VERSION 5.8 ;
BUSBITCHARS "[]" ;
DIVIDERCHAR "/" ;
UNITS
    DATABASE MICRONS 1000 ;
END UNITS

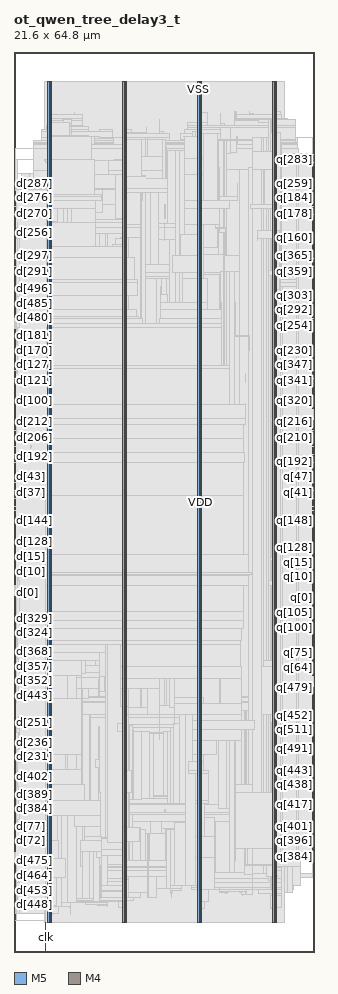
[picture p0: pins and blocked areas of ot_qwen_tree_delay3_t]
MACRO ot_qwen_tree_delay3_t
  FOREIGN ot_qwen_tree_delay3_t 0 0 ;
  CLASS BLOCK ;
  SIZE 21.6 BY 64.8 ;
  PIN clk
    DIRECTION INPUT ;
    USE SIGNAL ;
    PORT
      LAYER M5 ;
        RECT  2.256 0 2.28 0.084 ;
    END
    PORT
      LAYER M5 ;
        RECT  2.256 0.016 2.28 2.137 ;
    END
  END clk
  PIN d[0]
    DIRECTION INPUT ;
    USE SIGNAL ;
    PORT
      LAYER M4 ;
        RECT  0 26.448 0.084 26.472 ;
    END
  END d[0]
  PIN d[100]
    DIRECTION INPUT ;
    USE SIGNAL ;
    PORT
      LAYER M4 ;
        RECT  0 39.12 0.084 39.144 ;
    END
  END d[100]
  PIN d[101]
    DIRECTION INPUT ;
    USE SIGNAL ;
    PORT
      LAYER M4 ;
        RECT  0 39.216 0.084 39.24 ;
    END
  END d[101]
  PIN d[102]
    DIRECTION INPUT ;
    USE SIGNAL ;
    PORT
      LAYER M4 ;
        RECT  0 39.312 0.084 39.336 ;
    END
  END d[102]
  PIN d[103]
    DIRECTION INPUT ;
    USE SIGNAL ;
    PORT
      LAYER M4 ;
        RECT  0 39.408 0.084 39.432 ;
    END
  END d[103]
  PIN d[104]
    DIRECTION INPUT ;
    USE SIGNAL ;
    PORT
      LAYER M4 ;
        RECT  0 39.504 0.084 39.528 ;
    END
  END d[104]
  PIN d[105]
    DIRECTION INPUT ;
    USE SIGNAL ;
    PORT
      LAYER M4 ;
        RECT  0 39.6 0.084 39.624 ;
    END
  END d[105]
  PIN d[106]
    DIRECTION INPUT ;
    USE SIGNAL ;
    PORT
      LAYER M4 ;
        RECT  0 39.696 0.084 39.72 ;
    END
  END d[106]
  PIN d[107]
    DIRECTION INPUT ;
    USE SIGNAL ;
    PORT
      LAYER M4 ;
        RECT  0 39.792 0.084 39.816 ;
    END
  END d[107]
  PIN d[108]
    DIRECTION INPUT ;
    USE SIGNAL ;
    PORT
      LAYER M4 ;
        RECT  0 39.888 0.084 39.912 ;
    END
  END d[108]
  PIN d[109]
    DIRECTION INPUT ;
    USE SIGNAL ;
    PORT
      LAYER M4 ;
        RECT  0 39.984 0.084 40.008 ;
    END
  END d[109]
  PIN d[10]
    DIRECTION INPUT ;
    USE SIGNAL ;
    PORT
      LAYER M4 ;
        RECT  0 27.408 0.084 27.432 ;
    END
  END d[10]
  PIN d[110]
    DIRECTION INPUT ;
    USE SIGNAL ;
    PORT
      LAYER M4 ;
        RECT  0 40.08 0.084 40.104 ;
    END
  END d[110]
  PIN d[111]
    DIRECTION INPUT ;
    USE SIGNAL ;
    PORT
      LAYER M4 ;
        RECT  0 40.176 0.084 40.2 ;
    END
  END d[111]
  PIN d[112]
    DIRECTION INPUT ;
    USE SIGNAL ;
    PORT
      LAYER M4 ;
        RECT  0 40.272 0.084 40.296 ;
    END
  END d[112]
  PIN d[113]
    DIRECTION INPUT ;
    USE SIGNAL ;
    PORT
      LAYER M4 ;
        RECT  0 40.368 0.084 40.392 ;
    END
  END d[113]
  PIN d[114]
    DIRECTION INPUT ;
    USE SIGNAL ;
    PORT
      LAYER M4 ;
        RECT  0 40.464 0.084 40.488 ;
    END
  END d[114]
  PIN d[115]
    DIRECTION INPUT ;
    USE SIGNAL ;
    PORT
      LAYER M4 ;
        RECT  0 40.56 0.084 40.584 ;
    END
  END d[115]
  PIN d[116]
    DIRECTION INPUT ;
    USE SIGNAL ;
    PORT
      LAYER M4 ;
        RECT  0 40.656 0.084 40.68 ;
    END
  END d[116]
  PIN d[117]
    DIRECTION INPUT ;
    USE SIGNAL ;
    PORT
      LAYER M4 ;
        RECT  0 40.752 0.084 40.776 ;
    END
  END d[117]
  PIN d[118]
    DIRECTION INPUT ;
    USE SIGNAL ;
    PORT
      LAYER M4 ;
        RECT  0 40.848 0.084 40.872 ;
    END
  END d[118]
  PIN d[119]
    DIRECTION INPUT ;
    USE SIGNAL ;
    PORT
      LAYER M4 ;
        RECT  0 40.944 0.084 40.968 ;
    END
  END d[119]
  PIN d[11]
    DIRECTION INPUT ;
    USE SIGNAL ;
    PORT
      LAYER M4 ;
        RECT  0 27.504 0.084 27.528 ;
    END
  END d[11]
  PIN d[120]
    DIRECTION INPUT ;
    USE SIGNAL ;
    PORT
      LAYER M4 ;
        RECT  0 41.04 0.084 41.064 ;
    END
  END d[120]
  PIN d[121]
    DIRECTION INPUT ;
    USE SIGNAL ;
    PORT
      LAYER M4 ;
        RECT  0 41.136 0.084 41.16 ;
    END
  END d[121]
  PIN d[122]
    DIRECTION INPUT ;
    USE SIGNAL ;
    PORT
      LAYER M4 ;
        RECT  0 41.232 0.084 41.256 ;
    END
  END d[122]
  PIN d[123]
    DIRECTION INPUT ;
    USE SIGNAL ;
    PORT
      LAYER M4 ;
        RECT  0 41.328 0.084 41.352 ;
    END
  END d[123]
  PIN d[124]
    DIRECTION INPUT ;
    USE SIGNAL ;
    PORT
      LAYER M4 ;
        RECT  0 41.424 0.084 41.448 ;
    END
  END d[124]
  PIN d[125]
    DIRECTION INPUT ;
    USE SIGNAL ;
    PORT
      LAYER M4 ;
        RECT  0 41.52 0.084 41.544 ;
    END
  END d[125]
  PIN d[126]
    DIRECTION INPUT ;
    USE SIGNAL ;
    PORT
      LAYER M4 ;
        RECT  0 41.616 0.084 41.64 ;
    END
  END d[126]
  PIN d[127]
    DIRECTION INPUT ;
    USE SIGNAL ;
    PORT
      LAYER M4 ;
        RECT  0 41.712 0.084 41.736 ;
    END
  END d[127]
  PIN d[128]
    DIRECTION INPUT ;
    USE SIGNAL ;
    PORT
      LAYER M4 ;
        RECT  0 29.52 0.084 29.544 ;
    END
  END d[128]
  PIN d[129]
    DIRECTION INPUT ;
    USE SIGNAL ;
    PORT
      LAYER M4 ;
        RECT  0 29.616 0.084 29.64 ;
    END
  END d[129]
  PIN d[12]
    DIRECTION INPUT ;
    USE SIGNAL ;
    PORT
      LAYER M4 ;
        RECT  0 27.6 0.084 27.624 ;
    END
  END d[12]
  PIN d[130]
    DIRECTION INPUT ;
    USE SIGNAL ;
    PORT
      LAYER M4 ;
        RECT  0 29.712 0.084 29.736 ;
    END
  END d[130]
  PIN d[131]
    DIRECTION INPUT ;
    USE SIGNAL ;
    PORT
      LAYER M4 ;
        RECT  0 29.808 0.084 29.832 ;
    END
  END d[131]
  PIN d[132]
    DIRECTION INPUT ;
    USE SIGNAL ;
    PORT
      LAYER M4 ;
        RECT  0 29.904 0.084 29.928 ;
    END
  END d[132]
  PIN d[133]
    DIRECTION INPUT ;
    USE SIGNAL ;
    PORT
      LAYER M4 ;
        RECT  0 30 0.084 30.024 ;
    END
  END d[133]
  PIN d[134]
    DIRECTION INPUT ;
    USE SIGNAL ;
    PORT
      LAYER M4 ;
        RECT  0 30.096 0.084 30.12 ;
    END
  END d[134]
  PIN d[135]
    DIRECTION INPUT ;
    USE SIGNAL ;
    PORT
      LAYER M4 ;
        RECT  0 30.192 0.084 30.216 ;
    END
  END d[135]
  PIN d[136]
    DIRECTION INPUT ;
    USE SIGNAL ;
    PORT
      LAYER M4 ;
        RECT  0 30.288 0.084 30.312 ;
    END
  END d[136]
  PIN d[137]
    DIRECTION INPUT ;
    USE SIGNAL ;
    PORT
      LAYER M4 ;
        RECT  0 30.384 0.084 30.408 ;
    END
  END d[137]
  PIN d[138]
    DIRECTION INPUT ;
    USE SIGNAL ;
    PORT
      LAYER M4 ;
        RECT  0 30.48 0.084 30.504 ;
    END
  END d[138]
  PIN d[139]
    DIRECTION INPUT ;
    USE SIGNAL ;
    PORT
      LAYER M4 ;
        RECT  0 30.576 0.084 30.6 ;
    END
  END d[139]
  PIN d[13]
    DIRECTION INPUT ;
    USE SIGNAL ;
    PORT
      LAYER M4 ;
        RECT  0 27.696 0.084 27.72 ;
    END
  END d[13]
  PIN d[140]
    DIRECTION INPUT ;
    USE SIGNAL ;
    PORT
      LAYER M4 ;
        RECT  0 30.672 0.084 30.696 ;
    END
  END d[140]
  PIN d[141]
    DIRECTION INPUT ;
    USE SIGNAL ;
    PORT
      LAYER M4 ;
        RECT  0 30.768 0.084 30.792 ;
    END
  END d[141]
  PIN d[142]
    DIRECTION INPUT ;
    USE SIGNAL ;
    PORT
      LAYER M4 ;
        RECT  0 30.864 0.084 30.888 ;
    END
  END d[142]
  PIN d[143]
    DIRECTION INPUT ;
    USE SIGNAL ;
    PORT
      LAYER M4 ;
        RECT  0 30.96 0.084 30.984 ;
    END
  END d[143]
  PIN d[144]
    DIRECTION INPUT ;
    USE SIGNAL ;
    PORT
      LAYER M4 ;
        RECT  0 31.056 0.084 31.08 ;
    END
  END d[144]
  PIN d[145]
    DIRECTION INPUT ;
    USE SIGNAL ;
    PORT
      LAYER M4 ;
        RECT  0 31.152 0.084 31.176 ;
    END
  END d[145]
  PIN d[146]
    DIRECTION INPUT ;
    USE SIGNAL ;
    PORT
      LAYER M4 ;
        RECT  0 31.248 0.084 31.272 ;
    END
  END d[146]
  PIN d[147]
    DIRECTION INPUT ;
    USE SIGNAL ;
    PORT
      LAYER M4 ;
        RECT  0 31.344 0.084 31.368 ;
    END
  END d[147]
  PIN d[148]
    DIRECTION INPUT ;
    USE SIGNAL ;
    PORT
      LAYER M4 ;
        RECT  0 31.44 0.084 31.464 ;
    END
  END d[148]
  PIN d[149]
    DIRECTION INPUT ;
    USE SIGNAL ;
    PORT
      LAYER M4 ;
        RECT  0 31.536 0.084 31.56 ;
    END
  END d[149]
  PIN d[14]
    DIRECTION INPUT ;
    USE SIGNAL ;
    PORT
      LAYER M4 ;
        RECT  0 27.792 0.084 27.816 ;
    END
  END d[14]
  PIN d[150]
    DIRECTION INPUT ;
    USE SIGNAL ;
    PORT
      LAYER M4 ;
        RECT  0 31.632 0.084 31.656 ;
    END
  END d[150]
  PIN d[151]
    DIRECTION INPUT ;
    USE SIGNAL ;
    PORT
      LAYER M4 ;
        RECT  0 31.728 0.084 31.752 ;
    END
  END d[151]
  PIN d[152]
    DIRECTION INPUT ;
    USE SIGNAL ;
    PORT
      LAYER M4 ;
        RECT  0 31.824 0.084 31.848 ;
    END
  END d[152]
  PIN d[153]
    DIRECTION INPUT ;
    USE SIGNAL ;
    PORT
      LAYER M4 ;
        RECT  0 31.92 0.084 31.944 ;
    END
  END d[153]
  PIN d[154]
    DIRECTION INPUT ;
    USE SIGNAL ;
    PORT
      LAYER M4 ;
        RECT  0 32.016 0.084 32.04 ;
    END
  END d[154]
  PIN d[155]
    DIRECTION INPUT ;
    USE SIGNAL ;
    PORT
      LAYER M4 ;
        RECT  0 32.112 0.084 32.136 ;
    END
  END d[155]
  PIN d[156]
    DIRECTION INPUT ;
    USE SIGNAL ;
    PORT
      LAYER M4 ;
        RECT  0 32.208 0.084 32.232 ;
    END
  END d[156]
  PIN d[157]
    DIRECTION INPUT ;
    USE SIGNAL ;
    PORT
      LAYER M4 ;
        RECT  0 32.304 0.084 32.328 ;
    END
  END d[157]
  PIN d[158]
    DIRECTION INPUT ;
    USE SIGNAL ;
    PORT
      LAYER M4 ;
        RECT  0 32.4 0.084 32.424 ;
    END
  END d[158]
  PIN d[159]
    DIRECTION INPUT ;
    USE SIGNAL ;
    PORT
      LAYER M4 ;
        RECT  0 32.496 0.084 32.52 ;
    END
  END d[159]
  PIN d[15]
    DIRECTION INPUT ;
    USE SIGNAL ;
    PORT
      LAYER M4 ;
        RECT  0 27.888 0.084 27.912 ;
    END
  END d[15]
  PIN d[160]
    DIRECTION INPUT ;
    USE SIGNAL ;
    PORT
      LAYER M4 ;
        RECT  0 41.808 0.084 41.832 ;
    END
  END d[160]
  PIN d[161]
    DIRECTION INPUT ;
    USE SIGNAL ;
    PORT
      LAYER M4 ;
        RECT  0 41.904 0.084 41.928 ;
    END
  END d[161]
  PIN d[162]
    DIRECTION INPUT ;
    USE SIGNAL ;
    PORT
      LAYER M4 ;
        RECT  0 42 0.084 42.024 ;
    END
  END d[162]
  PIN d[163]
    DIRECTION INPUT ;
    USE SIGNAL ;
    PORT
      LAYER M4 ;
        RECT  0 42.096 0.084 42.12 ;
    END
  END d[163]
  PIN d[164]
    DIRECTION INPUT ;
    USE SIGNAL ;
    PORT
      LAYER M4 ;
        RECT  0 42.192 0.084 42.216 ;
    END
  END d[164]
  PIN d[165]
    DIRECTION INPUT ;
    USE SIGNAL ;
    PORT
      LAYER M4 ;
        RECT  0 42.288 0.084 42.312 ;
    END
  END d[165]
  PIN d[166]
    DIRECTION INPUT ;
    USE SIGNAL ;
    PORT
      LAYER M4 ;
        RECT  0 42.384 0.084 42.408 ;
    END
  END d[166]
  PIN d[167]
    DIRECTION INPUT ;
    USE SIGNAL ;
    PORT
      LAYER M4 ;
        RECT  0 42.48 0.084 42.504 ;
    END
  END d[167]
  PIN d[168]
    DIRECTION INPUT ;
    USE SIGNAL ;
    PORT
      LAYER M4 ;
        RECT  0 42.576 0.084 42.6 ;
    END
  END d[168]
  PIN d[169]
    DIRECTION INPUT ;
    USE SIGNAL ;
    PORT
      LAYER M4 ;
        RECT  0 42.672 0.084 42.696 ;
    END
  END d[169]
  PIN d[16]
    DIRECTION INPUT ;
    USE SIGNAL ;
    PORT
      LAYER M4 ;
        RECT  0 27.984 0.084 28.008 ;
    END
  END d[16]
  PIN d[170]
    DIRECTION INPUT ;
    USE SIGNAL ;
    PORT
      LAYER M4 ;
        RECT  0 42.768 0.084 42.792 ;
    END
  END d[170]
  PIN d[171]
    DIRECTION INPUT ;
    USE SIGNAL ;
    PORT
      LAYER M4 ;
        RECT  0 42.864 0.084 42.888 ;
    END
  END d[171]
  PIN d[172]
    DIRECTION INPUT ;
    USE SIGNAL ;
    PORT
      LAYER M4 ;
        RECT  0 42.96 0.084 42.984 ;
    END
  END d[172]
  PIN d[173]
    DIRECTION INPUT ;
    USE SIGNAL ;
    PORT
      LAYER M4 ;
        RECT  0 43.056 0.084 43.08 ;
    END
  END d[173]
  PIN d[174]
    DIRECTION INPUT ;
    USE SIGNAL ;
    PORT
      LAYER M4 ;
        RECT  0 43.152 0.084 43.176 ;
    END
  END d[174]
  PIN d[175]
    DIRECTION INPUT ;
    USE SIGNAL ;
    PORT
      LAYER M4 ;
        RECT  0 43.248 0.084 43.272 ;
    END
  END d[175]
  PIN d[176]
    DIRECTION INPUT ;
    USE SIGNAL ;
    PORT
      LAYER M4 ;
        RECT  0 43.344 0.084 43.368 ;
    END
  END d[176]
  PIN d[177]
    DIRECTION INPUT ;
    USE SIGNAL ;
    PORT
      LAYER M4 ;
        RECT  0 43.44 0.084 43.464 ;
    END
  END d[177]
  PIN d[178]
    DIRECTION INPUT ;
    USE SIGNAL ;
    PORT
      LAYER M4 ;
        RECT  0 43.536 0.084 43.56 ;
    END
  END d[178]
  PIN d[179]
    DIRECTION INPUT ;
    USE SIGNAL ;
    PORT
      LAYER M4 ;
        RECT  0 43.632 0.084 43.656 ;
    END
  END d[179]
  PIN d[17]
    DIRECTION INPUT ;
    USE SIGNAL ;
    PORT
      LAYER M4 ;
        RECT  0 28.08 0.084 28.104 ;
    END
  END d[17]
  PIN d[180]
    DIRECTION INPUT ;
    USE SIGNAL ;
    PORT
      LAYER M4 ;
        RECT  0 43.728 0.084 43.752 ;
    END
  END d[180]
  PIN d[181]
    DIRECTION INPUT ;
    USE SIGNAL ;
    PORT
      LAYER M4 ;
        RECT  0 43.824 0.084 43.848 ;
    END
  END d[181]
  PIN d[182]
    DIRECTION INPUT ;
    USE SIGNAL ;
    PORT
      LAYER M4 ;
        RECT  0 43.92 0.084 43.944 ;
    END
  END d[182]
  PIN d[183]
    DIRECTION INPUT ;
    USE SIGNAL ;
    PORT
      LAYER M4 ;
        RECT  0 44.016 0.084 44.04 ;
    END
  END d[183]
  PIN d[184]
    DIRECTION INPUT ;
    USE SIGNAL ;
    PORT
      LAYER M4 ;
        RECT  0 44.112 0.084 44.136 ;
    END
  END d[184]
  PIN d[185]
    DIRECTION INPUT ;
    USE SIGNAL ;
    PORT
      LAYER M4 ;
        RECT  0 44.208 0.084 44.232 ;
    END
  END d[185]
  PIN d[186]
    DIRECTION INPUT ;
    USE SIGNAL ;
    PORT
      LAYER M4 ;
        RECT  0 44.304 0.084 44.328 ;
    END
  END d[186]
  PIN d[187]
    DIRECTION INPUT ;
    USE SIGNAL ;
    PORT
      LAYER M4 ;
        RECT  0 44.4 0.084 44.424 ;
    END
  END d[187]
  PIN d[188]
    DIRECTION INPUT ;
    USE SIGNAL ;
    PORT
      LAYER M4 ;
        RECT  0 44.496 0.084 44.52 ;
    END
  END d[188]
  PIN d[189]
    DIRECTION INPUT ;
    USE SIGNAL ;
    PORT
      LAYER M4 ;
        RECT  0 44.592 0.084 44.616 ;
    END
  END d[189]
  PIN d[18]
    DIRECTION INPUT ;
    USE SIGNAL ;
    PORT
      LAYER M4 ;
        RECT  0 28.176 0.084 28.2 ;
    END
  END d[18]
  PIN d[190]
    DIRECTION INPUT ;
    USE SIGNAL ;
    PORT
      LAYER M4 ;
        RECT  0 44.688 0.084 44.712 ;
    END
  END d[190]
  PIN d[191]
    DIRECTION INPUT ;
    USE SIGNAL ;
    PORT
      LAYER M4 ;
        RECT  0 44.784 0.084 44.808 ;
    END
  END d[191]
  PIN d[192]
    DIRECTION INPUT ;
    USE SIGNAL ;
    PORT
      LAYER M4 ;
        RECT  0 35.664 0.084 35.688 ;
    END
  END d[192]
  PIN d[193]
    DIRECTION INPUT ;
    USE SIGNAL ;
    PORT
      LAYER M4 ;
        RECT  0 35.76 0.084 35.784 ;
    END
  END d[193]
  PIN d[194]
    DIRECTION INPUT ;
    USE SIGNAL ;
    PORT
      LAYER M4 ;
        RECT  0 35.856 0.084 35.88 ;
    END
  END d[194]
  PIN d[195]
    DIRECTION INPUT ;
    USE SIGNAL ;
    PORT
      LAYER M4 ;
        RECT  0 35.952 0.084 35.976 ;
    END
  END d[195]
  PIN d[196]
    DIRECTION INPUT ;
    USE SIGNAL ;
    PORT
      LAYER M4 ;
        RECT  0 36.048 0.084 36.072 ;
    END
  END d[196]
  PIN d[197]
    DIRECTION INPUT ;
    USE SIGNAL ;
    PORT
      LAYER M4 ;
        RECT  0 36.144 0.084 36.168 ;
    END
  END d[197]
  PIN d[198]
    DIRECTION INPUT ;
    USE SIGNAL ;
    PORT
      LAYER M4 ;
        RECT  0 36.24 0.084 36.264 ;
    END
  END d[198]
  PIN d[199]
    DIRECTION INPUT ;
    USE SIGNAL ;
    PORT
      LAYER M4 ;
        RECT  0 36.336 0.084 36.36 ;
    END
  END d[199]
  PIN d[19]
    DIRECTION INPUT ;
    USE SIGNAL ;
    PORT
      LAYER M4 ;
        RECT  0 28.272 0.084 28.296 ;
    END
  END d[19]
  PIN d[1]
    DIRECTION INPUT ;
    USE SIGNAL ;
    PORT
      LAYER M4 ;
        RECT  0 26.544 0.084 26.568 ;
    END
  END d[1]
  PIN d[200]
    DIRECTION INPUT ;
    USE SIGNAL ;
    PORT
      LAYER M4 ;
        RECT  0 36.432 0.084 36.456 ;
    END
  END d[200]
  PIN d[201]
    DIRECTION INPUT ;
    USE SIGNAL ;
    PORT
      LAYER M4 ;
        RECT  0 36.528 0.084 36.552 ;
    END
  END d[201]
  PIN d[202]
    DIRECTION INPUT ;
    USE SIGNAL ;
    PORT
      LAYER M4 ;
        RECT  0 36.624 0.084 36.648 ;
    END
  END d[202]
  PIN d[203]
    DIRECTION INPUT ;
    USE SIGNAL ;
    PORT
      LAYER M4 ;
        RECT  0 36.72 0.084 36.744 ;
    END
  END d[203]
  PIN d[204]
    DIRECTION INPUT ;
    USE SIGNAL ;
    PORT
      LAYER M4 ;
        RECT  0 36.816 0.084 36.84 ;
    END
  END d[204]
  PIN d[205]
    DIRECTION INPUT ;
    USE SIGNAL ;
    PORT
      LAYER M4 ;
        RECT  0 36.912 0.084 36.936 ;
    END
  END d[205]
  PIN d[206]
    DIRECTION INPUT ;
    USE SIGNAL ;
    PORT
      LAYER M4 ;
        RECT  0 37.008 0.084 37.032 ;
    END
  END d[206]
  PIN d[207]
    DIRECTION INPUT ;
    USE SIGNAL ;
    PORT
      LAYER M4 ;
        RECT  0 37.104 0.084 37.128 ;
    END
  END d[207]
  PIN d[208]
    DIRECTION INPUT ;
    USE SIGNAL ;
    PORT
      LAYER M4 ;
        RECT  0 37.2 0.084 37.224 ;
    END
  END d[208]
  PIN d[209]
    DIRECTION INPUT ;
    USE SIGNAL ;
    PORT
      LAYER M4 ;
        RECT  0 37.296 0.084 37.32 ;
    END
  END d[209]
  PIN d[20]
    DIRECTION INPUT ;
    USE SIGNAL ;
    PORT
      LAYER M4 ;
        RECT  0 28.368 0.084 28.392 ;
    END
  END d[20]
  PIN d[210]
    DIRECTION INPUT ;
    USE SIGNAL ;
    PORT
      LAYER M4 ;
        RECT  0 37.392 0.084 37.416 ;
    END
  END d[210]
  PIN d[211]
    DIRECTION INPUT ;
    USE SIGNAL ;
    PORT
      LAYER M4 ;
        RECT  0 37.488 0.084 37.512 ;
    END
  END d[211]
  PIN d[212]
    DIRECTION INPUT ;
    USE SIGNAL ;
    PORT
      LAYER M4 ;
        RECT  0 37.584 0.084 37.608 ;
    END
  END d[212]
  PIN d[213]
    DIRECTION INPUT ;
    USE SIGNAL ;
    PORT
      LAYER M4 ;
        RECT  0 37.68 0.084 37.704 ;
    END
  END d[213]
  PIN d[214]
    DIRECTION INPUT ;
    USE SIGNAL ;
    PORT
      LAYER M4 ;
        RECT  0 37.776 0.084 37.8 ;
    END
  END d[214]
  PIN d[215]
    DIRECTION INPUT ;
    USE SIGNAL ;
    PORT
      LAYER M4 ;
        RECT  0 37.872 0.084 37.896 ;
    END
  END d[215]
  PIN d[216]
    DIRECTION INPUT ;
    USE SIGNAL ;
    PORT
      LAYER M4 ;
        RECT  0 37.968 0.084 37.992 ;
    END
  END d[216]
  PIN d[217]
    DIRECTION INPUT ;
    USE SIGNAL ;
    PORT
      LAYER M4 ;
        RECT  0 38.064 0.084 38.088 ;
    END
  END d[217]
  PIN d[218]
    DIRECTION INPUT ;
    USE SIGNAL ;
    PORT
      LAYER M4 ;
        RECT  0 38.16 0.084 38.184 ;
    END
  END d[218]
  PIN d[219]
    DIRECTION INPUT ;
    USE SIGNAL ;
    PORT
      LAYER M4 ;
        RECT  0 38.256 0.084 38.28 ;
    END
  END d[219]
  PIN d[21]
    DIRECTION INPUT ;
    USE SIGNAL ;
    PORT
      LAYER M4 ;
        RECT  0 28.464 0.084 28.488 ;
    END
  END d[21]
  PIN d[220]
    DIRECTION INPUT ;
    USE SIGNAL ;
    PORT
      LAYER M4 ;
        RECT  0 38.352 0.084 38.376 ;
    END
  END d[220]
  PIN d[221]
    DIRECTION INPUT ;
    USE SIGNAL ;
    PORT
      LAYER M4 ;
        RECT  0 38.448 0.084 38.472 ;
    END
  END d[221]
  PIN d[222]
    DIRECTION INPUT ;
    USE SIGNAL ;
    PORT
      LAYER M4 ;
        RECT  0 38.544 0.084 38.568 ;
    END
  END d[222]
  PIN d[223]
    DIRECTION INPUT ;
    USE SIGNAL ;
    PORT
      LAYER M4 ;
        RECT  0 38.64 0.084 38.664 ;
    END
  END d[223]
  PIN d[224]
    DIRECTION INPUT ;
    USE SIGNAL ;
    PORT
      LAYER M4 ;
        RECT  0 13.392 0.084 13.416 ;
    END
  END d[224]
  PIN d[225]
    DIRECTION INPUT ;
    USE SIGNAL ;
    PORT
      LAYER M4 ;
        RECT  0 13.488 0.084 13.512 ;
    END
  END d[225]
  PIN d[226]
    DIRECTION INPUT ;
    USE SIGNAL ;
    PORT
      LAYER M4 ;
        RECT  0 13.584 0.084 13.608 ;
    END
  END d[226]
  PIN d[227]
    DIRECTION INPUT ;
    USE SIGNAL ;
    PORT
      LAYER M4 ;
        RECT  0 13.68 0.084 13.704 ;
    END
  END d[227]
  PIN d[228]
    DIRECTION INPUT ;
    USE SIGNAL ;
    PORT
      LAYER M4 ;
        RECT  0 13.776 0.084 13.8 ;
    END
  END d[228]
  PIN d[229]
    DIRECTION INPUT ;
    USE SIGNAL ;
    PORT
      LAYER M4 ;
        RECT  0 13.872 0.084 13.896 ;
    END
  END d[229]
  PIN d[22]
    DIRECTION INPUT ;
    USE SIGNAL ;
    PORT
      LAYER M4 ;
        RECT  0 28.56 0.084 28.584 ;
    END
  END d[22]
  PIN d[230]
    DIRECTION INPUT ;
    USE SIGNAL ;
    PORT
      LAYER M4 ;
        RECT  0 13.968 0.084 13.992 ;
    END
  END d[230]
  PIN d[231]
    DIRECTION INPUT ;
    USE SIGNAL ;
    PORT
      LAYER M4 ;
        RECT  0 14.064 0.084 14.088 ;
    END
  END d[231]
  PIN d[232]
    DIRECTION INPUT ;
    USE SIGNAL ;
    PORT
      LAYER M4 ;
        RECT  0 14.16 0.084 14.184 ;
    END
  END d[232]
  PIN d[233]
    DIRECTION INPUT ;
    USE SIGNAL ;
    PORT
      LAYER M4 ;
        RECT  0 14.256 0.084 14.28 ;
    END
  END d[233]
  PIN d[234]
    DIRECTION INPUT ;
    USE SIGNAL ;
    PORT
      LAYER M4 ;
        RECT  0 14.352 0.084 14.376 ;
    END
  END d[234]
  PIN d[235]
    DIRECTION INPUT ;
    USE SIGNAL ;
    PORT
      LAYER M4 ;
        RECT  0 14.448 0.084 14.472 ;
    END
  END d[235]
  PIN d[236]
    DIRECTION INPUT ;
    USE SIGNAL ;
    PORT
      LAYER M4 ;
        RECT  0 14.544 0.084 14.568 ;
    END
  END d[236]
  PIN d[237]
    DIRECTION INPUT ;
    USE SIGNAL ;
    PORT
      LAYER M4 ;
        RECT  0 14.64 0.084 14.664 ;
    END
  END d[237]
  PIN d[238]
    DIRECTION INPUT ;
    USE SIGNAL ;
    PORT
      LAYER M4 ;
        RECT  0 14.736 0.084 14.76 ;
    END
  END d[238]
  PIN d[239]
    DIRECTION INPUT ;
    USE SIGNAL ;
    PORT
      LAYER M4 ;
        RECT  0 14.832 0.084 14.856 ;
    END
  END d[239]
  PIN d[23]
    DIRECTION INPUT ;
    USE SIGNAL ;
    PORT
      LAYER M4 ;
        RECT  0 28.656 0.084 28.68 ;
    END
  END d[23]
  PIN d[240]
    DIRECTION INPUT ;
    USE SIGNAL ;
    PORT
      LAYER M4 ;
        RECT  0 14.928 0.084 14.952 ;
    END
  END d[240]
  PIN d[241]
    DIRECTION INPUT ;
    USE SIGNAL ;
    PORT
      LAYER M4 ;
        RECT  0 15.024 0.084 15.048 ;
    END
  END d[241]
  PIN d[242]
    DIRECTION INPUT ;
    USE SIGNAL ;
    PORT
      LAYER M4 ;
        RECT  0 15.12 0.084 15.144 ;
    END
  END d[242]
  PIN d[243]
    DIRECTION INPUT ;
    USE SIGNAL ;
    PORT
      LAYER M4 ;
        RECT  0 15.216 0.084 15.24 ;
    END
  END d[243]
  PIN d[244]
    DIRECTION INPUT ;
    USE SIGNAL ;
    PORT
      LAYER M4 ;
        RECT  0 15.312 0.084 15.336 ;
    END
  END d[244]
  PIN d[245]
    DIRECTION INPUT ;
    USE SIGNAL ;
    PORT
      LAYER M4 ;
        RECT  0 15.408 0.084 15.432 ;
    END
  END d[245]
  PIN d[246]
    DIRECTION INPUT ;
    USE SIGNAL ;
    PORT
      LAYER M4 ;
        RECT  0 15.504 0.084 15.528 ;
    END
  END d[246]
  PIN d[247]
    DIRECTION INPUT ;
    USE SIGNAL ;
    PORT
      LAYER M4 ;
        RECT  0 15.6 0.084 15.624 ;
    END
  END d[247]
  PIN d[248]
    DIRECTION INPUT ;
    USE SIGNAL ;
    PORT
      LAYER M4 ;
        RECT  0 15.696 0.084 15.72 ;
    END
  END d[248]
  PIN d[249]
    DIRECTION INPUT ;
    USE SIGNAL ;
    PORT
      LAYER M4 ;
        RECT  0 15.792 0.084 15.816 ;
    END
  END d[249]
  PIN d[24]
    DIRECTION INPUT ;
    USE SIGNAL ;
    PORT
      LAYER M4 ;
        RECT  0 28.752 0.084 28.776 ;
    END
  END d[24]
  PIN d[250]
    DIRECTION INPUT ;
    USE SIGNAL ;
    PORT
      LAYER M4 ;
        RECT  0 15.888 0.084 15.912 ;
    END
  END d[250]
  PIN d[251]
    DIRECTION INPUT ;
    USE SIGNAL ;
    PORT
      LAYER M4 ;
        RECT  0 15.984 0.084 16.008 ;
    END
  END d[251]
  PIN d[252]
    DIRECTION INPUT ;
    USE SIGNAL ;
    PORT
      LAYER M4 ;
        RECT  0 16.08 0.084 16.104 ;
    END
  END d[252]
  PIN d[253]
    DIRECTION INPUT ;
    USE SIGNAL ;
    PORT
      LAYER M4 ;
        RECT  0 16.176 0.084 16.2 ;
    END
  END d[253]
  PIN d[254]
    DIRECTION INPUT ;
    USE SIGNAL ;
    PORT
      LAYER M4 ;
        RECT  0 16.272 0.084 16.296 ;
    END
  END d[254]
  PIN d[255]
    DIRECTION INPUT ;
    USE SIGNAL ;
    PORT
      LAYER M4 ;
        RECT  0 16.368 0.084 16.392 ;
    END
  END d[255]
  PIN d[256]
    DIRECTION INPUT ;
    USE SIGNAL ;
    PORT
      LAYER M4 ;
        RECT  0 51.792 0.084 51.816 ;
    END
  END d[256]
  PIN d[257]
    DIRECTION INPUT ;
    USE SIGNAL ;
    PORT
      LAYER M4 ;
        RECT  0 51.888 0.084 51.912 ;
    END
  END d[257]
  PIN d[258]
    DIRECTION INPUT ;
    USE SIGNAL ;
    PORT
      LAYER M4 ;
        RECT  0 51.984 0.084 52.008 ;
    END
  END d[258]
  PIN d[259]
    DIRECTION INPUT ;
    USE SIGNAL ;
    PORT
      LAYER M4 ;
        RECT  0 52.08 0.084 52.104 ;
    END
  END d[259]
  PIN d[25]
    DIRECTION INPUT ;
    USE SIGNAL ;
    PORT
      LAYER M4 ;
        RECT  0 28.848 0.084 28.872 ;
    END
  END d[25]
  PIN d[260]
    DIRECTION INPUT ;
    USE SIGNAL ;
    PORT
      LAYER M4 ;
        RECT  0 52.176 0.084 52.2 ;
    END
  END d[260]
  PIN d[261]
    DIRECTION INPUT ;
    USE SIGNAL ;
    PORT
      LAYER M4 ;
        RECT  0 52.272 0.084 52.296 ;
    END
  END d[261]
  PIN d[262]
    DIRECTION INPUT ;
    USE SIGNAL ;
    PORT
      LAYER M4 ;
        RECT  0 52.368 0.084 52.392 ;
    END
  END d[262]
  PIN d[263]
    DIRECTION INPUT ;
    USE SIGNAL ;
    PORT
      LAYER M4 ;
        RECT  0 52.464 0.084 52.488 ;
    END
  END d[263]
  PIN d[264]
    DIRECTION INPUT ;
    USE SIGNAL ;
    PORT
      LAYER M4 ;
        RECT  0 52.56 0.084 52.584 ;
    END
  END d[264]
  PIN d[265]
    DIRECTION INPUT ;
    USE SIGNAL ;
    PORT
      LAYER M4 ;
        RECT  0 52.656 0.084 52.68 ;
    END
  END d[265]
  PIN d[266]
    DIRECTION INPUT ;
    USE SIGNAL ;
    PORT
      LAYER M4 ;
        RECT  0 52.752 0.084 52.776 ;
    END
  END d[266]
  PIN d[267]
    DIRECTION INPUT ;
    USE SIGNAL ;
    PORT
      LAYER M4 ;
        RECT  0 52.848 0.084 52.872 ;
    END
  END d[267]
  PIN d[268]
    DIRECTION INPUT ;
    USE SIGNAL ;
    PORT
      LAYER M4 ;
        RECT  0 52.944 0.084 52.968 ;
    END
  END d[268]
  PIN d[269]
    DIRECTION INPUT ;
    USE SIGNAL ;
    PORT
      LAYER M4 ;
        RECT  0 53.04 0.084 53.064 ;
    END
  END d[269]
  PIN d[26]
    DIRECTION INPUT ;
    USE SIGNAL ;
    PORT
      LAYER M4 ;
        RECT  0 28.944 0.084 28.968 ;
    END
  END d[26]
  PIN d[270]
    DIRECTION INPUT ;
    USE SIGNAL ;
    PORT
      LAYER M4 ;
        RECT  0 53.136 0.084 53.16 ;
    END
  END d[270]
  PIN d[271]
    DIRECTION INPUT ;
    USE SIGNAL ;
    PORT
      LAYER M4 ;
        RECT  0 53.232 0.084 53.256 ;
    END
  END d[271]
  PIN d[272]
    DIRECTION INPUT ;
    USE SIGNAL ;
    PORT
      LAYER M4 ;
        RECT  0 53.328 0.084 53.352 ;
    END
  END d[272]
  PIN d[273]
    DIRECTION INPUT ;
    USE SIGNAL ;
    PORT
      LAYER M4 ;
        RECT  0 53.424 0.084 53.448 ;
    END
  END d[273]
  PIN d[274]
    DIRECTION INPUT ;
    USE SIGNAL ;
    PORT
      LAYER M4 ;
        RECT  0 53.52 0.084 53.544 ;
    END
  END d[274]
  PIN d[275]
    DIRECTION INPUT ;
    USE SIGNAL ;
    PORT
      LAYER M4 ;
        RECT  0 53.616 0.084 53.64 ;
    END
  END d[275]
  PIN d[276]
    DIRECTION INPUT ;
    USE SIGNAL ;
    PORT
      LAYER M4 ;
        RECT  0 53.712 0.084 53.736 ;
    END
  END d[276]
  PIN d[277]
    DIRECTION INPUT ;
    USE SIGNAL ;
    PORT
      LAYER M4 ;
        RECT  0 53.808 0.084 53.832 ;
    END
  END d[277]
  PIN d[278]
    DIRECTION INPUT ;
    USE SIGNAL ;
    PORT
      LAYER M4 ;
        RECT  0 53.904 0.084 53.928 ;
    END
  END d[278]
  PIN d[279]
    DIRECTION INPUT ;
    USE SIGNAL ;
    PORT
      LAYER M4 ;
        RECT  0 54 0.084 54.024 ;
    END
  END d[279]
  PIN d[27]
    DIRECTION INPUT ;
    USE SIGNAL ;
    PORT
      LAYER M4 ;
        RECT  0 29.04 0.084 29.064 ;
    END
  END d[27]
  PIN d[280]
    DIRECTION INPUT ;
    USE SIGNAL ;
    PORT
      LAYER M4 ;
        RECT  0 54.096 0.084 54.12 ;
    END
  END d[280]
  PIN d[281]
    DIRECTION INPUT ;
    USE SIGNAL ;
    PORT
      LAYER M4 ;
        RECT  0 54.192 0.084 54.216 ;
    END
  END d[281]
  PIN d[282]
    DIRECTION INPUT ;
    USE SIGNAL ;
    PORT
      LAYER M4 ;
        RECT  0 54.288 0.084 54.312 ;
    END
  END d[282]
  PIN d[283]
    DIRECTION INPUT ;
    USE SIGNAL ;
    PORT
      LAYER M4 ;
        RECT  0 54.384 0.084 54.408 ;
    END
  END d[283]
  PIN d[284]
    DIRECTION INPUT ;
    USE SIGNAL ;
    PORT
      LAYER M4 ;
        RECT  0 54.48 0.084 54.504 ;
    END
  END d[284]
  PIN d[285]
    DIRECTION INPUT ;
    USE SIGNAL ;
    PORT
      LAYER M4 ;
        RECT  0 54.576 0.084 54.6 ;
    END
  END d[285]
  PIN d[286]
    DIRECTION INPUT ;
    USE SIGNAL ;
    PORT
      LAYER M4 ;
        RECT  0 54.672 0.084 54.696 ;
    END
  END d[286]
  PIN d[287]
    DIRECTION INPUT ;
    USE SIGNAL ;
    PORT
      LAYER M4 ;
        RECT  0 54.768 0.084 54.792 ;
    END
  END d[287]
  PIN d[288]
    DIRECTION INPUT ;
    USE SIGNAL ;
    PORT
      LAYER M4 ;
        RECT  0 48.72 0.084 48.744 ;
    END
  END d[288]
  PIN d[289]
    DIRECTION INPUT ;
    USE SIGNAL ;
    PORT
      LAYER M4 ;
        RECT  0 48.816 0.084 48.84 ;
    END
  END d[289]
  PIN d[28]
    DIRECTION INPUT ;
    USE SIGNAL ;
    PORT
      LAYER M4 ;
        RECT  0 29.136 0.084 29.16 ;
    END
  END d[28]
  PIN d[290]
    DIRECTION INPUT ;
    USE SIGNAL ;
    PORT
      LAYER M4 ;
        RECT  0 48.912 0.084 48.936 ;
    END
  END d[290]
  PIN d[291]
    DIRECTION INPUT ;
    USE SIGNAL ;
    PORT
      LAYER M4 ;
        RECT  0 49.008 0.084 49.032 ;
    END
  END d[291]
  PIN d[292]
    DIRECTION INPUT ;
    USE SIGNAL ;
    PORT
      LAYER M4 ;
        RECT  0 49.104 0.084 49.128 ;
    END
  END d[292]
  PIN d[293]
    DIRECTION INPUT ;
    USE SIGNAL ;
    PORT
      LAYER M4 ;
        RECT  0 49.2 0.084 49.224 ;
    END
  END d[293]
  PIN d[294]
    DIRECTION INPUT ;
    USE SIGNAL ;
    PORT
      LAYER M4 ;
        RECT  0 49.296 0.084 49.32 ;
    END
  END d[294]
  PIN d[295]
    DIRECTION INPUT ;
    USE SIGNAL ;
    PORT
      LAYER M4 ;
        RECT  0 49.392 0.084 49.416 ;
    END
  END d[295]
  PIN d[296]
    DIRECTION INPUT ;
    USE SIGNAL ;
    PORT
      LAYER M4 ;
        RECT  0 49.488 0.084 49.512 ;
    END
  END d[296]
  PIN d[297]
    DIRECTION INPUT ;
    USE SIGNAL ;
    PORT
      LAYER M4 ;
        RECT  0 49.584 0.084 49.608 ;
    END
  END d[297]
  PIN d[298]
    DIRECTION INPUT ;
    USE SIGNAL ;
    PORT
      LAYER M4 ;
        RECT  0 49.68 0.084 49.704 ;
    END
  END d[298]
  PIN d[299]
    DIRECTION INPUT ;
    USE SIGNAL ;
    PORT
      LAYER M4 ;
        RECT  0 49.776 0.084 49.8 ;
    END
  END d[299]
  PIN d[29]
    DIRECTION INPUT ;
    USE SIGNAL ;
    PORT
      LAYER M4 ;
        RECT  0 29.232 0.084 29.256 ;
    END
  END d[29]
  PIN d[2]
    DIRECTION INPUT ;
    USE SIGNAL ;
    PORT
      LAYER M4 ;
        RECT  0 26.64 0.084 26.664 ;
    END
  END d[2]
  PIN d[300]
    DIRECTION INPUT ;
    USE SIGNAL ;
    PORT
      LAYER M4 ;
        RECT  0 49.872 0.084 49.896 ;
    END
  END d[300]
  PIN d[301]
    DIRECTION INPUT ;
    USE SIGNAL ;
    PORT
      LAYER M4 ;
        RECT  0 49.968 0.084 49.992 ;
    END
  END d[301]
  PIN d[302]
    DIRECTION INPUT ;
    USE SIGNAL ;
    PORT
      LAYER M4 ;
        RECT  0 50.064 0.084 50.088 ;
    END
  END d[302]
  PIN d[303]
    DIRECTION INPUT ;
    USE SIGNAL ;
    PORT
      LAYER M4 ;
        RECT  0 50.16 0.084 50.184 ;
    END
  END d[303]
  PIN d[304]
    DIRECTION INPUT ;
    USE SIGNAL ;
    PORT
      LAYER M4 ;
        RECT  0 50.256 0.084 50.28 ;
    END
  END d[304]
  PIN d[305]
    DIRECTION INPUT ;
    USE SIGNAL ;
    PORT
      LAYER M4 ;
        RECT  0 50.352 0.084 50.376 ;
    END
  END d[305]
  PIN d[306]
    DIRECTION INPUT ;
    USE SIGNAL ;
    PORT
      LAYER M4 ;
        RECT  0 50.448 0.084 50.472 ;
    END
  END d[306]
  PIN d[307]
    DIRECTION INPUT ;
    USE SIGNAL ;
    PORT
      LAYER M4 ;
        RECT  0 50.544 0.084 50.568 ;
    END
  END d[307]
  PIN d[308]
    DIRECTION INPUT ;
    USE SIGNAL ;
    PORT
      LAYER M4 ;
        RECT  0 50.64 0.084 50.664 ;
    END
  END d[308]
  PIN d[309]
    DIRECTION INPUT ;
    USE SIGNAL ;
    PORT
      LAYER M4 ;
        RECT  0 50.736 0.084 50.76 ;
    END
  END d[309]
  PIN d[30]
    DIRECTION INPUT ;
    USE SIGNAL ;
    PORT
      LAYER M4 ;
        RECT  0 29.328 0.084 29.352 ;
    END
  END d[30]
  PIN d[310]
    DIRECTION INPUT ;
    USE SIGNAL ;
    PORT
      LAYER M4 ;
        RECT  0 50.832 0.084 50.856 ;
    END
  END d[310]
  PIN d[311]
    DIRECTION INPUT ;
    USE SIGNAL ;
    PORT
      LAYER M4 ;
        RECT  0 50.928 0.084 50.952 ;
    END
  END d[311]
  PIN d[312]
    DIRECTION INPUT ;
    USE SIGNAL ;
    PORT
      LAYER M4 ;
        RECT  0 51.024 0.084 51.048 ;
    END
  END d[312]
  PIN d[313]
    DIRECTION INPUT ;
    USE SIGNAL ;
    PORT
      LAYER M4 ;
        RECT  0 51.12 0.084 51.144 ;
    END
  END d[313]
  PIN d[314]
    DIRECTION INPUT ;
    USE SIGNAL ;
    PORT
      LAYER M4 ;
        RECT  0 51.216 0.084 51.24 ;
    END
  END d[314]
  PIN d[315]
    DIRECTION INPUT ;
    USE SIGNAL ;
    PORT
      LAYER M4 ;
        RECT  0 51.312 0.084 51.336 ;
    END
  END d[315]
  PIN d[316]
    DIRECTION INPUT ;
    USE SIGNAL ;
    PORT
      LAYER M4 ;
        RECT  0 51.408 0.084 51.432 ;
    END
  END d[316]
  PIN d[317]
    DIRECTION INPUT ;
    USE SIGNAL ;
    PORT
      LAYER M4 ;
        RECT  0 51.504 0.084 51.528 ;
    END
  END d[317]
  PIN d[318]
    DIRECTION INPUT ;
    USE SIGNAL ;
    PORT
      LAYER M4 ;
        RECT  0 51.6 0.084 51.624 ;
    END
  END d[318]
  PIN d[319]
    DIRECTION INPUT ;
    USE SIGNAL ;
    PORT
      LAYER M4 ;
        RECT  0 51.696 0.084 51.72 ;
    END
  END d[319]
  PIN d[31]
    DIRECTION INPUT ;
    USE SIGNAL ;
    PORT
      LAYER M4 ;
        RECT  0 29.424 0.084 29.448 ;
    END
  END d[31]
  PIN d[320]
    DIRECTION INPUT ;
    USE SIGNAL ;
    PORT
      LAYER M4 ;
        RECT  0 22.608 0.084 22.632 ;
    END
  END d[320]
  PIN d[321]
    DIRECTION INPUT ;
    USE SIGNAL ;
    PORT
      LAYER M4 ;
        RECT  0 22.704 0.084 22.728 ;
    END
  END d[321]
  PIN d[322]
    DIRECTION INPUT ;
    USE SIGNAL ;
    PORT
      LAYER M4 ;
        RECT  0 22.8 0.084 22.824 ;
    END
  END d[322]
  PIN d[323]
    DIRECTION INPUT ;
    USE SIGNAL ;
    PORT
      LAYER M4 ;
        RECT  0 22.896 0.084 22.92 ;
    END
  END d[323]
  PIN d[324]
    DIRECTION INPUT ;
    USE SIGNAL ;
    PORT
      LAYER M4 ;
        RECT  0 22.992 0.084 23.016 ;
    END
  END d[324]
  PIN d[325]
    DIRECTION INPUT ;
    USE SIGNAL ;
    PORT
      LAYER M4 ;
        RECT  0 23.088 0.084 23.112 ;
    END
  END d[325]
  PIN d[326]
    DIRECTION INPUT ;
    USE SIGNAL ;
    PORT
      LAYER M4 ;
        RECT  0 23.184 0.084 23.208 ;
    END
  END d[326]
  PIN d[327]
    DIRECTION INPUT ;
    USE SIGNAL ;
    PORT
      LAYER M4 ;
        RECT  0 23.28 0.084 23.304 ;
    END
  END d[327]
  PIN d[328]
    DIRECTION INPUT ;
    USE SIGNAL ;
    PORT
      LAYER M4 ;
        RECT  0 23.376 0.084 23.4 ;
    END
  END d[328]
  PIN d[329]
    DIRECTION INPUT ;
    USE SIGNAL ;
    PORT
      LAYER M4 ;
        RECT  0 23.472 0.084 23.496 ;
    END
  END d[329]
  PIN d[32]
    DIRECTION INPUT ;
    USE SIGNAL ;
    PORT
      LAYER M4 ;
        RECT  0 32.592 0.084 32.616 ;
    END
  END d[32]
  PIN d[330]
    DIRECTION INPUT ;
    USE SIGNAL ;
    PORT
      LAYER M4 ;
        RECT  0 23.568 0.084 23.592 ;
    END
  END d[330]
  PIN d[331]
    DIRECTION INPUT ;
    USE SIGNAL ;
    PORT
      LAYER M4 ;
        RECT  0 23.664 0.084 23.688 ;
    END
  END d[331]
  PIN d[332]
    DIRECTION INPUT ;
    USE SIGNAL ;
    PORT
      LAYER M4 ;
        RECT  0 23.76 0.084 23.784 ;
    END
  END d[332]
  PIN d[333]
    DIRECTION INPUT ;
    USE SIGNAL ;
    PORT
      LAYER M4 ;
        RECT  0 23.856 0.084 23.88 ;
    END
  END d[333]
  PIN d[334]
    DIRECTION INPUT ;
    USE SIGNAL ;
    PORT
      LAYER M4 ;
        RECT  0 23.952 0.084 23.976 ;
    END
  END d[334]
  PIN d[335]
    DIRECTION INPUT ;
    USE SIGNAL ;
    PORT
      LAYER M4 ;
        RECT  0 24.048 0.084 24.072 ;
    END
  END d[335]
  PIN d[336]
    DIRECTION INPUT ;
    USE SIGNAL ;
    PORT
      LAYER M4 ;
        RECT  0 24.144 0.084 24.168 ;
    END
  END d[336]
  PIN d[337]
    DIRECTION INPUT ;
    USE SIGNAL ;
    PORT
      LAYER M4 ;
        RECT  0 24.24 0.084 24.264 ;
    END
  END d[337]
  PIN d[338]
    DIRECTION INPUT ;
    USE SIGNAL ;
    PORT
      LAYER M4 ;
        RECT  0 24.336 0.084 24.36 ;
    END
  END d[338]
  PIN d[339]
    DIRECTION INPUT ;
    USE SIGNAL ;
    PORT
      LAYER M4 ;
        RECT  0 24.432 0.084 24.456 ;
    END
  END d[339]
  PIN d[33]
    DIRECTION INPUT ;
    USE SIGNAL ;
    PORT
      LAYER M4 ;
        RECT  0 32.688 0.084 32.712 ;
    END
  END d[33]
  PIN d[340]
    DIRECTION INPUT ;
    USE SIGNAL ;
    PORT
      LAYER M4 ;
        RECT  0 24.528 0.084 24.552 ;
    END
  END d[340]
  PIN d[341]
    DIRECTION INPUT ;
    USE SIGNAL ;
    PORT
      LAYER M4 ;
        RECT  0 24.624 0.084 24.648 ;
    END
  END d[341]
  PIN d[342]
    DIRECTION INPUT ;
    USE SIGNAL ;
    PORT
      LAYER M4 ;
        RECT  0 24.72 0.084 24.744 ;
    END
  END d[342]
  PIN d[343]
    DIRECTION INPUT ;
    USE SIGNAL ;
    PORT
      LAYER M4 ;
        RECT  0 24.816 0.084 24.84 ;
    END
  END d[343]
  PIN d[344]
    DIRECTION INPUT ;
    USE SIGNAL ;
    PORT
      LAYER M4 ;
        RECT  0 24.912 0.084 24.936 ;
    END
  END d[344]
  PIN d[345]
    DIRECTION INPUT ;
    USE SIGNAL ;
    PORT
      LAYER M4 ;
        RECT  0 25.008 0.084 25.032 ;
    END
  END d[345]
  PIN d[346]
    DIRECTION INPUT ;
    USE SIGNAL ;
    PORT
      LAYER M4 ;
        RECT  0 25.104 0.084 25.128 ;
    END
  END d[346]
  PIN d[347]
    DIRECTION INPUT ;
    USE SIGNAL ;
    PORT
      LAYER M4 ;
        RECT  0 25.2 0.084 25.224 ;
    END
  END d[347]
  PIN d[348]
    DIRECTION INPUT ;
    USE SIGNAL ;
    PORT
      LAYER M4 ;
        RECT  0 25.296 0.084 25.32 ;
    END
  END d[348]
  PIN d[349]
    DIRECTION INPUT ;
    USE SIGNAL ;
    PORT
      LAYER M4 ;
        RECT  0 25.392 0.084 25.416 ;
    END
  END d[349]
  PIN d[34]
    DIRECTION INPUT ;
    USE SIGNAL ;
    PORT
      LAYER M4 ;
        RECT  0 32.784 0.084 32.808 ;
    END
  END d[34]
  PIN d[350]
    DIRECTION INPUT ;
    USE SIGNAL ;
    PORT
      LAYER M4 ;
        RECT  0 25.488 0.084 25.512 ;
    END
  END d[350]
  PIN d[351]
    DIRECTION INPUT ;
    USE SIGNAL ;
    PORT
      LAYER M4 ;
        RECT  0 25.584 0.084 25.608 ;
    END
  END d[351]
  PIN d[352]
    DIRECTION INPUT ;
    USE SIGNAL ;
    PORT
      LAYER M4 ;
        RECT  0 19.536 0.084 19.56 ;
    END
  END d[352]
  PIN d[353]
    DIRECTION INPUT ;
    USE SIGNAL ;
    PORT
      LAYER M4 ;
        RECT  0 19.632 0.084 19.656 ;
    END
  END d[353]
  PIN d[354]
    DIRECTION INPUT ;
    USE SIGNAL ;
    PORT
      LAYER M4 ;
        RECT  0 19.728 0.084 19.752 ;
    END
  END d[354]
  PIN d[355]
    DIRECTION INPUT ;
    USE SIGNAL ;
    PORT
      LAYER M4 ;
        RECT  0 19.824 0.084 19.848 ;
    END
  END d[355]
  PIN d[356]
    DIRECTION INPUT ;
    USE SIGNAL ;
    PORT
      LAYER M4 ;
        RECT  0 19.92 0.084 19.944 ;
    END
  END d[356]
  PIN d[357]
    DIRECTION INPUT ;
    USE SIGNAL ;
    PORT
      LAYER M4 ;
        RECT  0 20.016 0.084 20.04 ;
    END
  END d[357]
  PIN d[358]
    DIRECTION INPUT ;
    USE SIGNAL ;
    PORT
      LAYER M4 ;
        RECT  0 20.112 0.084 20.136 ;
    END
  END d[358]
  PIN d[359]
    DIRECTION INPUT ;
    USE SIGNAL ;
    PORT
      LAYER M4 ;
        RECT  0 20.208 0.084 20.232 ;
    END
  END d[359]
  PIN d[35]
    DIRECTION INPUT ;
    USE SIGNAL ;
    PORT
      LAYER M4 ;
        RECT  0 32.88 0.084 32.904 ;
    END
  END d[35]
  PIN d[360]
    DIRECTION INPUT ;
    USE SIGNAL ;
    PORT
      LAYER M4 ;
        RECT  0 20.304 0.084 20.328 ;
    END
  END d[360]
  PIN d[361]
    DIRECTION INPUT ;
    USE SIGNAL ;
    PORT
      LAYER M4 ;
        RECT  0 20.4 0.084 20.424 ;
    END
  END d[361]
  PIN d[362]
    DIRECTION INPUT ;
    USE SIGNAL ;
    PORT
      LAYER M4 ;
        RECT  0 20.496 0.084 20.52 ;
    END
  END d[362]
  PIN d[363]
    DIRECTION INPUT ;
    USE SIGNAL ;
    PORT
      LAYER M4 ;
        RECT  0 20.592 0.084 20.616 ;
    END
  END d[363]
  PIN d[364]
    DIRECTION INPUT ;
    USE SIGNAL ;
    PORT
      LAYER M4 ;
        RECT  0 20.688 0.084 20.712 ;
    END
  END d[364]
  PIN d[365]
    DIRECTION INPUT ;
    USE SIGNAL ;
    PORT
      LAYER M4 ;
        RECT  0 20.784 0.084 20.808 ;
    END
  END d[365]
  PIN d[366]
    DIRECTION INPUT ;
    USE SIGNAL ;
    PORT
      LAYER M4 ;
        RECT  0 20.88 0.084 20.904 ;
    END
  END d[366]
  PIN d[367]
    DIRECTION INPUT ;
    USE SIGNAL ;
    PORT
      LAYER M4 ;
        RECT  0 20.976 0.084 21 ;
    END
  END d[367]
  PIN d[368]
    DIRECTION INPUT ;
    USE SIGNAL ;
    PORT
      LAYER M4 ;
        RECT  0 21.072 0.084 21.096 ;
    END
  END d[368]
  PIN d[369]
    DIRECTION INPUT ;
    USE SIGNAL ;
    PORT
      LAYER M4 ;
        RECT  0 21.168 0.084 21.192 ;
    END
  END d[369]
  PIN d[36]
    DIRECTION INPUT ;
    USE SIGNAL ;
    PORT
      LAYER M4 ;
        RECT  0 32.976 0.084 33 ;
    END
  END d[36]
  PIN d[370]
    DIRECTION INPUT ;
    USE SIGNAL ;
    PORT
      LAYER M4 ;
        RECT  0 21.264 0.084 21.288 ;
    END
  END d[370]
  PIN d[371]
    DIRECTION INPUT ;
    USE SIGNAL ;
    PORT
      LAYER M4 ;
        RECT  0 21.36 0.084 21.384 ;
    END
  END d[371]
  PIN d[372]
    DIRECTION INPUT ;
    USE SIGNAL ;
    PORT
      LAYER M4 ;
        RECT  0 21.456 0.084 21.48 ;
    END
  END d[372]
  PIN d[373]
    DIRECTION INPUT ;
    USE SIGNAL ;
    PORT
      LAYER M4 ;
        RECT  0 21.552 0.084 21.576 ;
    END
  END d[373]
  PIN d[374]
    DIRECTION INPUT ;
    USE SIGNAL ;
    PORT
      LAYER M4 ;
        RECT  0 21.648 0.084 21.672 ;
    END
  END d[374]
  PIN d[375]
    DIRECTION INPUT ;
    USE SIGNAL ;
    PORT
      LAYER M4 ;
        RECT  0 21.744 0.084 21.768 ;
    END
  END d[375]
  PIN d[376]
    DIRECTION INPUT ;
    USE SIGNAL ;
    PORT
      LAYER M4 ;
        RECT  0 21.84 0.084 21.864 ;
    END
  END d[376]
  PIN d[377]
    DIRECTION INPUT ;
    USE SIGNAL ;
    PORT
      LAYER M4 ;
        RECT  0 21.936 0.084 21.96 ;
    END
  END d[377]
  PIN d[378]
    DIRECTION INPUT ;
    USE SIGNAL ;
    PORT
      LAYER M4 ;
        RECT  0 22.032 0.084 22.056 ;
    END
  END d[378]
  PIN d[379]
    DIRECTION INPUT ;
    USE SIGNAL ;
    PORT
      LAYER M4 ;
        RECT  0 22.128 0.084 22.152 ;
    END
  END d[379]
  PIN d[37]
    DIRECTION INPUT ;
    USE SIGNAL ;
    PORT
      LAYER M4 ;
        RECT  0 33.072 0.084 33.096 ;
    END
  END d[37]
  PIN d[380]
    DIRECTION INPUT ;
    USE SIGNAL ;
    PORT
      LAYER M4 ;
        RECT  0 22.224 0.084 22.248 ;
    END
  END d[380]
  PIN d[381]
    DIRECTION INPUT ;
    USE SIGNAL ;
    PORT
      LAYER M4 ;
        RECT  0 22.32 0.084 22.344 ;
    END
  END d[381]
  PIN d[382]
    DIRECTION INPUT ;
    USE SIGNAL ;
    PORT
      LAYER M4 ;
        RECT  0 22.416 0.084 22.44 ;
    END
  END d[382]
  PIN d[383]
    DIRECTION INPUT ;
    USE SIGNAL ;
    PORT
      LAYER M4 ;
        RECT  0 22.512 0.084 22.536 ;
    END
  END d[383]
  PIN d[384]
    DIRECTION INPUT ;
    USE SIGNAL ;
    PORT
      LAYER M4 ;
        RECT  0 10.32 0.084 10.344 ;
    END
  END d[384]
  PIN d[385]
    DIRECTION INPUT ;
    USE SIGNAL ;
    PORT
      LAYER M4 ;
        RECT  0 10.416 0.084 10.44 ;
    END
  END d[385]
  PIN d[386]
    DIRECTION INPUT ;
    USE SIGNAL ;
    PORT
      LAYER M4 ;
        RECT  0 10.512 0.084 10.536 ;
    END
  END d[386]
  PIN d[387]
    DIRECTION INPUT ;
    USE SIGNAL ;
    PORT
      LAYER M4 ;
        RECT  0 10.608 0.084 10.632 ;
    END
  END d[387]
  PIN d[388]
    DIRECTION INPUT ;
    USE SIGNAL ;
    PORT
      LAYER M4 ;
        RECT  0 10.704 0.084 10.728 ;
    END
  END d[388]
  PIN d[389]
    DIRECTION INPUT ;
    USE SIGNAL ;
    PORT
      LAYER M4 ;
        RECT  0 10.8 0.084 10.824 ;
    END
  END d[389]
  PIN d[38]
    DIRECTION INPUT ;
    USE SIGNAL ;
    PORT
      LAYER M4 ;
        RECT  0 33.168 0.084 33.192 ;
    END
  END d[38]
  PIN d[390]
    DIRECTION INPUT ;
    USE SIGNAL ;
    PORT
      LAYER M4 ;
        RECT  0 10.896 0.084 10.92 ;
    END
  END d[390]
  PIN d[391]
    DIRECTION INPUT ;
    USE SIGNAL ;
    PORT
      LAYER M4 ;
        RECT  0 10.992 0.084 11.016 ;
    END
  END d[391]
  PIN d[392]
    DIRECTION INPUT ;
    USE SIGNAL ;
    PORT
      LAYER M4 ;
        RECT  0 11.088 0.084 11.112 ;
    END
  END d[392]
  PIN d[393]
    DIRECTION INPUT ;
    USE SIGNAL ;
    PORT
      LAYER M4 ;
        RECT  0 11.184 0.084 11.208 ;
    END
  END d[393]
  PIN d[394]
    DIRECTION INPUT ;
    USE SIGNAL ;
    PORT
      LAYER M4 ;
        RECT  0 11.28 0.084 11.304 ;
    END
  END d[394]
  PIN d[395]
    DIRECTION INPUT ;
    USE SIGNAL ;
    PORT
      LAYER M4 ;
        RECT  0 11.376 0.084 11.4 ;
    END
  END d[395]
  PIN d[396]
    DIRECTION INPUT ;
    USE SIGNAL ;
    PORT
      LAYER M4 ;
        RECT  0 11.472 0.084 11.496 ;
    END
  END d[396]
  PIN d[397]
    DIRECTION INPUT ;
    USE SIGNAL ;
    PORT
      LAYER M4 ;
        RECT  0 11.568 0.084 11.592 ;
    END
  END d[397]
  PIN d[398]
    DIRECTION INPUT ;
    USE SIGNAL ;
    PORT
      LAYER M4 ;
        RECT  0 11.664 0.084 11.688 ;
    END
  END d[398]
  PIN d[399]
    DIRECTION INPUT ;
    USE SIGNAL ;
    PORT
      LAYER M4 ;
        RECT  0 11.76 0.084 11.784 ;
    END
  END d[399]
  PIN d[39]
    DIRECTION INPUT ;
    USE SIGNAL ;
    PORT
      LAYER M4 ;
        RECT  0 33.264 0.084 33.288 ;
    END
  END d[39]
  PIN d[3]
    DIRECTION INPUT ;
    USE SIGNAL ;
    PORT
      LAYER M4 ;
        RECT  0 26.736 0.084 26.76 ;
    END
  END d[3]
  PIN d[400]
    DIRECTION INPUT ;
    USE SIGNAL ;
    PORT
      LAYER M4 ;
        RECT  0 11.856 0.084 11.88 ;
    END
  END d[400]
  PIN d[401]
    DIRECTION INPUT ;
    USE SIGNAL ;
    PORT
      LAYER M4 ;
        RECT  0 11.952 0.084 11.976 ;
    END
  END d[401]
  PIN d[402]
    DIRECTION INPUT ;
    USE SIGNAL ;
    PORT
      LAYER M4 ;
        RECT  0 12.048 0.084 12.072 ;
    END
  END d[402]
  PIN d[403]
    DIRECTION INPUT ;
    USE SIGNAL ;
    PORT
      LAYER M4 ;
        RECT  0 12.144 0.084 12.168 ;
    END
  END d[403]
  PIN d[404]
    DIRECTION INPUT ;
    USE SIGNAL ;
    PORT
      LAYER M4 ;
        RECT  0 12.24 0.084 12.264 ;
    END
  END d[404]
  PIN d[405]
    DIRECTION INPUT ;
    USE SIGNAL ;
    PORT
      LAYER M4 ;
        RECT  0 12.336 0.084 12.36 ;
    END
  END d[405]
  PIN d[406]
    DIRECTION INPUT ;
    USE SIGNAL ;
    PORT
      LAYER M4 ;
        RECT  0 12.432 0.084 12.456 ;
    END
  END d[406]
  PIN d[407]
    DIRECTION INPUT ;
    USE SIGNAL ;
    PORT
      LAYER M4 ;
        RECT  0 12.528 0.084 12.552 ;
    END
  END d[407]
  PIN d[408]
    DIRECTION INPUT ;
    USE SIGNAL ;
    PORT
      LAYER M4 ;
        RECT  0 12.624 0.084 12.648 ;
    END
  END d[408]
  PIN d[409]
    DIRECTION INPUT ;
    USE SIGNAL ;
    PORT
      LAYER M4 ;
        RECT  0 12.72 0.084 12.744 ;
    END
  END d[409]
  PIN d[40]
    DIRECTION INPUT ;
    USE SIGNAL ;
    PORT
      LAYER M4 ;
        RECT  0 33.36 0.084 33.384 ;
    END
  END d[40]
  PIN d[410]
    DIRECTION INPUT ;
    USE SIGNAL ;
    PORT
      LAYER M4 ;
        RECT  0 12.816 0.084 12.84 ;
    END
  END d[410]
  PIN d[411]
    DIRECTION INPUT ;
    USE SIGNAL ;
    PORT
      LAYER M4 ;
        RECT  0 12.912 0.084 12.936 ;
    END
  END d[411]
  PIN d[412]
    DIRECTION INPUT ;
    USE SIGNAL ;
    PORT
      LAYER M4 ;
        RECT  0 13.008 0.084 13.032 ;
    END
  END d[412]
  PIN d[413]
    DIRECTION INPUT ;
    USE SIGNAL ;
    PORT
      LAYER M4 ;
        RECT  0 13.104 0.084 13.128 ;
    END
  END d[413]
  PIN d[414]
    DIRECTION INPUT ;
    USE SIGNAL ;
    PORT
      LAYER M4 ;
        RECT  0 13.2 0.084 13.224 ;
    END
  END d[414]
  PIN d[415]
    DIRECTION INPUT ;
    USE SIGNAL ;
    PORT
      LAYER M4 ;
        RECT  0 13.296 0.084 13.32 ;
    END
  END d[415]
  PIN d[416]
    DIRECTION INPUT ;
    USE SIGNAL ;
    PORT
      LAYER M4 ;
        RECT  0 16.464 0.084 16.488 ;
    END
  END d[416]
  PIN d[417]
    DIRECTION INPUT ;
    USE SIGNAL ;
    PORT
      LAYER M4 ;
        RECT  0 16.56 0.084 16.584 ;
    END
  END d[417]
  PIN d[418]
    DIRECTION INPUT ;
    USE SIGNAL ;
    PORT
      LAYER M4 ;
        RECT  0 16.656 0.084 16.68 ;
    END
  END d[418]
  PIN d[419]
    DIRECTION INPUT ;
    USE SIGNAL ;
    PORT
      LAYER M4 ;
        RECT  0 16.752 0.084 16.776 ;
    END
  END d[419]
  PIN d[41]
    DIRECTION INPUT ;
    USE SIGNAL ;
    PORT
      LAYER M4 ;
        RECT  0 33.456 0.084 33.48 ;
    END
  END d[41]
  PIN d[420]
    DIRECTION INPUT ;
    USE SIGNAL ;
    PORT
      LAYER M4 ;
        RECT  0 16.848 0.084 16.872 ;
    END
  END d[420]
  PIN d[421]
    DIRECTION INPUT ;
    USE SIGNAL ;
    PORT
      LAYER M4 ;
        RECT  0 16.944 0.084 16.968 ;
    END
  END d[421]
  PIN d[422]
    DIRECTION INPUT ;
    USE SIGNAL ;
    PORT
      LAYER M4 ;
        RECT  0 17.04 0.084 17.064 ;
    END
  END d[422]
  PIN d[423]
    DIRECTION INPUT ;
    USE SIGNAL ;
    PORT
      LAYER M4 ;
        RECT  0 17.136 0.084 17.16 ;
    END
  END d[423]
  PIN d[424]
    DIRECTION INPUT ;
    USE SIGNAL ;
    PORT
      LAYER M4 ;
        RECT  0 17.232 0.084 17.256 ;
    END
  END d[424]
  PIN d[425]
    DIRECTION INPUT ;
    USE SIGNAL ;
    PORT
      LAYER M4 ;
        RECT  0 17.328 0.084 17.352 ;
    END
  END d[425]
  PIN d[426]
    DIRECTION INPUT ;
    USE SIGNAL ;
    PORT
      LAYER M4 ;
        RECT  0 17.424 0.084 17.448 ;
    END
  END d[426]
  PIN d[427]
    DIRECTION INPUT ;
    USE SIGNAL ;
    PORT
      LAYER M4 ;
        RECT  0 17.52 0.084 17.544 ;
    END
  END d[427]
  PIN d[428]
    DIRECTION INPUT ;
    USE SIGNAL ;
    PORT
      LAYER M4 ;
        RECT  0 17.616 0.084 17.64 ;
    END
  END d[428]
  PIN d[429]
    DIRECTION INPUT ;
    USE SIGNAL ;
    PORT
      LAYER M4 ;
        RECT  0 17.712 0.084 17.736 ;
    END
  END d[429]
  PIN d[42]
    DIRECTION INPUT ;
    USE SIGNAL ;
    PORT
      LAYER M4 ;
        RECT  0 33.552 0.084 33.576 ;
    END
  END d[42]
  PIN d[430]
    DIRECTION INPUT ;
    USE SIGNAL ;
    PORT
      LAYER M4 ;
        RECT  0 17.808 0.084 17.832 ;
    END
  END d[430]
  PIN d[431]
    DIRECTION INPUT ;
    USE SIGNAL ;
    PORT
      LAYER M4 ;
        RECT  0 17.904 0.084 17.928 ;
    END
  END d[431]
  PIN d[432]
    DIRECTION INPUT ;
    USE SIGNAL ;
    PORT
      LAYER M4 ;
        RECT  0 18 0.084 18.024 ;
    END
  END d[432]
  PIN d[433]
    DIRECTION INPUT ;
    USE SIGNAL ;
    PORT
      LAYER M4 ;
        RECT  0 18.096 0.084 18.12 ;
    END
  END d[433]
  PIN d[434]
    DIRECTION INPUT ;
    USE SIGNAL ;
    PORT
      LAYER M4 ;
        RECT  0 18.192 0.084 18.216 ;
    END
  END d[434]
  PIN d[435]
    DIRECTION INPUT ;
    USE SIGNAL ;
    PORT
      LAYER M4 ;
        RECT  0 18.288 0.084 18.312 ;
    END
  END d[435]
  PIN d[436]
    DIRECTION INPUT ;
    USE SIGNAL ;
    PORT
      LAYER M4 ;
        RECT  0 18.384 0.084 18.408 ;
    END
  END d[436]
  PIN d[437]
    DIRECTION INPUT ;
    USE SIGNAL ;
    PORT
      LAYER M4 ;
        RECT  0 18.48 0.084 18.504 ;
    END
  END d[437]
  PIN d[438]
    DIRECTION INPUT ;
    USE SIGNAL ;
    PORT
      LAYER M4 ;
        RECT  0 18.576 0.084 18.6 ;
    END
  END d[438]
  PIN d[439]
    DIRECTION INPUT ;
    USE SIGNAL ;
    PORT
      LAYER M4 ;
        RECT  0 18.672 0.084 18.696 ;
    END
  END d[439]
  PIN d[43]
    DIRECTION INPUT ;
    USE SIGNAL ;
    PORT
      LAYER M4 ;
        RECT  0 33.648 0.084 33.672 ;
    END
  END d[43]
  PIN d[440]
    DIRECTION INPUT ;
    USE SIGNAL ;
    PORT
      LAYER M4 ;
        RECT  0 18.768 0.084 18.792 ;
    END
  END d[440]
  PIN d[441]
    DIRECTION INPUT ;
    USE SIGNAL ;
    PORT
      LAYER M4 ;
        RECT  0 18.864 0.084 18.888 ;
    END
  END d[441]
  PIN d[442]
    DIRECTION INPUT ;
    USE SIGNAL ;
    PORT
      LAYER M4 ;
        RECT  0 18.96 0.084 18.984 ;
    END
  END d[442]
  PIN d[443]
    DIRECTION INPUT ;
    USE SIGNAL ;
    PORT
      LAYER M4 ;
        RECT  0 19.056 0.084 19.08 ;
    END
  END d[443]
  PIN d[444]
    DIRECTION INPUT ;
    USE SIGNAL ;
    PORT
      LAYER M4 ;
        RECT  0 19.152 0.084 19.176 ;
    END
  END d[444]
  PIN d[445]
    DIRECTION INPUT ;
    USE SIGNAL ;
    PORT
      LAYER M4 ;
        RECT  0 19.248 0.084 19.272 ;
    END
  END d[445]
  PIN d[446]
    DIRECTION INPUT ;
    USE SIGNAL ;
    PORT
      LAYER M4 ;
        RECT  0 19.344 0.084 19.368 ;
    END
  END d[446]
  PIN d[447]
    DIRECTION INPUT ;
    USE SIGNAL ;
    PORT
      LAYER M4 ;
        RECT  0 19.44 0.084 19.464 ;
    END
  END d[447]
  PIN d[448]
    DIRECTION INPUT ;
    USE SIGNAL ;
    PORT
      LAYER M4 ;
        RECT  0 3.408 0.084 3.432 ;
    END
  END d[448]
  PIN d[449]
    DIRECTION INPUT ;
    USE SIGNAL ;
    PORT
      LAYER M4 ;
        RECT  0 3.504 0.084 3.528 ;
    END
  END d[449]
  PIN d[44]
    DIRECTION INPUT ;
    USE SIGNAL ;
    PORT
      LAYER M4 ;
        RECT  0 33.744 0.084 33.768 ;
    END
  END d[44]
  PIN d[450]
    DIRECTION INPUT ;
    USE SIGNAL ;
    PORT
      LAYER M4 ;
        RECT  0 3.6 0.084 3.624 ;
    END
  END d[450]
  PIN d[451]
    DIRECTION INPUT ;
    USE SIGNAL ;
    PORT
      LAYER M4 ;
        RECT  0 3.696 0.084 3.72 ;
    END
  END d[451]
  PIN d[452]
    DIRECTION INPUT ;
    USE SIGNAL ;
    PORT
      LAYER M4 ;
        RECT  0 3.792 0.084 3.816 ;
    END
  END d[452]
  PIN d[453]
    DIRECTION INPUT ;
    USE SIGNAL ;
    PORT
      LAYER M4 ;
        RECT  0 3.888 0.084 3.912 ;
    END
  END d[453]
  PIN d[454]
    DIRECTION INPUT ;
    USE SIGNAL ;
    PORT
      LAYER M4 ;
        RECT  0 3.984 0.084 4.008 ;
    END
  END d[454]
  PIN d[455]
    DIRECTION INPUT ;
    USE SIGNAL ;
    PORT
      LAYER M4 ;
        RECT  0 4.08 0.084 4.104 ;
    END
  END d[455]
  PIN d[456]
    DIRECTION INPUT ;
    USE SIGNAL ;
    PORT
      LAYER M4 ;
        RECT  0 4.176 0.084 4.2 ;
    END
  END d[456]
  PIN d[457]
    DIRECTION INPUT ;
    USE SIGNAL ;
    PORT
      LAYER M4 ;
        RECT  0 4.272 0.084 4.296 ;
    END
  END d[457]
  PIN d[458]
    DIRECTION INPUT ;
    USE SIGNAL ;
    PORT
      LAYER M4 ;
        RECT  0 4.368 0.084 4.392 ;
    END
  END d[458]
  PIN d[459]
    DIRECTION INPUT ;
    USE SIGNAL ;
    PORT
      LAYER M4 ;
        RECT  0 4.464 0.084 4.488 ;
    END
  END d[459]
  PIN d[45]
    DIRECTION INPUT ;
    USE SIGNAL ;
    PORT
      LAYER M4 ;
        RECT  0 33.84 0.084 33.864 ;
    END
  END d[45]
  PIN d[460]
    DIRECTION INPUT ;
    USE SIGNAL ;
    PORT
      LAYER M4 ;
        RECT  0 4.56 0.084 4.584 ;
    END
  END d[460]
  PIN d[461]
    DIRECTION INPUT ;
    USE SIGNAL ;
    PORT
      LAYER M4 ;
        RECT  0 4.656 0.084 4.68 ;
    END
  END d[461]
  PIN d[462]
    DIRECTION INPUT ;
    USE SIGNAL ;
    PORT
      LAYER M4 ;
        RECT  0 4.752 0.084 4.776 ;
    END
  END d[462]
  PIN d[463]
    DIRECTION INPUT ;
    USE SIGNAL ;
    PORT
      LAYER M4 ;
        RECT  0 4.848 0.084 4.872 ;
    END
  END d[463]
  PIN d[464]
    DIRECTION INPUT ;
    USE SIGNAL ;
    PORT
      LAYER M4 ;
        RECT  0 4.944 0.084 4.968 ;
    END
  END d[464]
  PIN d[465]
    DIRECTION INPUT ;
    USE SIGNAL ;
    PORT
      LAYER M4 ;
        RECT  0 5.04 0.084 5.064 ;
    END
  END d[465]
  PIN d[466]
    DIRECTION INPUT ;
    USE SIGNAL ;
    PORT
      LAYER M4 ;
        RECT  0 5.136 0.084 5.16 ;
    END
  END d[466]
  PIN d[467]
    DIRECTION INPUT ;
    USE SIGNAL ;
    PORT
      LAYER M4 ;
        RECT  0 5.232 0.084 5.256 ;
    END
  END d[467]
  PIN d[468]
    DIRECTION INPUT ;
    USE SIGNAL ;
    PORT
      LAYER M4 ;
        RECT  0 5.328 0.084 5.352 ;
    END
  END d[468]
  PIN d[469]
    DIRECTION INPUT ;
    USE SIGNAL ;
    PORT
      LAYER M4 ;
        RECT  0 5.424 0.084 5.448 ;
    END
  END d[469]
  PIN d[46]
    DIRECTION INPUT ;
    USE SIGNAL ;
    PORT
      LAYER M4 ;
        RECT  0 33.936 0.084 33.96 ;
    END
  END d[46]
  PIN d[470]
    DIRECTION INPUT ;
    USE SIGNAL ;
    PORT
      LAYER M4 ;
        RECT  0 5.52 0.084 5.544 ;
    END
  END d[470]
  PIN d[471]
    DIRECTION INPUT ;
    USE SIGNAL ;
    PORT
      LAYER M4 ;
        RECT  0 5.616 0.084 5.64 ;
    END
  END d[471]
  PIN d[472]
    DIRECTION INPUT ;
    USE SIGNAL ;
    PORT
      LAYER M4 ;
        RECT  0 5.712 0.084 5.736 ;
    END
  END d[472]
  PIN d[473]
    DIRECTION INPUT ;
    USE SIGNAL ;
    PORT
      LAYER M4 ;
        RECT  0 5.808 0.084 5.832 ;
    END
  END d[473]
  PIN d[474]
    DIRECTION INPUT ;
    USE SIGNAL ;
    PORT
      LAYER M4 ;
        RECT  0 5.904 0.084 5.928 ;
    END
  END d[474]
  PIN d[475]
    DIRECTION INPUT ;
    USE SIGNAL ;
    PORT
      LAYER M4 ;
        RECT  0 6 0.084 6.024 ;
    END
  END d[475]
  PIN d[476]
    DIRECTION INPUT ;
    USE SIGNAL ;
    PORT
      LAYER M4 ;
        RECT  0 6.096 0.084 6.12 ;
    END
  END d[476]
  PIN d[477]
    DIRECTION INPUT ;
    USE SIGNAL ;
    PORT
      LAYER M4 ;
        RECT  0 6.192 0.084 6.216 ;
    END
  END d[477]
  PIN d[478]
    DIRECTION INPUT ;
    USE SIGNAL ;
    PORT
      LAYER M4 ;
        RECT  0 6.288 0.084 6.312 ;
    END
  END d[478]
  PIN d[479]
    DIRECTION INPUT ;
    USE SIGNAL ;
    PORT
      LAYER M4 ;
        RECT  0 6.384 0.084 6.408 ;
    END
  END d[479]
  PIN d[47]
    DIRECTION INPUT ;
    USE SIGNAL ;
    PORT
      LAYER M4 ;
        RECT  0 34.032 0.084 34.056 ;
    END
  END d[47]
  PIN d[480]
    DIRECTION INPUT ;
    USE SIGNAL ;
    PORT
      LAYER M4 ;
        RECT  0 45.648 0.084 45.672 ;
    END
  END d[480]
  PIN d[481]
    DIRECTION INPUT ;
    USE SIGNAL ;
    PORT
      LAYER M4 ;
        RECT  0 45.744 0.084 45.768 ;
    END
  END d[481]
  PIN d[482]
    DIRECTION INPUT ;
    USE SIGNAL ;
    PORT
      LAYER M4 ;
        RECT  0 45.84 0.084 45.864 ;
    END
  END d[482]
  PIN d[483]
    DIRECTION INPUT ;
    USE SIGNAL ;
    PORT
      LAYER M4 ;
        RECT  0 45.936 0.084 45.96 ;
    END
  END d[483]
  PIN d[484]
    DIRECTION INPUT ;
    USE SIGNAL ;
    PORT
      LAYER M4 ;
        RECT  0 46.032 0.084 46.056 ;
    END
  END d[484]
  PIN d[485]
    DIRECTION INPUT ;
    USE SIGNAL ;
    PORT
      LAYER M4 ;
        RECT  0 46.128 0.084 46.152 ;
    END
  END d[485]
  PIN d[486]
    DIRECTION INPUT ;
    USE SIGNAL ;
    PORT
      LAYER M4 ;
        RECT  0 46.224 0.084 46.248 ;
    END
  END d[486]
  PIN d[487]
    DIRECTION INPUT ;
    USE SIGNAL ;
    PORT
      LAYER M4 ;
        RECT  0 46.32 0.084 46.344 ;
    END
  END d[487]
  PIN d[488]
    DIRECTION INPUT ;
    USE SIGNAL ;
    PORT
      LAYER M4 ;
        RECT  0 46.416 0.084 46.44 ;
    END
  END d[488]
  PIN d[489]
    DIRECTION INPUT ;
    USE SIGNAL ;
    PORT
      LAYER M4 ;
        RECT  0 46.512 0.084 46.536 ;
    END
  END d[489]
  PIN d[48]
    DIRECTION INPUT ;
    USE SIGNAL ;
    PORT
      LAYER M4 ;
        RECT  0 34.128 0.084 34.152 ;
    END
  END d[48]
  PIN d[490]
    DIRECTION INPUT ;
    USE SIGNAL ;
    PORT
      LAYER M4 ;
        RECT  0 46.608 0.084 46.632 ;
    END
  END d[490]
  PIN d[491]
    DIRECTION INPUT ;
    USE SIGNAL ;
    PORT
      LAYER M4 ;
        RECT  0 46.704 0.084 46.728 ;
    END
  END d[491]
  PIN d[492]
    DIRECTION INPUT ;
    USE SIGNAL ;
    PORT
      LAYER M4 ;
        RECT  0 46.8 0.084 46.824 ;
    END
  END d[492]
  PIN d[493]
    DIRECTION INPUT ;
    USE SIGNAL ;
    PORT
      LAYER M4 ;
        RECT  0 46.896 0.084 46.92 ;
    END
  END d[493]
  PIN d[494]
    DIRECTION INPUT ;
    USE SIGNAL ;
    PORT
      LAYER M4 ;
        RECT  0 46.992 0.084 47.016 ;
    END
  END d[494]
  PIN d[495]
    DIRECTION INPUT ;
    USE SIGNAL ;
    PORT
      LAYER M4 ;
        RECT  0 47.088 0.084 47.112 ;
    END
  END d[495]
  PIN d[496]
    DIRECTION INPUT ;
    USE SIGNAL ;
    PORT
      LAYER M4 ;
        RECT  0 47.184 0.084 47.208 ;
    END
  END d[496]
  PIN d[497]
    DIRECTION INPUT ;
    USE SIGNAL ;
    PORT
      LAYER M4 ;
        RECT  0 47.28 0.084 47.304 ;
    END
  END d[497]
  PIN d[498]
    DIRECTION INPUT ;
    USE SIGNAL ;
    PORT
      LAYER M4 ;
        RECT  0 47.376 0.084 47.4 ;
    END
  END d[498]
  PIN d[499]
    DIRECTION INPUT ;
    USE SIGNAL ;
    PORT
      LAYER M4 ;
        RECT  0 47.472 0.084 47.496 ;
    END
  END d[499]
  PIN d[49]
    DIRECTION INPUT ;
    USE SIGNAL ;
    PORT
      LAYER M4 ;
        RECT  0 34.224 0.084 34.248 ;
    END
  END d[49]
  PIN d[4]
    DIRECTION INPUT ;
    USE SIGNAL ;
    PORT
      LAYER M4 ;
        RECT  0 26.832 0.084 26.856 ;
    END
  END d[4]
  PIN d[500]
    DIRECTION INPUT ;
    USE SIGNAL ;
    PORT
      LAYER M4 ;
        RECT  0 47.568 0.084 47.592 ;
    END
  END d[500]
  PIN d[501]
    DIRECTION INPUT ;
    USE SIGNAL ;
    PORT
      LAYER M4 ;
        RECT  0 47.664 0.084 47.688 ;
    END
  END d[501]
  PIN d[502]
    DIRECTION INPUT ;
    USE SIGNAL ;
    PORT
      LAYER M4 ;
        RECT  0 47.76 0.084 47.784 ;
    END
  END d[502]
  PIN d[503]
    DIRECTION INPUT ;
    USE SIGNAL ;
    PORT
      LAYER M4 ;
        RECT  0 47.856 0.084 47.88 ;
    END
  END d[503]
  PIN d[504]
    DIRECTION INPUT ;
    USE SIGNAL ;
    PORT
      LAYER M4 ;
        RECT  0 47.952 0.084 47.976 ;
    END
  END d[504]
  PIN d[505]
    DIRECTION INPUT ;
    USE SIGNAL ;
    PORT
      LAYER M4 ;
        RECT  0 48.048 0.084 48.072 ;
    END
  END d[505]
  PIN d[506]
    DIRECTION INPUT ;
    USE SIGNAL ;
    PORT
      LAYER M4 ;
        RECT  0 48.144 0.084 48.168 ;
    END
  END d[506]
  PIN d[507]
    DIRECTION INPUT ;
    USE SIGNAL ;
    PORT
      LAYER M4 ;
        RECT  0 48.24 0.084 48.264 ;
    END
  END d[507]
  PIN d[508]
    DIRECTION INPUT ;
    USE SIGNAL ;
    PORT
      LAYER M4 ;
        RECT  0 48.336 0.084 48.36 ;
    END
  END d[508]
  PIN d[509]
    DIRECTION INPUT ;
    USE SIGNAL ;
    PORT
      LAYER M4 ;
        RECT  0 48.432 0.084 48.456 ;
    END
  END d[509]
  PIN d[50]
    DIRECTION INPUT ;
    USE SIGNAL ;
    PORT
      LAYER M4 ;
        RECT  0 34.32 0.084 34.344 ;
    END
  END d[50]
  PIN d[510]
    DIRECTION INPUT ;
    USE SIGNAL ;
    PORT
      LAYER M4 ;
        RECT  0 48.528 0.084 48.552 ;
    END
  END d[510]
  PIN d[511]
    DIRECTION INPUT ;
    USE SIGNAL ;
    PORT
      LAYER M4 ;
        RECT  0 48.624 0.084 48.648 ;
    END
  END d[511]
  PIN d[51]
    DIRECTION INPUT ;
    USE SIGNAL ;
    PORT
      LAYER M4 ;
        RECT  0 34.416 0.084 34.44 ;
    END
  END d[51]
  PIN d[52]
    DIRECTION INPUT ;
    USE SIGNAL ;
    PORT
      LAYER M4 ;
        RECT  0 34.512 0.084 34.536 ;
    END
  END d[52]
  PIN d[53]
    DIRECTION INPUT ;
    USE SIGNAL ;
    PORT
      LAYER M4 ;
        RECT  0 34.608 0.084 34.632 ;
    END
  END d[53]
  PIN d[54]
    DIRECTION INPUT ;
    USE SIGNAL ;
    PORT
      LAYER M4 ;
        RECT  0 34.704 0.084 34.728 ;
    END
  END d[54]
  PIN d[55]
    DIRECTION INPUT ;
    USE SIGNAL ;
    PORT
      LAYER M4 ;
        RECT  0 34.8 0.084 34.824 ;
    END
  END d[55]
  PIN d[56]
    DIRECTION INPUT ;
    USE SIGNAL ;
    PORT
      LAYER M4 ;
        RECT  0 34.896 0.084 34.92 ;
    END
  END d[56]
  PIN d[57]
    DIRECTION INPUT ;
    USE SIGNAL ;
    PORT
      LAYER M4 ;
        RECT  0 34.992 0.084 35.016 ;
    END
  END d[57]
  PIN d[58]
    DIRECTION INPUT ;
    USE SIGNAL ;
    PORT
      LAYER M4 ;
        RECT  0 35.088 0.084 35.112 ;
    END
  END d[58]
  PIN d[59]
    DIRECTION INPUT ;
    USE SIGNAL ;
    PORT
      LAYER M4 ;
        RECT  0 35.184 0.084 35.208 ;
    END
  END d[59]
  PIN d[5]
    DIRECTION INPUT ;
    USE SIGNAL ;
    PORT
      LAYER M4 ;
        RECT  0 26.928 0.084 26.952 ;
    END
  END d[5]
  PIN d[60]
    DIRECTION INPUT ;
    USE SIGNAL ;
    PORT
      LAYER M4 ;
        RECT  0 35.28 0.084 35.304 ;
    END
  END d[60]
  PIN d[61]
    DIRECTION INPUT ;
    USE SIGNAL ;
    PORT
      LAYER M4 ;
        RECT  0 35.376 0.084 35.4 ;
    END
  END d[61]
  PIN d[62]
    DIRECTION INPUT ;
    USE SIGNAL ;
    PORT
      LAYER M4 ;
        RECT  0 35.472 0.084 35.496 ;
    END
  END d[62]
  PIN d[63]
    DIRECTION INPUT ;
    USE SIGNAL ;
    PORT
      LAYER M4 ;
        RECT  0 35.568 0.084 35.592 ;
    END
  END d[63]
  PIN d[64]
    DIRECTION INPUT ;
    USE SIGNAL ;
    PORT
      LAYER M4 ;
        RECT  0 7.248 0.084 7.272 ;
    END
  END d[64]
  PIN d[65]
    DIRECTION INPUT ;
    USE SIGNAL ;
    PORT
      LAYER M4 ;
        RECT  0 7.344 0.084 7.368 ;
    END
  END d[65]
  PIN d[66]
    DIRECTION INPUT ;
    USE SIGNAL ;
    PORT
      LAYER M4 ;
        RECT  0 7.44 0.084 7.464 ;
    END
  END d[66]
  PIN d[67]
    DIRECTION INPUT ;
    USE SIGNAL ;
    PORT
      LAYER M4 ;
        RECT  0 7.536 0.084 7.56 ;
    END
  END d[67]
  PIN d[68]
    DIRECTION INPUT ;
    USE SIGNAL ;
    PORT
      LAYER M4 ;
        RECT  0 7.632 0.084 7.656 ;
    END
  END d[68]
  PIN d[69]
    DIRECTION INPUT ;
    USE SIGNAL ;
    PORT
      LAYER M4 ;
        RECT  0 7.728 0.084 7.752 ;
    END
  END d[69]
  PIN d[6]
    DIRECTION INPUT ;
    USE SIGNAL ;
    PORT
      LAYER M4 ;
        RECT  0 27.024 0.084 27.048 ;
    END
  END d[6]
  PIN d[70]
    DIRECTION INPUT ;
    USE SIGNAL ;
    PORT
      LAYER M4 ;
        RECT  0 7.824 0.084 7.848 ;
    END
  END d[70]
  PIN d[71]
    DIRECTION INPUT ;
    USE SIGNAL ;
    PORT
      LAYER M4 ;
        RECT  0 7.92 0.084 7.944 ;
    END
  END d[71]
  PIN d[72]
    DIRECTION INPUT ;
    USE SIGNAL ;
    PORT
      LAYER M4 ;
        RECT  0 8.016 0.084 8.04 ;
    END
  END d[72]
  PIN d[73]
    DIRECTION INPUT ;
    USE SIGNAL ;
    PORT
      LAYER M4 ;
        RECT  0 8.112 0.084 8.136 ;
    END
  END d[73]
  PIN d[74]
    DIRECTION INPUT ;
    USE SIGNAL ;
    PORT
      LAYER M4 ;
        RECT  0 8.208 0.084 8.232 ;
    END
  END d[74]
  PIN d[75]
    DIRECTION INPUT ;
    USE SIGNAL ;
    PORT
      LAYER M4 ;
        RECT  0 8.304 0.084 8.328 ;
    END
  END d[75]
  PIN d[76]
    DIRECTION INPUT ;
    USE SIGNAL ;
    PORT
      LAYER M4 ;
        RECT  0 8.4 0.084 8.424 ;
    END
  END d[76]
  PIN d[77]
    DIRECTION INPUT ;
    USE SIGNAL ;
    PORT
      LAYER M4 ;
        RECT  0 8.496 0.084 8.52 ;
    END
  END d[77]
  PIN d[78]
    DIRECTION INPUT ;
    USE SIGNAL ;
    PORT
      LAYER M4 ;
        RECT  0 8.592 0.084 8.616 ;
    END
  END d[78]
  PIN d[79]
    DIRECTION INPUT ;
    USE SIGNAL ;
    PORT
      LAYER M4 ;
        RECT  0 8.688 0.084 8.712 ;
    END
  END d[79]
  PIN d[7]
    DIRECTION INPUT ;
    USE SIGNAL ;
    PORT
      LAYER M4 ;
        RECT  0 27.12 0.084 27.144 ;
    END
  END d[7]
  PIN d[80]
    DIRECTION INPUT ;
    USE SIGNAL ;
    PORT
      LAYER M4 ;
        RECT  0 8.784 0.084 8.808 ;
    END
  END d[80]
  PIN d[81]
    DIRECTION INPUT ;
    USE SIGNAL ;
    PORT
      LAYER M4 ;
        RECT  0 8.88 0.084 8.904 ;
    END
  END d[81]
  PIN d[82]
    DIRECTION INPUT ;
    USE SIGNAL ;
    PORT
      LAYER M4 ;
        RECT  0 8.976 0.084 9 ;
    END
  END d[82]
  PIN d[83]
    DIRECTION INPUT ;
    USE SIGNAL ;
    PORT
      LAYER M4 ;
        RECT  0 9.072 0.084 9.096 ;
    END
  END d[83]
  PIN d[84]
    DIRECTION INPUT ;
    USE SIGNAL ;
    PORT
      LAYER M4 ;
        RECT  0 9.168 0.084 9.192 ;
    END
  END d[84]
  PIN d[85]
    DIRECTION INPUT ;
    USE SIGNAL ;
    PORT
      LAYER M4 ;
        RECT  0 9.264 0.084 9.288 ;
    END
  END d[85]
  PIN d[86]
    DIRECTION INPUT ;
    USE SIGNAL ;
    PORT
      LAYER M4 ;
        RECT  0 9.36 0.084 9.384 ;
    END
  END d[86]
  PIN d[87]
    DIRECTION INPUT ;
    USE SIGNAL ;
    PORT
      LAYER M4 ;
        RECT  0 9.456 0.084 9.48 ;
    END
  END d[87]
  PIN d[88]
    DIRECTION INPUT ;
    USE SIGNAL ;
    PORT
      LAYER M4 ;
        RECT  0 9.552 0.084 9.576 ;
    END
  END d[88]
  PIN d[89]
    DIRECTION INPUT ;
    USE SIGNAL ;
    PORT
      LAYER M4 ;
        RECT  0 9.648 0.084 9.672 ;
    END
  END d[89]
  PIN d[8]
    DIRECTION INPUT ;
    USE SIGNAL ;
    PORT
      LAYER M4 ;
        RECT  0 27.216 0.084 27.24 ;
    END
  END d[8]
  PIN d[90]
    DIRECTION INPUT ;
    USE SIGNAL ;
    PORT
      LAYER M4 ;
        RECT  0 9.744 0.084 9.768 ;
    END
  END d[90]
  PIN d[91]
    DIRECTION INPUT ;
    USE SIGNAL ;
    PORT
      LAYER M4 ;
        RECT  0 9.84 0.084 9.864 ;
    END
  END d[91]
  PIN d[92]
    DIRECTION INPUT ;
    USE SIGNAL ;
    PORT
      LAYER M4 ;
        RECT  0 9.936 0.084 9.96 ;
    END
  END d[92]
  PIN d[93]
    DIRECTION INPUT ;
    USE SIGNAL ;
    PORT
      LAYER M4 ;
        RECT  0 10.032 0.084 10.056 ;
    END
  END d[93]
  PIN d[94]
    DIRECTION INPUT ;
    USE SIGNAL ;
    PORT
      LAYER M4 ;
        RECT  0 10.128 0.084 10.152 ;
    END
  END d[94]
  PIN d[95]
    DIRECTION INPUT ;
    USE SIGNAL ;
    PORT
      LAYER M4 ;
        RECT  0 10.224 0.084 10.248 ;
    END
  END d[95]
  PIN d[96]
    DIRECTION INPUT ;
    USE SIGNAL ;
    PORT
      LAYER M4 ;
        RECT  0 38.736 0.084 38.76 ;
    END
  END d[96]
  PIN d[97]
    DIRECTION INPUT ;
    USE SIGNAL ;
    PORT
      LAYER M4 ;
        RECT  0 38.832 0.084 38.856 ;
    END
  END d[97]
  PIN d[98]
    DIRECTION INPUT ;
    USE SIGNAL ;
    PORT
      LAYER M4 ;
        RECT  0 38.928 0.084 38.952 ;
    END
  END d[98]
  PIN d[99]
    DIRECTION INPUT ;
    USE SIGNAL ;
    PORT
      LAYER M4 ;
        RECT  0 39.024 0.084 39.048 ;
    END
  END d[99]
  PIN d[9]
    DIRECTION INPUT ;
    USE SIGNAL ;
    PORT
      LAYER M4 ;
        RECT  0 27.312 0.084 27.336 ;
    END
  END d[9]
  PIN q[0]
    DIRECTION OUTPUT ;
    USE SIGNAL ;
    PORT
      LAYER M4 ;
        RECT  21.516 26.064 21.6 26.088 ;
    END
  END q[0]
  PIN q[100]
    DIRECTION OUTPUT ;
    USE SIGNAL ;
    PORT
      LAYER M4 ;
        RECT  21.516 23.376 21.6 23.4 ;
    END
  END q[100]
  PIN q[101]
    DIRECTION OUTPUT ;
    USE SIGNAL ;
    PORT
      LAYER M4 ;
        RECT  21.516 23.472 21.6 23.496 ;
    END
  END q[101]
  PIN q[102]
    DIRECTION OUTPUT ;
    USE SIGNAL ;
    PORT
      LAYER M4 ;
        RECT  21.516 23.568 21.6 23.592 ;
    END
  END q[102]
  PIN q[103]
    DIRECTION OUTPUT ;
    USE SIGNAL ;
    PORT
      LAYER M4 ;
        RECT  21.516 23.664 21.6 23.688 ;
    END
  END q[103]
  PIN q[104]
    DIRECTION OUTPUT ;
    USE SIGNAL ;
    PORT
      LAYER M4 ;
        RECT  21.516 23.76 21.6 23.784 ;
    END
  END q[104]
  PIN q[105]
    DIRECTION OUTPUT ;
    USE SIGNAL ;
    PORT
      LAYER M4 ;
        RECT  21.516 23.856 21.6 23.88 ;
    END
  END q[105]
  PIN q[106]
    DIRECTION OUTPUT ;
    USE SIGNAL ;
    PORT
      LAYER M4 ;
        RECT  21.516 23.952 21.6 23.976 ;
    END
  END q[106]
  PIN q[107]
    DIRECTION OUTPUT ;
    USE SIGNAL ;
    PORT
      LAYER M4 ;
        RECT  21.516 24.048 21.6 24.072 ;
    END
  END q[107]
  PIN q[108]
    DIRECTION OUTPUT ;
    USE SIGNAL ;
    PORT
      LAYER M4 ;
        RECT  21.516 24.144 21.6 24.168 ;
    END
  END q[108]
  PIN q[109]
    DIRECTION OUTPUT ;
    USE SIGNAL ;
    PORT
      LAYER M4 ;
        RECT  21.516 24.24 21.6 24.264 ;
    END
  END q[109]
  PIN q[10]
    DIRECTION OUTPUT ;
    USE SIGNAL ;
    PORT
      LAYER M4 ;
        RECT  21.516 27.024 21.6 27.048 ;
    END
  END q[10]
  PIN q[110]
    DIRECTION OUTPUT ;
    USE SIGNAL ;
    PORT
      LAYER M4 ;
        RECT  21.516 24.336 21.6 24.36 ;
    END
  END q[110]
  PIN q[111]
    DIRECTION OUTPUT ;
    USE SIGNAL ;
    PORT
      LAYER M4 ;
        RECT  21.516 24.432 21.6 24.456 ;
    END
  END q[111]
  PIN q[112]
    DIRECTION OUTPUT ;
    USE SIGNAL ;
    PORT
      LAYER M4 ;
        RECT  21.516 24.528 21.6 24.552 ;
    END
  END q[112]
  PIN q[113]
    DIRECTION OUTPUT ;
    USE SIGNAL ;
    PORT
      LAYER M4 ;
        RECT  21.516 24.624 21.6 24.648 ;
    END
  END q[113]
  PIN q[114]
    DIRECTION OUTPUT ;
    USE SIGNAL ;
    PORT
      LAYER M4 ;
        RECT  21.516 24.72 21.6 24.744 ;
    END
  END q[114]
  PIN q[115]
    DIRECTION OUTPUT ;
    USE SIGNAL ;
    PORT
      LAYER M4 ;
        RECT  21.516 24.816 21.6 24.84 ;
    END
  END q[115]
  PIN q[116]
    DIRECTION OUTPUT ;
    USE SIGNAL ;
    PORT
      LAYER M4 ;
        RECT  21.516 24.912 21.6 24.936 ;
    END
  END q[116]
  PIN q[117]
    DIRECTION OUTPUT ;
    USE SIGNAL ;
    PORT
      LAYER M4 ;
        RECT  21.516 25.008 21.6 25.032 ;
    END
  END q[117]
  PIN q[118]
    DIRECTION OUTPUT ;
    USE SIGNAL ;
    PORT
      LAYER M4 ;
        RECT  21.516 25.104 21.6 25.128 ;
    END
  END q[118]
  PIN q[119]
    DIRECTION OUTPUT ;
    USE SIGNAL ;
    PORT
      LAYER M4 ;
        RECT  21.516 25.2 21.6 25.224 ;
    END
  END q[119]
  PIN q[11]
    DIRECTION OUTPUT ;
    USE SIGNAL ;
    PORT
      LAYER M4 ;
        RECT  21.516 27.12 21.6 27.144 ;
    END
  END q[11]
  PIN q[120]
    DIRECTION OUTPUT ;
    USE SIGNAL ;
    PORT
      LAYER M4 ;
        RECT  21.516 25.296 21.6 25.32 ;
    END
  END q[120]
  PIN q[121]
    DIRECTION OUTPUT ;
    USE SIGNAL ;
    PORT
      LAYER M4 ;
        RECT  21.516 25.392 21.6 25.416 ;
    END
  END q[121]
  PIN q[122]
    DIRECTION OUTPUT ;
    USE SIGNAL ;
    PORT
      LAYER M4 ;
        RECT  21.516 25.488 21.6 25.512 ;
    END
  END q[122]
  PIN q[123]
    DIRECTION OUTPUT ;
    USE SIGNAL ;
    PORT
      LAYER M4 ;
        RECT  21.516 25.584 21.6 25.608 ;
    END
  END q[123]
  PIN q[124]
    DIRECTION OUTPUT ;
    USE SIGNAL ;
    PORT
      LAYER M4 ;
        RECT  21.516 25.68 21.6 25.704 ;
    END
  END q[124]
  PIN q[125]
    DIRECTION OUTPUT ;
    USE SIGNAL ;
    PORT
      LAYER M4 ;
        RECT  21.516 25.776 21.6 25.8 ;
    END
  END q[125]
  PIN q[126]
    DIRECTION OUTPUT ;
    USE SIGNAL ;
    PORT
      LAYER M4 ;
        RECT  21.516 25.872 21.6 25.896 ;
    END
  END q[126]
  PIN q[127]
    DIRECTION OUTPUT ;
    USE SIGNAL ;
    PORT
      LAYER M4 ;
        RECT  21.516 25.968 21.6 25.992 ;
    END
  END q[127]
  PIN q[128]
    DIRECTION OUTPUT ;
    USE SIGNAL ;
    PORT
      LAYER M4 ;
        RECT  21.516 29.136 21.6 29.16 ;
    END
  END q[128]
  PIN q[129]
    DIRECTION OUTPUT ;
    USE SIGNAL ;
    PORT
      LAYER M4 ;
        RECT  21.516 29.232 21.6 29.256 ;
    END
  END q[129]
  PIN q[12]
    DIRECTION OUTPUT ;
    USE SIGNAL ;
    PORT
      LAYER M4 ;
        RECT  21.516 27.216 21.6 27.24 ;
    END
  END q[12]
  PIN q[130]
    DIRECTION OUTPUT ;
    USE SIGNAL ;
    PORT
      LAYER M4 ;
        RECT  21.516 29.328 21.6 29.352 ;
    END
  END q[130]
  PIN q[131]
    DIRECTION OUTPUT ;
    USE SIGNAL ;
    PORT
      LAYER M4 ;
        RECT  21.516 29.424 21.6 29.448 ;
    END
  END q[131]
  PIN q[132]
    DIRECTION OUTPUT ;
    USE SIGNAL ;
    PORT
      LAYER M4 ;
        RECT  21.516 29.52 21.6 29.544 ;
    END
  END q[132]
  PIN q[133]
    DIRECTION OUTPUT ;
    USE SIGNAL ;
    PORT
      LAYER M4 ;
        RECT  21.516 29.616 21.6 29.64 ;
    END
  END q[133]
  PIN q[134]
    DIRECTION OUTPUT ;
    USE SIGNAL ;
    PORT
      LAYER M4 ;
        RECT  21.516 29.712 21.6 29.736 ;
    END
  END q[134]
  PIN q[135]
    DIRECTION OUTPUT ;
    USE SIGNAL ;
    PORT
      LAYER M4 ;
        RECT  21.516 29.808 21.6 29.832 ;
    END
  END q[135]
  PIN q[136]
    DIRECTION OUTPUT ;
    USE SIGNAL ;
    PORT
      LAYER M4 ;
        RECT  21.516 29.904 21.6 29.928 ;
    END
  END q[136]
  PIN q[137]
    DIRECTION OUTPUT ;
    USE SIGNAL ;
    PORT
      LAYER M4 ;
        RECT  21.516 30 21.6 30.024 ;
    END
  END q[137]
  PIN q[138]
    DIRECTION OUTPUT ;
    USE SIGNAL ;
    PORT
      LAYER M4 ;
        RECT  21.516 30.096 21.6 30.12 ;
    END
  END q[138]
  PIN q[139]
    DIRECTION OUTPUT ;
    USE SIGNAL ;
    PORT
      LAYER M4 ;
        RECT  21.516 30.192 21.6 30.216 ;
    END
  END q[139]
  PIN q[13]
    DIRECTION OUTPUT ;
    USE SIGNAL ;
    PORT
      LAYER M4 ;
        RECT  21.516 27.312 21.6 27.336 ;
    END
  END q[13]
  PIN q[140]
    DIRECTION OUTPUT ;
    USE SIGNAL ;
    PORT
      LAYER M4 ;
        RECT  21.516 30.288 21.6 30.312 ;
    END
  END q[140]
  PIN q[141]
    DIRECTION OUTPUT ;
    USE SIGNAL ;
    PORT
      LAYER M4 ;
        RECT  21.516 30.384 21.6 30.408 ;
    END
  END q[141]
  PIN q[142]
    DIRECTION OUTPUT ;
    USE SIGNAL ;
    PORT
      LAYER M4 ;
        RECT  21.516 30.48 21.6 30.504 ;
    END
  END q[142]
  PIN q[143]
    DIRECTION OUTPUT ;
    USE SIGNAL ;
    PORT
      LAYER M4 ;
        RECT  21.516 30.576 21.6 30.6 ;
    END
  END q[143]
  PIN q[144]
    DIRECTION OUTPUT ;
    USE SIGNAL ;
    PORT
      LAYER M4 ;
        RECT  21.516 30.672 21.6 30.696 ;
    END
  END q[144]
  PIN q[145]
    DIRECTION OUTPUT ;
    USE SIGNAL ;
    PORT
      LAYER M4 ;
        RECT  21.516 30.768 21.6 30.792 ;
    END
  END q[145]
  PIN q[146]
    DIRECTION OUTPUT ;
    USE SIGNAL ;
    PORT
      LAYER M4 ;
        RECT  21.516 30.864 21.6 30.888 ;
    END
  END q[146]
  PIN q[147]
    DIRECTION OUTPUT ;
    USE SIGNAL ;
    PORT
      LAYER M4 ;
        RECT  21.516 30.96 21.6 30.984 ;
    END
  END q[147]
  PIN q[148]
    DIRECTION OUTPUT ;
    USE SIGNAL ;
    PORT
      LAYER M4 ;
        RECT  21.516 31.056 21.6 31.08 ;
    END
  END q[148]
  PIN q[149]
    DIRECTION OUTPUT ;
    USE SIGNAL ;
    PORT
      LAYER M4 ;
        RECT  21.516 31.152 21.6 31.176 ;
    END
  END q[149]
  PIN q[14]
    DIRECTION OUTPUT ;
    USE SIGNAL ;
    PORT
      LAYER M4 ;
        RECT  21.516 27.408 21.6 27.432 ;
    END
  END q[14]
  PIN q[150]
    DIRECTION OUTPUT ;
    USE SIGNAL ;
    PORT
      LAYER M4 ;
        RECT  21.516 31.248 21.6 31.272 ;
    END
  END q[150]
  PIN q[151]
    DIRECTION OUTPUT ;
    USE SIGNAL ;
    PORT
      LAYER M4 ;
        RECT  21.516 31.344 21.6 31.368 ;
    END
  END q[151]
  PIN q[152]
    DIRECTION OUTPUT ;
    USE SIGNAL ;
    PORT
      LAYER M4 ;
        RECT  21.516 31.44 21.6 31.464 ;
    END
  END q[152]
  PIN q[153]
    DIRECTION OUTPUT ;
    USE SIGNAL ;
    PORT
      LAYER M4 ;
        RECT  21.516 31.536 21.6 31.56 ;
    END
  END q[153]
  PIN q[154]
    DIRECTION OUTPUT ;
    USE SIGNAL ;
    PORT
      LAYER M4 ;
        RECT  21.516 31.632 21.6 31.656 ;
    END
  END q[154]
  PIN q[155]
    DIRECTION OUTPUT ;
    USE SIGNAL ;
    PORT
      LAYER M4 ;
        RECT  21.516 31.728 21.6 31.752 ;
    END
  END q[155]
  PIN q[156]
    DIRECTION OUTPUT ;
    USE SIGNAL ;
    PORT
      LAYER M4 ;
        RECT  21.516 31.824 21.6 31.848 ;
    END
  END q[156]
  PIN q[157]
    DIRECTION OUTPUT ;
    USE SIGNAL ;
    PORT
      LAYER M4 ;
        RECT  21.516 31.92 21.6 31.944 ;
    END
  END q[157]
  PIN q[158]
    DIRECTION OUTPUT ;
    USE SIGNAL ;
    PORT
      LAYER M4 ;
        RECT  21.516 32.016 21.6 32.04 ;
    END
  END q[158]
  PIN q[159]
    DIRECTION OUTPUT ;
    USE SIGNAL ;
    PORT
      LAYER M4 ;
        RECT  21.516 32.112 21.6 32.136 ;
    END
  END q[159]
  PIN q[15]
    DIRECTION OUTPUT ;
    USE SIGNAL ;
    PORT
      LAYER M4 ;
        RECT  21.516 27.504 21.6 27.528 ;
    END
  END q[15]
  PIN q[160]
    DIRECTION OUTPUT ;
    USE SIGNAL ;
    PORT
      LAYER M4 ;
        RECT  21.516 51.408 21.6 51.432 ;
    END
  END q[160]
  PIN q[161]
    DIRECTION OUTPUT ;
    USE SIGNAL ;
    PORT
      LAYER M4 ;
        RECT  21.516 51.504 21.6 51.528 ;
    END
  END q[161]
  PIN q[162]
    DIRECTION OUTPUT ;
    USE SIGNAL ;
    PORT
      LAYER M4 ;
        RECT  21.516 51.6 21.6 51.624 ;
    END
  END q[162]
  PIN q[163]
    DIRECTION OUTPUT ;
    USE SIGNAL ;
    PORT
      LAYER M4 ;
        RECT  21.516 51.696 21.6 51.72 ;
    END
  END q[163]
  PIN q[164]
    DIRECTION OUTPUT ;
    USE SIGNAL ;
    PORT
      LAYER M4 ;
        RECT  21.516 51.792 21.6 51.816 ;
    END
  END q[164]
  PIN q[165]
    DIRECTION OUTPUT ;
    USE SIGNAL ;
    PORT
      LAYER M4 ;
        RECT  21.516 51.888 21.6 51.912 ;
    END
  END q[165]
  PIN q[166]
    DIRECTION OUTPUT ;
    USE SIGNAL ;
    PORT
      LAYER M4 ;
        RECT  21.516 51.984 21.6 52.008 ;
    END
  END q[166]
  PIN q[167]
    DIRECTION OUTPUT ;
    USE SIGNAL ;
    PORT
      LAYER M4 ;
        RECT  21.516 52.08 21.6 52.104 ;
    END
  END q[167]
  PIN q[168]
    DIRECTION OUTPUT ;
    USE SIGNAL ;
    PORT
      LAYER M4 ;
        RECT  21.516 52.176 21.6 52.2 ;
    END
  END q[168]
  PIN q[169]
    DIRECTION OUTPUT ;
    USE SIGNAL ;
    PORT
      LAYER M4 ;
        RECT  21.516 52.272 21.6 52.296 ;
    END
  END q[169]
  PIN q[16]
    DIRECTION OUTPUT ;
    USE SIGNAL ;
    PORT
      LAYER M4 ;
        RECT  21.516 27.6 21.6 27.624 ;
    END
  END q[16]
  PIN q[170]
    DIRECTION OUTPUT ;
    USE SIGNAL ;
    PORT
      LAYER M4 ;
        RECT  21.516 52.368 21.6 52.392 ;
    END
  END q[170]
  PIN q[171]
    DIRECTION OUTPUT ;
    USE SIGNAL ;
    PORT
      LAYER M4 ;
        RECT  21.516 52.464 21.6 52.488 ;
    END
  END q[171]
  PIN q[172]
    DIRECTION OUTPUT ;
    USE SIGNAL ;
    PORT
      LAYER M4 ;
        RECT  21.516 52.56 21.6 52.584 ;
    END
  END q[172]
  PIN q[173]
    DIRECTION OUTPUT ;
    USE SIGNAL ;
    PORT
      LAYER M4 ;
        RECT  21.516 52.656 21.6 52.68 ;
    END
  END q[173]
  PIN q[174]
    DIRECTION OUTPUT ;
    USE SIGNAL ;
    PORT
      LAYER M4 ;
        RECT  21.516 52.752 21.6 52.776 ;
    END
  END q[174]
  PIN q[175]
    DIRECTION OUTPUT ;
    USE SIGNAL ;
    PORT
      LAYER M4 ;
        RECT  21.516 52.848 21.6 52.872 ;
    END
  END q[175]
  PIN q[176]
    DIRECTION OUTPUT ;
    USE SIGNAL ;
    PORT
      LAYER M4 ;
        RECT  21.516 52.944 21.6 52.968 ;
    END
  END q[176]
  PIN q[177]
    DIRECTION OUTPUT ;
    USE SIGNAL ;
    PORT
      LAYER M4 ;
        RECT  21.516 53.04 21.6 53.064 ;
    END
  END q[177]
  PIN q[178]
    DIRECTION OUTPUT ;
    USE SIGNAL ;
    PORT
      LAYER M4 ;
        RECT  21.516 53.136 21.6 53.16 ;
    END
  END q[178]
  PIN q[179]
    DIRECTION OUTPUT ;
    USE SIGNAL ;
    PORT
      LAYER M4 ;
        RECT  21.516 53.232 21.6 53.256 ;
    END
  END q[179]
  PIN q[17]
    DIRECTION OUTPUT ;
    USE SIGNAL ;
    PORT
      LAYER M4 ;
        RECT  21.516 27.696 21.6 27.72 ;
    END
  END q[17]
  PIN q[180]
    DIRECTION OUTPUT ;
    USE SIGNAL ;
    PORT
      LAYER M4 ;
        RECT  21.516 53.328 21.6 53.352 ;
    END
  END q[180]
  PIN q[181]
    DIRECTION OUTPUT ;
    USE SIGNAL ;
    PORT
      LAYER M4 ;
        RECT  21.516 53.424 21.6 53.448 ;
    END
  END q[181]
  PIN q[182]
    DIRECTION OUTPUT ;
    USE SIGNAL ;
    PORT
      LAYER M4 ;
        RECT  21.516 53.52 21.6 53.544 ;
    END
  END q[182]
  PIN q[183]
    DIRECTION OUTPUT ;
    USE SIGNAL ;
    PORT
      LAYER M4 ;
        RECT  21.516 53.616 21.6 53.64 ;
    END
  END q[183]
  PIN q[184]
    DIRECTION OUTPUT ;
    USE SIGNAL ;
    PORT
      LAYER M4 ;
        RECT  21.516 53.712 21.6 53.736 ;
    END
  END q[184]
  PIN q[185]
    DIRECTION OUTPUT ;
    USE SIGNAL ;
    PORT
      LAYER M4 ;
        RECT  21.516 53.808 21.6 53.832 ;
    END
  END q[185]
  PIN q[186]
    DIRECTION OUTPUT ;
    USE SIGNAL ;
    PORT
      LAYER M4 ;
        RECT  21.516 53.904 21.6 53.928 ;
    END
  END q[186]
  PIN q[187]
    DIRECTION OUTPUT ;
    USE SIGNAL ;
    PORT
      LAYER M4 ;
        RECT  21.516 54 21.6 54.024 ;
    END
  END q[187]
  PIN q[188]
    DIRECTION OUTPUT ;
    USE SIGNAL ;
    PORT
      LAYER M4 ;
        RECT  21.516 54.096 21.6 54.12 ;
    END
  END q[188]
  PIN q[189]
    DIRECTION OUTPUT ;
    USE SIGNAL ;
    PORT
      LAYER M4 ;
        RECT  21.516 54.192 21.6 54.216 ;
    END
  END q[189]
  PIN q[18]
    DIRECTION OUTPUT ;
    USE SIGNAL ;
    PORT
      LAYER M4 ;
        RECT  21.516 27.792 21.6 27.816 ;
    END
  END q[18]
  PIN q[190]
    DIRECTION OUTPUT ;
    USE SIGNAL ;
    PORT
      LAYER M4 ;
        RECT  21.516 54.288 21.6 54.312 ;
    END
  END q[190]
  PIN q[191]
    DIRECTION OUTPUT ;
    USE SIGNAL ;
    PORT
      LAYER M4 ;
        RECT  21.516 54.384 21.6 54.408 ;
    END
  END q[191]
  PIN q[192]
    DIRECTION OUTPUT ;
    USE SIGNAL ;
    PORT
      LAYER M4 ;
        RECT  21.516 35.28 21.6 35.304 ;
    END
  END q[192]
  PIN q[193]
    DIRECTION OUTPUT ;
    USE SIGNAL ;
    PORT
      LAYER M4 ;
        RECT  21.516 35.376 21.6 35.4 ;
    END
  END q[193]
  PIN q[194]
    DIRECTION OUTPUT ;
    USE SIGNAL ;
    PORT
      LAYER M4 ;
        RECT  21.516 35.472 21.6 35.496 ;
    END
  END q[194]
  PIN q[195]
    DIRECTION OUTPUT ;
    USE SIGNAL ;
    PORT
      LAYER M4 ;
        RECT  21.516 35.568 21.6 35.592 ;
    END
  END q[195]
  PIN q[196]
    DIRECTION OUTPUT ;
    USE SIGNAL ;
    PORT
      LAYER M4 ;
        RECT  21.516 35.664 21.6 35.688 ;
    END
  END q[196]
  PIN q[197]
    DIRECTION OUTPUT ;
    USE SIGNAL ;
    PORT
      LAYER M4 ;
        RECT  21.516 35.76 21.6 35.784 ;
    END
  END q[197]
  PIN q[198]
    DIRECTION OUTPUT ;
    USE SIGNAL ;
    PORT
      LAYER M4 ;
        RECT  21.516 35.856 21.6 35.88 ;
    END
  END q[198]
  PIN q[199]
    DIRECTION OUTPUT ;
    USE SIGNAL ;
    PORT
      LAYER M4 ;
        RECT  21.516 35.952 21.6 35.976 ;
    END
  END q[199]
  PIN q[19]
    DIRECTION OUTPUT ;
    USE SIGNAL ;
    PORT
      LAYER M4 ;
        RECT  21.516 27.888 21.6 27.912 ;
    END
  END q[19]
  PIN q[1]
    DIRECTION OUTPUT ;
    USE SIGNAL ;
    PORT
      LAYER M4 ;
        RECT  21.516 26.16 21.6 26.184 ;
    END
  END q[1]
  PIN q[200]
    DIRECTION OUTPUT ;
    USE SIGNAL ;
    PORT
      LAYER M4 ;
        RECT  21.516 36.048 21.6 36.072 ;
    END
  END q[200]
  PIN q[201]
    DIRECTION OUTPUT ;
    USE SIGNAL ;
    PORT
      LAYER M4 ;
        RECT  21.516 36.144 21.6 36.168 ;
    END
  END q[201]
  PIN q[202]
    DIRECTION OUTPUT ;
    USE SIGNAL ;
    PORT
      LAYER M4 ;
        RECT  21.516 36.24 21.6 36.264 ;
    END
  END q[202]
  PIN q[203]
    DIRECTION OUTPUT ;
    USE SIGNAL ;
    PORT
      LAYER M4 ;
        RECT  21.516 36.336 21.6 36.36 ;
    END
  END q[203]
  PIN q[204]
    DIRECTION OUTPUT ;
    USE SIGNAL ;
    PORT
      LAYER M4 ;
        RECT  21.516 36.432 21.6 36.456 ;
    END
  END q[204]
  PIN q[205]
    DIRECTION OUTPUT ;
    USE SIGNAL ;
    PORT
      LAYER M4 ;
        RECT  21.516 36.528 21.6 36.552 ;
    END
  END q[205]
  PIN q[206]
    DIRECTION OUTPUT ;
    USE SIGNAL ;
    PORT
      LAYER M4 ;
        RECT  21.516 36.624 21.6 36.648 ;
    END
  END q[206]
  PIN q[207]
    DIRECTION OUTPUT ;
    USE SIGNAL ;
    PORT
      LAYER M4 ;
        RECT  21.516 36.72 21.6 36.744 ;
    END
  END q[207]
  PIN q[208]
    DIRECTION OUTPUT ;
    USE SIGNAL ;
    PORT
      LAYER M4 ;
        RECT  21.516 36.816 21.6 36.84 ;
    END
  END q[208]
  PIN q[209]
    DIRECTION OUTPUT ;
    USE SIGNAL ;
    PORT
      LAYER M4 ;
        RECT  21.516 36.912 21.6 36.936 ;
    END
  END q[209]
  PIN q[20]
    DIRECTION OUTPUT ;
    USE SIGNAL ;
    PORT
      LAYER M4 ;
        RECT  21.516 27.984 21.6 28.008 ;
    END
  END q[20]
  PIN q[210]
    DIRECTION OUTPUT ;
    USE SIGNAL ;
    PORT
      LAYER M4 ;
        RECT  21.516 37.008 21.6 37.032 ;
    END
  END q[210]
  PIN q[211]
    DIRECTION OUTPUT ;
    USE SIGNAL ;
    PORT
      LAYER M4 ;
        RECT  21.516 37.104 21.6 37.128 ;
    END
  END q[211]
  PIN q[212]
    DIRECTION OUTPUT ;
    USE SIGNAL ;
    PORT
      LAYER M4 ;
        RECT  21.516 37.2 21.6 37.224 ;
    END
  END q[212]
  PIN q[213]
    DIRECTION OUTPUT ;
    USE SIGNAL ;
    PORT
      LAYER M4 ;
        RECT  21.516 37.296 21.6 37.32 ;
    END
  END q[213]
  PIN q[214]
    DIRECTION OUTPUT ;
    USE SIGNAL ;
    PORT
      LAYER M4 ;
        RECT  21.516 37.392 21.6 37.416 ;
    END
  END q[214]
  PIN q[215]
    DIRECTION OUTPUT ;
    USE SIGNAL ;
    PORT
      LAYER M4 ;
        RECT  21.516 37.488 21.6 37.512 ;
    END
  END q[215]
  PIN q[216]
    DIRECTION OUTPUT ;
    USE SIGNAL ;
    PORT
      LAYER M4 ;
        RECT  21.516 37.584 21.6 37.608 ;
    END
  END q[216]
  PIN q[217]
    DIRECTION OUTPUT ;
    USE SIGNAL ;
    PORT
      LAYER M4 ;
        RECT  21.516 37.68 21.6 37.704 ;
    END
  END q[217]
  PIN q[218]
    DIRECTION OUTPUT ;
    USE SIGNAL ;
    PORT
      LAYER M4 ;
        RECT  21.516 37.776 21.6 37.8 ;
    END
  END q[218]
  PIN q[219]
    DIRECTION OUTPUT ;
    USE SIGNAL ;
    PORT
      LAYER M4 ;
        RECT  21.516 37.872 21.6 37.896 ;
    END
  END q[219]
  PIN q[21]
    DIRECTION OUTPUT ;
    USE SIGNAL ;
    PORT
      LAYER M4 ;
        RECT  21.516 28.08 21.6 28.104 ;
    END
  END q[21]
  PIN q[220]
    DIRECTION OUTPUT ;
    USE SIGNAL ;
    PORT
      LAYER M4 ;
        RECT  21.516 37.968 21.6 37.992 ;
    END
  END q[220]
  PIN q[221]
    DIRECTION OUTPUT ;
    USE SIGNAL ;
    PORT
      LAYER M4 ;
        RECT  21.516 38.064 21.6 38.088 ;
    END
  END q[221]
  PIN q[222]
    DIRECTION OUTPUT ;
    USE SIGNAL ;
    PORT
      LAYER M4 ;
        RECT  21.516 38.16 21.6 38.184 ;
    END
  END q[222]
  PIN q[223]
    DIRECTION OUTPUT ;
    USE SIGNAL ;
    PORT
      LAYER M4 ;
        RECT  21.516 38.256 21.6 38.28 ;
    END
  END q[223]
  PIN q[224]
    DIRECTION OUTPUT ;
    USE SIGNAL ;
    PORT
      LAYER M4 ;
        RECT  21.516 42.192 21.6 42.216 ;
    END
  END q[224]
  PIN q[225]
    DIRECTION OUTPUT ;
    USE SIGNAL ;
    PORT
      LAYER M4 ;
        RECT  21.516 42.288 21.6 42.312 ;
    END
  END q[225]
  PIN q[226]
    DIRECTION OUTPUT ;
    USE SIGNAL ;
    PORT
      LAYER M4 ;
        RECT  21.516 42.384 21.6 42.408 ;
    END
  END q[226]
  PIN q[227]
    DIRECTION OUTPUT ;
    USE SIGNAL ;
    PORT
      LAYER M4 ;
        RECT  21.516 42.48 21.6 42.504 ;
    END
  END q[227]
  PIN q[228]
    DIRECTION OUTPUT ;
    USE SIGNAL ;
    PORT
      LAYER M4 ;
        RECT  21.516 42.576 21.6 42.6 ;
    END
  END q[228]
  PIN q[229]
    DIRECTION OUTPUT ;
    USE SIGNAL ;
    PORT
      LAYER M4 ;
        RECT  21.516 42.672 21.6 42.696 ;
    END
  END q[229]
  PIN q[22]
    DIRECTION OUTPUT ;
    USE SIGNAL ;
    PORT
      LAYER M4 ;
        RECT  21.516 28.176 21.6 28.2 ;
    END
  END q[22]
  PIN q[230]
    DIRECTION OUTPUT ;
    USE SIGNAL ;
    PORT
      LAYER M4 ;
        RECT  21.516 42.768 21.6 42.792 ;
    END
  END q[230]
  PIN q[231]
    DIRECTION OUTPUT ;
    USE SIGNAL ;
    PORT
      LAYER M4 ;
        RECT  21.516 42.864 21.6 42.888 ;
    END
  END q[231]
  PIN q[232]
    DIRECTION OUTPUT ;
    USE SIGNAL ;
    PORT
      LAYER M4 ;
        RECT  21.516 42.96 21.6 42.984 ;
    END
  END q[232]
  PIN q[233]
    DIRECTION OUTPUT ;
    USE SIGNAL ;
    PORT
      LAYER M4 ;
        RECT  21.516 43.056 21.6 43.08 ;
    END
  END q[233]
  PIN q[234]
    DIRECTION OUTPUT ;
    USE SIGNAL ;
    PORT
      LAYER M4 ;
        RECT  21.516 43.152 21.6 43.176 ;
    END
  END q[234]
  PIN q[235]
    DIRECTION OUTPUT ;
    USE SIGNAL ;
    PORT
      LAYER M4 ;
        RECT  21.516 43.248 21.6 43.272 ;
    END
  END q[235]
  PIN q[236]
    DIRECTION OUTPUT ;
    USE SIGNAL ;
    PORT
      LAYER M4 ;
        RECT  21.516 43.344 21.6 43.368 ;
    END
  END q[236]
  PIN q[237]
    DIRECTION OUTPUT ;
    USE SIGNAL ;
    PORT
      LAYER M4 ;
        RECT  21.516 43.44 21.6 43.464 ;
    END
  END q[237]
  PIN q[238]
    DIRECTION OUTPUT ;
    USE SIGNAL ;
    PORT
      LAYER M4 ;
        RECT  21.516 43.536 21.6 43.56 ;
    END
  END q[238]
  PIN q[239]
    DIRECTION OUTPUT ;
    USE SIGNAL ;
    PORT
      LAYER M4 ;
        RECT  21.516 43.632 21.6 43.656 ;
    END
  END q[239]
  PIN q[23]
    DIRECTION OUTPUT ;
    USE SIGNAL ;
    PORT
      LAYER M4 ;
        RECT  21.516 28.272 21.6 28.296 ;
    END
  END q[23]
  PIN q[240]
    DIRECTION OUTPUT ;
    USE SIGNAL ;
    PORT
      LAYER M4 ;
        RECT  21.516 43.728 21.6 43.752 ;
    END
  END q[240]
  PIN q[241]
    DIRECTION OUTPUT ;
    USE SIGNAL ;
    PORT
      LAYER M4 ;
        RECT  21.516 43.824 21.6 43.848 ;
    END
  END q[241]
  PIN q[242]
    DIRECTION OUTPUT ;
    USE SIGNAL ;
    PORT
      LAYER M4 ;
        RECT  21.516 43.92 21.6 43.944 ;
    END
  END q[242]
  PIN q[243]
    DIRECTION OUTPUT ;
    USE SIGNAL ;
    PORT
      LAYER M4 ;
        RECT  21.516 44.016 21.6 44.04 ;
    END
  END q[243]
  PIN q[244]
    DIRECTION OUTPUT ;
    USE SIGNAL ;
    PORT
      LAYER M4 ;
        RECT  21.516 44.112 21.6 44.136 ;
    END
  END q[244]
  PIN q[245]
    DIRECTION OUTPUT ;
    USE SIGNAL ;
    PORT
      LAYER M4 ;
        RECT  21.516 44.208 21.6 44.232 ;
    END
  END q[245]
  PIN q[246]
    DIRECTION OUTPUT ;
    USE SIGNAL ;
    PORT
      LAYER M4 ;
        RECT  21.516 44.304 21.6 44.328 ;
    END
  END q[246]
  PIN q[247]
    DIRECTION OUTPUT ;
    USE SIGNAL ;
    PORT
      LAYER M4 ;
        RECT  21.516 44.4 21.6 44.424 ;
    END
  END q[247]
  PIN q[248]
    DIRECTION OUTPUT ;
    USE SIGNAL ;
    PORT
      LAYER M4 ;
        RECT  21.516 44.496 21.6 44.52 ;
    END
  END q[248]
  PIN q[249]
    DIRECTION OUTPUT ;
    USE SIGNAL ;
    PORT
      LAYER M4 ;
        RECT  21.516 44.592 21.6 44.616 ;
    END
  END q[249]
  PIN q[24]
    DIRECTION OUTPUT ;
    USE SIGNAL ;
    PORT
      LAYER M4 ;
        RECT  21.516 28.368 21.6 28.392 ;
    END
  END q[24]
  PIN q[250]
    DIRECTION OUTPUT ;
    USE SIGNAL ;
    PORT
      LAYER M4 ;
        RECT  21.516 44.688 21.6 44.712 ;
    END
  END q[250]
  PIN q[251]
    DIRECTION OUTPUT ;
    USE SIGNAL ;
    PORT
      LAYER M4 ;
        RECT  21.516 44.784 21.6 44.808 ;
    END
  END q[251]
  PIN q[252]
    DIRECTION OUTPUT ;
    USE SIGNAL ;
    PORT
      LAYER M4 ;
        RECT  21.516 44.88 21.6 44.904 ;
    END
  END q[252]
  PIN q[253]
    DIRECTION OUTPUT ;
    USE SIGNAL ;
    PORT
      LAYER M4 ;
        RECT  21.516 44.976 21.6 45 ;
    END
  END q[253]
  PIN q[254]
    DIRECTION OUTPUT ;
    USE SIGNAL ;
    PORT
      LAYER M4 ;
        RECT  21.516 45.072 21.6 45.096 ;
    END
  END q[254]
  PIN q[255]
    DIRECTION OUTPUT ;
    USE SIGNAL ;
    PORT
      LAYER M4 ;
        RECT  21.516 45.168 21.6 45.192 ;
    END
  END q[255]
  PIN q[256]
    DIRECTION OUTPUT ;
    USE SIGNAL ;
    PORT
      LAYER M4 ;
        RECT  21.516 54.48 21.6 54.504 ;
    END
  END q[256]
  PIN q[257]
    DIRECTION OUTPUT ;
    USE SIGNAL ;
    PORT
      LAYER M4 ;
        RECT  21.516 54.576 21.6 54.6 ;
    END
  END q[257]
  PIN q[258]
    DIRECTION OUTPUT ;
    USE SIGNAL ;
    PORT
      LAYER M4 ;
        RECT  21.516 54.672 21.6 54.696 ;
    END
  END q[258]
  PIN q[259]
    DIRECTION OUTPUT ;
    USE SIGNAL ;
    PORT
      LAYER M4 ;
        RECT  21.516 54.768 21.6 54.792 ;
    END
  END q[259]
  PIN q[25]
    DIRECTION OUTPUT ;
    USE SIGNAL ;
    PORT
      LAYER M4 ;
        RECT  21.516 28.464 21.6 28.488 ;
    END
  END q[25]
  PIN q[260]
    DIRECTION OUTPUT ;
    USE SIGNAL ;
    PORT
      LAYER M4 ;
        RECT  21.516 54.864 21.6 54.888 ;
    END
  END q[260]
  PIN q[261]
    DIRECTION OUTPUT ;
    USE SIGNAL ;
    PORT
      LAYER M4 ;
        RECT  21.516 54.96 21.6 54.984 ;
    END
  END q[261]
  PIN q[262]
    DIRECTION OUTPUT ;
    USE SIGNAL ;
    PORT
      LAYER M4 ;
        RECT  21.516 55.056 21.6 55.08 ;
    END
  END q[262]
  PIN q[263]
    DIRECTION OUTPUT ;
    USE SIGNAL ;
    PORT
      LAYER M4 ;
        RECT  21.516 55.152 21.6 55.176 ;
    END
  END q[263]
  PIN q[264]
    DIRECTION OUTPUT ;
    USE SIGNAL ;
    PORT
      LAYER M4 ;
        RECT  21.516 55.248 21.6 55.272 ;
    END
  END q[264]
  PIN q[265]
    DIRECTION OUTPUT ;
    USE SIGNAL ;
    PORT
      LAYER M4 ;
        RECT  21.516 55.344 21.6 55.368 ;
    END
  END q[265]
  PIN q[266]
    DIRECTION OUTPUT ;
    USE SIGNAL ;
    PORT
      LAYER M4 ;
        RECT  21.516 55.44 21.6 55.464 ;
    END
  END q[266]
  PIN q[267]
    DIRECTION OUTPUT ;
    USE SIGNAL ;
    PORT
      LAYER M4 ;
        RECT  21.516 55.536 21.6 55.56 ;
    END
  END q[267]
  PIN q[268]
    DIRECTION OUTPUT ;
    USE SIGNAL ;
    PORT
      LAYER M4 ;
        RECT  21.516 55.632 21.6 55.656 ;
    END
  END q[268]
  PIN q[269]
    DIRECTION OUTPUT ;
    USE SIGNAL ;
    PORT
      LAYER M4 ;
        RECT  21.516 55.728 21.6 55.752 ;
    END
  END q[269]
  PIN q[26]
    DIRECTION OUTPUT ;
    USE SIGNAL ;
    PORT
      LAYER M4 ;
        RECT  21.516 28.56 21.6 28.584 ;
    END
  END q[26]
  PIN q[270]
    DIRECTION OUTPUT ;
    USE SIGNAL ;
    PORT
      LAYER M4 ;
        RECT  21.516 55.824 21.6 55.848 ;
    END
  END q[270]
  PIN q[271]
    DIRECTION OUTPUT ;
    USE SIGNAL ;
    PORT
      LAYER M4 ;
        RECT  21.516 55.92 21.6 55.944 ;
    END
  END q[271]
  PIN q[272]
    DIRECTION OUTPUT ;
    USE SIGNAL ;
    PORT
      LAYER M4 ;
        RECT  21.516 56.016 21.6 56.04 ;
    END
  END q[272]
  PIN q[273]
    DIRECTION OUTPUT ;
    USE SIGNAL ;
    PORT
      LAYER M4 ;
        RECT  21.516 56.112 21.6 56.136 ;
    END
  END q[273]
  PIN q[274]
    DIRECTION OUTPUT ;
    USE SIGNAL ;
    PORT
      LAYER M4 ;
        RECT  21.516 56.208 21.6 56.232 ;
    END
  END q[274]
  PIN q[275]
    DIRECTION OUTPUT ;
    USE SIGNAL ;
    PORT
      LAYER M4 ;
        RECT  21.516 56.304 21.6 56.328 ;
    END
  END q[275]
  PIN q[276]
    DIRECTION OUTPUT ;
    USE SIGNAL ;
    PORT
      LAYER M4 ;
        RECT  21.516 56.4 21.6 56.424 ;
    END
  END q[276]
  PIN q[277]
    DIRECTION OUTPUT ;
    USE SIGNAL ;
    PORT
      LAYER M4 ;
        RECT  21.516 56.496 21.6 56.52 ;
    END
  END q[277]
  PIN q[278]
    DIRECTION OUTPUT ;
    USE SIGNAL ;
    PORT
      LAYER M4 ;
        RECT  21.516 56.592 21.6 56.616 ;
    END
  END q[278]
  PIN q[279]
    DIRECTION OUTPUT ;
    USE SIGNAL ;
    PORT
      LAYER M4 ;
        RECT  21.516 56.688 21.6 56.712 ;
    END
  END q[279]
  PIN q[27]
    DIRECTION OUTPUT ;
    USE SIGNAL ;
    PORT
      LAYER M4 ;
        RECT  21.516 28.656 21.6 28.68 ;
    END
  END q[27]
  PIN q[280]
    DIRECTION OUTPUT ;
    USE SIGNAL ;
    PORT
      LAYER M4 ;
        RECT  21.516 56.784 21.6 56.808 ;
    END
  END q[280]
  PIN q[281]
    DIRECTION OUTPUT ;
    USE SIGNAL ;
    PORT
      LAYER M4 ;
        RECT  21.516 56.88 21.6 56.904 ;
    END
  END q[281]
  PIN q[282]
    DIRECTION OUTPUT ;
    USE SIGNAL ;
    PORT
      LAYER M4 ;
        RECT  21.516 56.976 21.6 57 ;
    END
  END q[282]
  PIN q[283]
    DIRECTION OUTPUT ;
    USE SIGNAL ;
    PORT
      LAYER M4 ;
        RECT  21.516 57.072 21.6 57.096 ;
    END
  END q[283]
  PIN q[284]
    DIRECTION OUTPUT ;
    USE SIGNAL ;
    PORT
      LAYER M4 ;
        RECT  21.516 57.168 21.6 57.192 ;
    END
  END q[284]
  PIN q[285]
    DIRECTION OUTPUT ;
    USE SIGNAL ;
    PORT
      LAYER M4 ;
        RECT  21.516 57.264 21.6 57.288 ;
    END
  END q[285]
  PIN q[286]
    DIRECTION OUTPUT ;
    USE SIGNAL ;
    PORT
      LAYER M4 ;
        RECT  21.516 57.36 21.6 57.384 ;
    END
  END q[286]
  PIN q[287]
    DIRECTION OUTPUT ;
    USE SIGNAL ;
    PORT
      LAYER M4 ;
        RECT  21.516 57.456 21.6 57.48 ;
    END
  END q[287]
  PIN q[288]
    DIRECTION OUTPUT ;
    USE SIGNAL ;
    PORT
      LAYER M4 ;
        RECT  21.516 45.264 21.6 45.288 ;
    END
  END q[288]
  PIN q[289]
    DIRECTION OUTPUT ;
    USE SIGNAL ;
    PORT
      LAYER M4 ;
        RECT  21.516 45.36 21.6 45.384 ;
    END
  END q[289]
  PIN q[28]
    DIRECTION OUTPUT ;
    USE SIGNAL ;
    PORT
      LAYER M4 ;
        RECT  21.516 28.752 21.6 28.776 ;
    END
  END q[28]
  PIN q[290]
    DIRECTION OUTPUT ;
    USE SIGNAL ;
    PORT
      LAYER M4 ;
        RECT  21.516 45.456 21.6 45.48 ;
    END
  END q[290]
  PIN q[291]
    DIRECTION OUTPUT ;
    USE SIGNAL ;
    PORT
      LAYER M4 ;
        RECT  21.516 45.552 21.6 45.576 ;
    END
  END q[291]
  PIN q[292]
    DIRECTION OUTPUT ;
    USE SIGNAL ;
    PORT
      LAYER M4 ;
        RECT  21.516 45.648 21.6 45.672 ;
    END
  END q[292]
  PIN q[293]
    DIRECTION OUTPUT ;
    USE SIGNAL ;
    PORT
      LAYER M4 ;
        RECT  21.516 45.744 21.6 45.768 ;
    END
  END q[293]
  PIN q[294]
    DIRECTION OUTPUT ;
    USE SIGNAL ;
    PORT
      LAYER M4 ;
        RECT  21.516 45.84 21.6 45.864 ;
    END
  END q[294]
  PIN q[295]
    DIRECTION OUTPUT ;
    USE SIGNAL ;
    PORT
      LAYER M4 ;
        RECT  21.516 45.936 21.6 45.96 ;
    END
  END q[295]
  PIN q[296]
    DIRECTION OUTPUT ;
    USE SIGNAL ;
    PORT
      LAYER M4 ;
        RECT  21.516 46.032 21.6 46.056 ;
    END
  END q[296]
  PIN q[297]
    DIRECTION OUTPUT ;
    USE SIGNAL ;
    PORT
      LAYER M4 ;
        RECT  21.516 46.128 21.6 46.152 ;
    END
  END q[297]
  PIN q[298]
    DIRECTION OUTPUT ;
    USE SIGNAL ;
    PORT
      LAYER M4 ;
        RECT  21.516 46.224 21.6 46.248 ;
    END
  END q[298]
  PIN q[299]
    DIRECTION OUTPUT ;
    USE SIGNAL ;
    PORT
      LAYER M4 ;
        RECT  21.516 46.32 21.6 46.344 ;
    END
  END q[299]
  PIN q[29]
    DIRECTION OUTPUT ;
    USE SIGNAL ;
    PORT
      LAYER M4 ;
        RECT  21.516 28.848 21.6 28.872 ;
    END
  END q[29]
  PIN q[2]
    DIRECTION OUTPUT ;
    USE SIGNAL ;
    PORT
      LAYER M4 ;
        RECT  21.516 26.256 21.6 26.28 ;
    END
  END q[2]
  PIN q[300]
    DIRECTION OUTPUT ;
    USE SIGNAL ;
    PORT
      LAYER M4 ;
        RECT  21.516 46.416 21.6 46.44 ;
    END
  END q[300]
  PIN q[301]
    DIRECTION OUTPUT ;
    USE SIGNAL ;
    PORT
      LAYER M4 ;
        RECT  21.516 46.512 21.6 46.536 ;
    END
  END q[301]
  PIN q[302]
    DIRECTION OUTPUT ;
    USE SIGNAL ;
    PORT
      LAYER M4 ;
        RECT  21.516 46.608 21.6 46.632 ;
    END
  END q[302]
  PIN q[303]
    DIRECTION OUTPUT ;
    USE SIGNAL ;
    PORT
      LAYER M4 ;
        RECT  21.516 46.704 21.6 46.728 ;
    END
  END q[303]
  PIN q[304]
    DIRECTION OUTPUT ;
    USE SIGNAL ;
    PORT
      LAYER M4 ;
        RECT  21.516 46.8 21.6 46.824 ;
    END
  END q[304]
  PIN q[305]
    DIRECTION OUTPUT ;
    USE SIGNAL ;
    PORT
      LAYER M4 ;
        RECT  21.516 46.896 21.6 46.92 ;
    END
  END q[305]
  PIN q[306]
    DIRECTION OUTPUT ;
    USE SIGNAL ;
    PORT
      LAYER M4 ;
        RECT  21.516 46.992 21.6 47.016 ;
    END
  END q[306]
  PIN q[307]
    DIRECTION OUTPUT ;
    USE SIGNAL ;
    PORT
      LAYER M4 ;
        RECT  21.516 47.088 21.6 47.112 ;
    END
  END q[307]
  PIN q[308]
    DIRECTION OUTPUT ;
    USE SIGNAL ;
    PORT
      LAYER M4 ;
        RECT  21.516 47.184 21.6 47.208 ;
    END
  END q[308]
  PIN q[309]
    DIRECTION OUTPUT ;
    USE SIGNAL ;
    PORT
      LAYER M4 ;
        RECT  21.516 47.28 21.6 47.304 ;
    END
  END q[309]
  PIN q[30]
    DIRECTION OUTPUT ;
    USE SIGNAL ;
    PORT
      LAYER M4 ;
        RECT  21.516 28.944 21.6 28.968 ;
    END
  END q[30]
  PIN q[310]
    DIRECTION OUTPUT ;
    USE SIGNAL ;
    PORT
      LAYER M4 ;
        RECT  21.516 47.376 21.6 47.4 ;
    END
  END q[310]
  PIN q[311]
    DIRECTION OUTPUT ;
    USE SIGNAL ;
    PORT
      LAYER M4 ;
        RECT  21.516 47.472 21.6 47.496 ;
    END
  END q[311]
  PIN q[312]
    DIRECTION OUTPUT ;
    USE SIGNAL ;
    PORT
      LAYER M4 ;
        RECT  21.516 47.568 21.6 47.592 ;
    END
  END q[312]
  PIN q[313]
    DIRECTION OUTPUT ;
    USE SIGNAL ;
    PORT
      LAYER M4 ;
        RECT  21.516 47.664 21.6 47.688 ;
    END
  END q[313]
  PIN q[314]
    DIRECTION OUTPUT ;
    USE SIGNAL ;
    PORT
      LAYER M4 ;
        RECT  21.516 47.76 21.6 47.784 ;
    END
  END q[314]
  PIN q[315]
    DIRECTION OUTPUT ;
    USE SIGNAL ;
    PORT
      LAYER M4 ;
        RECT  21.516 47.856 21.6 47.88 ;
    END
  END q[315]
  PIN q[316]
    DIRECTION OUTPUT ;
    USE SIGNAL ;
    PORT
      LAYER M4 ;
        RECT  21.516 47.952 21.6 47.976 ;
    END
  END q[316]
  PIN q[317]
    DIRECTION OUTPUT ;
    USE SIGNAL ;
    PORT
      LAYER M4 ;
        RECT  21.516 48.048 21.6 48.072 ;
    END
  END q[317]
  PIN q[318]
    DIRECTION OUTPUT ;
    USE SIGNAL ;
    PORT
      LAYER M4 ;
        RECT  21.516 48.144 21.6 48.168 ;
    END
  END q[318]
  PIN q[319]
    DIRECTION OUTPUT ;
    USE SIGNAL ;
    PORT
      LAYER M4 ;
        RECT  21.516 48.24 21.6 48.264 ;
    END
  END q[319]
  PIN q[31]
    DIRECTION OUTPUT ;
    USE SIGNAL ;
    PORT
      LAYER M4 ;
        RECT  21.516 29.04 21.6 29.064 ;
    END
  END q[31]
  PIN q[320]
    DIRECTION OUTPUT ;
    USE SIGNAL ;
    PORT
      LAYER M4 ;
        RECT  21.516 39.12 21.6 39.144 ;
    END
  END q[320]
  PIN q[321]
    DIRECTION OUTPUT ;
    USE SIGNAL ;
    PORT
      LAYER M4 ;
        RECT  21.516 39.216 21.6 39.24 ;
    END
  END q[321]
  PIN q[322]
    DIRECTION OUTPUT ;
    USE SIGNAL ;
    PORT
      LAYER M4 ;
        RECT  21.516 39.312 21.6 39.336 ;
    END
  END q[322]
  PIN q[323]
    DIRECTION OUTPUT ;
    USE SIGNAL ;
    PORT
      LAYER M4 ;
        RECT  21.516 39.408 21.6 39.432 ;
    END
  END q[323]
  PIN q[324]
    DIRECTION OUTPUT ;
    USE SIGNAL ;
    PORT
      LAYER M4 ;
        RECT  21.516 39.504 21.6 39.528 ;
    END
  END q[324]
  PIN q[325]
    DIRECTION OUTPUT ;
    USE SIGNAL ;
    PORT
      LAYER M4 ;
        RECT  21.516 39.6 21.6 39.624 ;
    END
  END q[325]
  PIN q[326]
    DIRECTION OUTPUT ;
    USE SIGNAL ;
    PORT
      LAYER M4 ;
        RECT  21.516 39.696 21.6 39.72 ;
    END
  END q[326]
  PIN q[327]
    DIRECTION OUTPUT ;
    USE SIGNAL ;
    PORT
      LAYER M4 ;
        RECT  21.516 39.792 21.6 39.816 ;
    END
  END q[327]
  PIN q[328]
    DIRECTION OUTPUT ;
    USE SIGNAL ;
    PORT
      LAYER M4 ;
        RECT  21.516 39.888 21.6 39.912 ;
    END
  END q[328]
  PIN q[329]
    DIRECTION OUTPUT ;
    USE SIGNAL ;
    PORT
      LAYER M4 ;
        RECT  21.516 39.984 21.6 40.008 ;
    END
  END q[329]
  PIN q[32]
    DIRECTION OUTPUT ;
    USE SIGNAL ;
    PORT
      LAYER M4 ;
        RECT  21.516 32.208 21.6 32.232 ;
    END
  END q[32]
  PIN q[330]
    DIRECTION OUTPUT ;
    USE SIGNAL ;
    PORT
      LAYER M4 ;
        RECT  21.516 40.08 21.6 40.104 ;
    END
  END q[330]
  PIN q[331]
    DIRECTION OUTPUT ;
    USE SIGNAL ;
    PORT
      LAYER M4 ;
        RECT  21.516 40.176 21.6 40.2 ;
    END
  END q[331]
  PIN q[332]
    DIRECTION OUTPUT ;
    USE SIGNAL ;
    PORT
      LAYER M4 ;
        RECT  21.516 40.272 21.6 40.296 ;
    END
  END q[332]
  PIN q[333]
    DIRECTION OUTPUT ;
    USE SIGNAL ;
    PORT
      LAYER M4 ;
        RECT  21.516 40.368 21.6 40.392 ;
    END
  END q[333]
  PIN q[334]
    DIRECTION OUTPUT ;
    USE SIGNAL ;
    PORT
      LAYER M4 ;
        RECT  21.516 40.464 21.6 40.488 ;
    END
  END q[334]
  PIN q[335]
    DIRECTION OUTPUT ;
    USE SIGNAL ;
    PORT
      LAYER M4 ;
        RECT  21.516 40.56 21.6 40.584 ;
    END
  END q[335]
  PIN q[336]
    DIRECTION OUTPUT ;
    USE SIGNAL ;
    PORT
      LAYER M4 ;
        RECT  21.516 40.656 21.6 40.68 ;
    END
  END q[336]
  PIN q[337]
    DIRECTION OUTPUT ;
    USE SIGNAL ;
    PORT
      LAYER M4 ;
        RECT  21.516 40.752 21.6 40.776 ;
    END
  END q[337]
  PIN q[338]
    DIRECTION OUTPUT ;
    USE SIGNAL ;
    PORT
      LAYER M4 ;
        RECT  21.516 40.848 21.6 40.872 ;
    END
  END q[338]
  PIN q[339]
    DIRECTION OUTPUT ;
    USE SIGNAL ;
    PORT
      LAYER M4 ;
        RECT  21.516 40.944 21.6 40.968 ;
    END
  END q[339]
  PIN q[33]
    DIRECTION OUTPUT ;
    USE SIGNAL ;
    PORT
      LAYER M4 ;
        RECT  21.516 32.304 21.6 32.328 ;
    END
  END q[33]
  PIN q[340]
    DIRECTION OUTPUT ;
    USE SIGNAL ;
    PORT
      LAYER M4 ;
        RECT  21.516 41.04 21.6 41.064 ;
    END
  END q[340]
  PIN q[341]
    DIRECTION OUTPUT ;
    USE SIGNAL ;
    PORT
      LAYER M4 ;
        RECT  21.516 41.136 21.6 41.16 ;
    END
  END q[341]
  PIN q[342]
    DIRECTION OUTPUT ;
    USE SIGNAL ;
    PORT
      LAYER M4 ;
        RECT  21.516 41.232 21.6 41.256 ;
    END
  END q[342]
  PIN q[343]
    DIRECTION OUTPUT ;
    USE SIGNAL ;
    PORT
      LAYER M4 ;
        RECT  21.516 41.328 21.6 41.352 ;
    END
  END q[343]
  PIN q[344]
    DIRECTION OUTPUT ;
    USE SIGNAL ;
    PORT
      LAYER M4 ;
        RECT  21.516 41.424 21.6 41.448 ;
    END
  END q[344]
  PIN q[345]
    DIRECTION OUTPUT ;
    USE SIGNAL ;
    PORT
      LAYER M4 ;
        RECT  21.516 41.52 21.6 41.544 ;
    END
  END q[345]
  PIN q[346]
    DIRECTION OUTPUT ;
    USE SIGNAL ;
    PORT
      LAYER M4 ;
        RECT  21.516 41.616 21.6 41.64 ;
    END
  END q[346]
  PIN q[347]
    DIRECTION OUTPUT ;
    USE SIGNAL ;
    PORT
      LAYER M4 ;
        RECT  21.516 41.712 21.6 41.736 ;
    END
  END q[347]
  PIN q[348]
    DIRECTION OUTPUT ;
    USE SIGNAL ;
    PORT
      LAYER M4 ;
        RECT  21.516 41.808 21.6 41.832 ;
    END
  END q[348]
  PIN q[349]
    DIRECTION OUTPUT ;
    USE SIGNAL ;
    PORT
      LAYER M4 ;
        RECT  21.516 41.904 21.6 41.928 ;
    END
  END q[349]
  PIN q[34]
    DIRECTION OUTPUT ;
    USE SIGNAL ;
    PORT
      LAYER M4 ;
        RECT  21.516 32.4 21.6 32.424 ;
    END
  END q[34]
  PIN q[350]
    DIRECTION OUTPUT ;
    USE SIGNAL ;
    PORT
      LAYER M4 ;
        RECT  21.516 42 21.6 42.024 ;
    END
  END q[350]
  PIN q[351]
    DIRECTION OUTPUT ;
    USE SIGNAL ;
    PORT
      LAYER M4 ;
        RECT  21.516 42.096 21.6 42.12 ;
    END
  END q[351]
  PIN q[352]
    DIRECTION OUTPUT ;
    USE SIGNAL ;
    PORT
      LAYER M4 ;
        RECT  21.516 48.336 21.6 48.36 ;
    END
  END q[352]
  PIN q[353]
    DIRECTION OUTPUT ;
    USE SIGNAL ;
    PORT
      LAYER M4 ;
        RECT  21.516 48.432 21.6 48.456 ;
    END
  END q[353]
  PIN q[354]
    DIRECTION OUTPUT ;
    USE SIGNAL ;
    PORT
      LAYER M4 ;
        RECT  21.516 48.528 21.6 48.552 ;
    END
  END q[354]
  PIN q[355]
    DIRECTION OUTPUT ;
    USE SIGNAL ;
    PORT
      LAYER M4 ;
        RECT  21.516 48.624 21.6 48.648 ;
    END
  END q[355]
  PIN q[356]
    DIRECTION OUTPUT ;
    USE SIGNAL ;
    PORT
      LAYER M4 ;
        RECT  21.516 48.72 21.6 48.744 ;
    END
  END q[356]
  PIN q[357]
    DIRECTION OUTPUT ;
    USE SIGNAL ;
    PORT
      LAYER M4 ;
        RECT  21.516 48.816 21.6 48.84 ;
    END
  END q[357]
  PIN q[358]
    DIRECTION OUTPUT ;
    USE SIGNAL ;
    PORT
      LAYER M4 ;
        RECT  21.516 48.912 21.6 48.936 ;
    END
  END q[358]
  PIN q[359]
    DIRECTION OUTPUT ;
    USE SIGNAL ;
    PORT
      LAYER M4 ;
        RECT  21.516 49.008 21.6 49.032 ;
    END
  END q[359]
  PIN q[35]
    DIRECTION OUTPUT ;
    USE SIGNAL ;
    PORT
      LAYER M4 ;
        RECT  21.516 32.496 21.6 32.52 ;
    END
  END q[35]
  PIN q[360]
    DIRECTION OUTPUT ;
    USE SIGNAL ;
    PORT
      LAYER M4 ;
        RECT  21.516 49.104 21.6 49.128 ;
    END
  END q[360]
  PIN q[361]
    DIRECTION OUTPUT ;
    USE SIGNAL ;
    PORT
      LAYER M4 ;
        RECT  21.516 49.2 21.6 49.224 ;
    END
  END q[361]
  PIN q[362]
    DIRECTION OUTPUT ;
    USE SIGNAL ;
    PORT
      LAYER M4 ;
        RECT  21.516 49.296 21.6 49.32 ;
    END
  END q[362]
  PIN q[363]
    DIRECTION OUTPUT ;
    USE SIGNAL ;
    PORT
      LAYER M4 ;
        RECT  21.516 49.392 21.6 49.416 ;
    END
  END q[363]
  PIN q[364]
    DIRECTION OUTPUT ;
    USE SIGNAL ;
    PORT
      LAYER M4 ;
        RECT  21.516 49.488 21.6 49.512 ;
    END
  END q[364]
  PIN q[365]
    DIRECTION OUTPUT ;
    USE SIGNAL ;
    PORT
      LAYER M4 ;
        RECT  21.516 49.584 21.6 49.608 ;
    END
  END q[365]
  PIN q[366]
    DIRECTION OUTPUT ;
    USE SIGNAL ;
    PORT
      LAYER M4 ;
        RECT  21.516 49.68 21.6 49.704 ;
    END
  END q[366]
  PIN q[367]
    DIRECTION OUTPUT ;
    USE SIGNAL ;
    PORT
      LAYER M4 ;
        RECT  21.516 49.776 21.6 49.8 ;
    END
  END q[367]
  PIN q[368]
    DIRECTION OUTPUT ;
    USE SIGNAL ;
    PORT
      LAYER M4 ;
        RECT  21.516 49.872 21.6 49.896 ;
    END
  END q[368]
  PIN q[369]
    DIRECTION OUTPUT ;
    USE SIGNAL ;
    PORT
      LAYER M4 ;
        RECT  21.516 49.968 21.6 49.992 ;
    END
  END q[369]
  PIN q[36]
    DIRECTION OUTPUT ;
    USE SIGNAL ;
    PORT
      LAYER M4 ;
        RECT  21.516 32.592 21.6 32.616 ;
    END
  END q[36]
  PIN q[370]
    DIRECTION OUTPUT ;
    USE SIGNAL ;
    PORT
      LAYER M4 ;
        RECT  21.516 50.064 21.6 50.088 ;
    END
  END q[370]
  PIN q[371]
    DIRECTION OUTPUT ;
    USE SIGNAL ;
    PORT
      LAYER M4 ;
        RECT  21.516 50.16 21.6 50.184 ;
    END
  END q[371]
  PIN q[372]
    DIRECTION OUTPUT ;
    USE SIGNAL ;
    PORT
      LAYER M4 ;
        RECT  21.516 50.256 21.6 50.28 ;
    END
  END q[372]
  PIN q[373]
    DIRECTION OUTPUT ;
    USE SIGNAL ;
    PORT
      LAYER M4 ;
        RECT  21.516 50.352 21.6 50.376 ;
    END
  END q[373]
  PIN q[374]
    DIRECTION OUTPUT ;
    USE SIGNAL ;
    PORT
      LAYER M4 ;
        RECT  21.516 50.448 21.6 50.472 ;
    END
  END q[374]
  PIN q[375]
    DIRECTION OUTPUT ;
    USE SIGNAL ;
    PORT
      LAYER M4 ;
        RECT  21.516 50.544 21.6 50.568 ;
    END
  END q[375]
  PIN q[376]
    DIRECTION OUTPUT ;
    USE SIGNAL ;
    PORT
      LAYER M4 ;
        RECT  21.516 50.64 21.6 50.664 ;
    END
  END q[376]
  PIN q[377]
    DIRECTION OUTPUT ;
    USE SIGNAL ;
    PORT
      LAYER M4 ;
        RECT  21.516 50.736 21.6 50.76 ;
    END
  END q[377]
  PIN q[378]
    DIRECTION OUTPUT ;
    USE SIGNAL ;
    PORT
      LAYER M4 ;
        RECT  21.516 50.832 21.6 50.856 ;
    END
  END q[378]
  PIN q[379]
    DIRECTION OUTPUT ;
    USE SIGNAL ;
    PORT
      LAYER M4 ;
        RECT  21.516 50.928 21.6 50.952 ;
    END
  END q[379]
  PIN q[37]
    DIRECTION OUTPUT ;
    USE SIGNAL ;
    PORT
      LAYER M4 ;
        RECT  21.516 32.688 21.6 32.712 ;
    END
  END q[37]
  PIN q[380]
    DIRECTION OUTPUT ;
    USE SIGNAL ;
    PORT
      LAYER M4 ;
        RECT  21.516 51.024 21.6 51.048 ;
    END
  END q[380]
  PIN q[381]
    DIRECTION OUTPUT ;
    USE SIGNAL ;
    PORT
      LAYER M4 ;
        RECT  21.516 51.12 21.6 51.144 ;
    END
  END q[381]
  PIN q[382]
    DIRECTION OUTPUT ;
    USE SIGNAL ;
    PORT
      LAYER M4 ;
        RECT  21.516 51.216 21.6 51.24 ;
    END
  END q[382]
  PIN q[383]
    DIRECTION OUTPUT ;
    USE SIGNAL ;
    PORT
      LAYER M4 ;
        RECT  21.516 51.312 21.6 51.336 ;
    END
  END q[383]
  PIN q[384]
    DIRECTION OUTPUT ;
    USE SIGNAL ;
    PORT
      LAYER M4 ;
        RECT  21.516 6.864 21.6 6.888 ;
    END
  END q[384]
  PIN q[385]
    DIRECTION OUTPUT ;
    USE SIGNAL ;
    PORT
      LAYER M4 ;
        RECT  21.516 6.96 21.6 6.984 ;
    END
  END q[385]
  PIN q[386]
    DIRECTION OUTPUT ;
    USE SIGNAL ;
    PORT
      LAYER M4 ;
        RECT  21.516 7.056 21.6 7.08 ;
    END
  END q[386]
  PIN q[387]
    DIRECTION OUTPUT ;
    USE SIGNAL ;
    PORT
      LAYER M4 ;
        RECT  21.516 7.152 21.6 7.176 ;
    END
  END q[387]
  PIN q[388]
    DIRECTION OUTPUT ;
    USE SIGNAL ;
    PORT
      LAYER M4 ;
        RECT  21.516 7.248 21.6 7.272 ;
    END
  END q[388]
  PIN q[389]
    DIRECTION OUTPUT ;
    USE SIGNAL ;
    PORT
      LAYER M4 ;
        RECT  21.516 7.344 21.6 7.368 ;
    END
  END q[389]
  PIN q[38]
    DIRECTION OUTPUT ;
    USE SIGNAL ;
    PORT
      LAYER M4 ;
        RECT  21.516 32.784 21.6 32.808 ;
    END
  END q[38]
  PIN q[390]
    DIRECTION OUTPUT ;
    USE SIGNAL ;
    PORT
      LAYER M4 ;
        RECT  21.516 7.44 21.6 7.464 ;
    END
  END q[390]
  PIN q[391]
    DIRECTION OUTPUT ;
    USE SIGNAL ;
    PORT
      LAYER M4 ;
        RECT  21.516 7.536 21.6 7.56 ;
    END
  END q[391]
  PIN q[392]
    DIRECTION OUTPUT ;
    USE SIGNAL ;
    PORT
      LAYER M4 ;
        RECT  21.516 7.632 21.6 7.656 ;
    END
  END q[392]
  PIN q[393]
    DIRECTION OUTPUT ;
    USE SIGNAL ;
    PORT
      LAYER M4 ;
        RECT  21.516 7.728 21.6 7.752 ;
    END
  END q[393]
  PIN q[394]
    DIRECTION OUTPUT ;
    USE SIGNAL ;
    PORT
      LAYER M4 ;
        RECT  21.516 7.824 21.6 7.848 ;
    END
  END q[394]
  PIN q[395]
    DIRECTION OUTPUT ;
    USE SIGNAL ;
    PORT
      LAYER M4 ;
        RECT  21.516 7.92 21.6 7.944 ;
    END
  END q[395]
  PIN q[396]
    DIRECTION OUTPUT ;
    USE SIGNAL ;
    PORT
      LAYER M4 ;
        RECT  21.516 8.016 21.6 8.04 ;
    END
  END q[396]
  PIN q[397]
    DIRECTION OUTPUT ;
    USE SIGNAL ;
    PORT
      LAYER M4 ;
        RECT  21.516 8.112 21.6 8.136 ;
    END
  END q[397]
  PIN q[398]
    DIRECTION OUTPUT ;
    USE SIGNAL ;
    PORT
      LAYER M4 ;
        RECT  21.516 8.208 21.6 8.232 ;
    END
  END q[398]
  PIN q[399]
    DIRECTION OUTPUT ;
    USE SIGNAL ;
    PORT
      LAYER M4 ;
        RECT  21.516 8.304 21.6 8.328 ;
    END
  END q[399]
  PIN q[39]
    DIRECTION OUTPUT ;
    USE SIGNAL ;
    PORT
      LAYER M4 ;
        RECT  21.516 32.88 21.6 32.904 ;
    END
  END q[39]
  PIN q[3]
    DIRECTION OUTPUT ;
    USE SIGNAL ;
    PORT
      LAYER M4 ;
        RECT  21.516 26.352 21.6 26.376 ;
    END
  END q[3]
  PIN q[400]
    DIRECTION OUTPUT ;
    USE SIGNAL ;
    PORT
      LAYER M4 ;
        RECT  21.516 8.4 21.6 8.424 ;
    END
  END q[400]
  PIN q[401]
    DIRECTION OUTPUT ;
    USE SIGNAL ;
    PORT
      LAYER M4 ;
        RECT  21.516 8.496 21.6 8.52 ;
    END
  END q[401]
  PIN q[402]
    DIRECTION OUTPUT ;
    USE SIGNAL ;
    PORT
      LAYER M4 ;
        RECT  21.516 8.592 21.6 8.616 ;
    END
  END q[402]
  PIN q[403]
    DIRECTION OUTPUT ;
    USE SIGNAL ;
    PORT
      LAYER M4 ;
        RECT  21.516 8.688 21.6 8.712 ;
    END
  END q[403]
  PIN q[404]
    DIRECTION OUTPUT ;
    USE SIGNAL ;
    PORT
      LAYER M4 ;
        RECT  21.516 8.784 21.6 8.808 ;
    END
  END q[404]
  PIN q[405]
    DIRECTION OUTPUT ;
    USE SIGNAL ;
    PORT
      LAYER M4 ;
        RECT  21.516 8.88 21.6 8.904 ;
    END
  END q[405]
  PIN q[406]
    DIRECTION OUTPUT ;
    USE SIGNAL ;
    PORT
      LAYER M4 ;
        RECT  21.516 8.976 21.6 9 ;
    END
  END q[406]
  PIN q[407]
    DIRECTION OUTPUT ;
    USE SIGNAL ;
    PORT
      LAYER M4 ;
        RECT  21.516 9.072 21.6 9.096 ;
    END
  END q[407]
  PIN q[408]
    DIRECTION OUTPUT ;
    USE SIGNAL ;
    PORT
      LAYER M4 ;
        RECT  21.516 9.168 21.6 9.192 ;
    END
  END q[408]
  PIN q[409]
    DIRECTION OUTPUT ;
    USE SIGNAL ;
    PORT
      LAYER M4 ;
        RECT  21.516 9.264 21.6 9.288 ;
    END
  END q[409]
  PIN q[40]
    DIRECTION OUTPUT ;
    USE SIGNAL ;
    PORT
      LAYER M4 ;
        RECT  21.516 32.976 21.6 33 ;
    END
  END q[40]
  PIN q[410]
    DIRECTION OUTPUT ;
    USE SIGNAL ;
    PORT
      LAYER M4 ;
        RECT  21.516 9.36 21.6 9.384 ;
    END
  END q[410]
  PIN q[411]
    DIRECTION OUTPUT ;
    USE SIGNAL ;
    PORT
      LAYER M4 ;
        RECT  21.516 9.456 21.6 9.48 ;
    END
  END q[411]
  PIN q[412]
    DIRECTION OUTPUT ;
    USE SIGNAL ;
    PORT
      LAYER M4 ;
        RECT  21.516 9.552 21.6 9.576 ;
    END
  END q[412]
  PIN q[413]
    DIRECTION OUTPUT ;
    USE SIGNAL ;
    PORT
      LAYER M4 ;
        RECT  21.516 9.648 21.6 9.672 ;
    END
  END q[413]
  PIN q[414]
    DIRECTION OUTPUT ;
    USE SIGNAL ;
    PORT
      LAYER M4 ;
        RECT  21.516 9.744 21.6 9.768 ;
    END
  END q[414]
  PIN q[415]
    DIRECTION OUTPUT ;
    USE SIGNAL ;
    PORT
      LAYER M4 ;
        RECT  21.516 9.84 21.6 9.864 ;
    END
  END q[415]
  PIN q[416]
    DIRECTION OUTPUT ;
    USE SIGNAL ;
    PORT
      LAYER M4 ;
        RECT  21.516 9.936 21.6 9.96 ;
    END
  END q[416]
  PIN q[417]
    DIRECTION OUTPUT ;
    USE SIGNAL ;
    PORT
      LAYER M4 ;
        RECT  21.516 10.032 21.6 10.056 ;
    END
  END q[417]
  PIN q[418]
    DIRECTION OUTPUT ;
    USE SIGNAL ;
    PORT
      LAYER M4 ;
        RECT  21.516 10.128 21.6 10.152 ;
    END
  END q[418]
  PIN q[419]
    DIRECTION OUTPUT ;
    USE SIGNAL ;
    PORT
      LAYER M4 ;
        RECT  21.516 10.224 21.6 10.248 ;
    END
  END q[419]
  PIN q[41]
    DIRECTION OUTPUT ;
    USE SIGNAL ;
    PORT
      LAYER M4 ;
        RECT  21.516 33.072 21.6 33.096 ;
    END
  END q[41]
  PIN q[420]
    DIRECTION OUTPUT ;
    USE SIGNAL ;
    PORT
      LAYER M4 ;
        RECT  21.516 10.32 21.6 10.344 ;
    END
  END q[420]
  PIN q[421]
    DIRECTION OUTPUT ;
    USE SIGNAL ;
    PORT
      LAYER M4 ;
        RECT  21.516 10.416 21.6 10.44 ;
    END
  END q[421]
  PIN q[422]
    DIRECTION OUTPUT ;
    USE SIGNAL ;
    PORT
      LAYER M4 ;
        RECT  21.516 10.512 21.6 10.536 ;
    END
  END q[422]
  PIN q[423]
    DIRECTION OUTPUT ;
    USE SIGNAL ;
    PORT
      LAYER M4 ;
        RECT  21.516 10.608 21.6 10.632 ;
    END
  END q[423]
  PIN q[424]
    DIRECTION OUTPUT ;
    USE SIGNAL ;
    PORT
      LAYER M4 ;
        RECT  21.516 10.704 21.6 10.728 ;
    END
  END q[424]
  PIN q[425]
    DIRECTION OUTPUT ;
    USE SIGNAL ;
    PORT
      LAYER M4 ;
        RECT  21.516 10.8 21.6 10.824 ;
    END
  END q[425]
  PIN q[426]
    DIRECTION OUTPUT ;
    USE SIGNAL ;
    PORT
      LAYER M4 ;
        RECT  21.516 10.896 21.6 10.92 ;
    END
  END q[426]
  PIN q[427]
    DIRECTION OUTPUT ;
    USE SIGNAL ;
    PORT
      LAYER M4 ;
        RECT  21.516 10.992 21.6 11.016 ;
    END
  END q[427]
  PIN q[428]
    DIRECTION OUTPUT ;
    USE SIGNAL ;
    PORT
      LAYER M4 ;
        RECT  21.516 11.088 21.6 11.112 ;
    END
  END q[428]
  PIN q[429]
    DIRECTION OUTPUT ;
    USE SIGNAL ;
    PORT
      LAYER M4 ;
        RECT  21.516 11.184 21.6 11.208 ;
    END
  END q[429]
  PIN q[42]
    DIRECTION OUTPUT ;
    USE SIGNAL ;
    PORT
      LAYER M4 ;
        RECT  21.516 33.168 21.6 33.192 ;
    END
  END q[42]
  PIN q[430]
    DIRECTION OUTPUT ;
    USE SIGNAL ;
    PORT
      LAYER M4 ;
        RECT  21.516 11.28 21.6 11.304 ;
    END
  END q[430]
  PIN q[431]
    DIRECTION OUTPUT ;
    USE SIGNAL ;
    PORT
      LAYER M4 ;
        RECT  21.516 11.376 21.6 11.4 ;
    END
  END q[431]
  PIN q[432]
    DIRECTION OUTPUT ;
    USE SIGNAL ;
    PORT
      LAYER M4 ;
        RECT  21.516 11.472 21.6 11.496 ;
    END
  END q[432]
  PIN q[433]
    DIRECTION OUTPUT ;
    USE SIGNAL ;
    PORT
      LAYER M4 ;
        RECT  21.516 11.568 21.6 11.592 ;
    END
  END q[433]
  PIN q[434]
    DIRECTION OUTPUT ;
    USE SIGNAL ;
    PORT
      LAYER M4 ;
        RECT  21.516 11.664 21.6 11.688 ;
    END
  END q[434]
  PIN q[435]
    DIRECTION OUTPUT ;
    USE SIGNAL ;
    PORT
      LAYER M4 ;
        RECT  21.516 11.76 21.6 11.784 ;
    END
  END q[435]
  PIN q[436]
    DIRECTION OUTPUT ;
    USE SIGNAL ;
    PORT
      LAYER M4 ;
        RECT  21.516 11.856 21.6 11.88 ;
    END
  END q[436]
  PIN q[437]
    DIRECTION OUTPUT ;
    USE SIGNAL ;
    PORT
      LAYER M4 ;
        RECT  21.516 11.952 21.6 11.976 ;
    END
  END q[437]
  PIN q[438]
    DIRECTION OUTPUT ;
    USE SIGNAL ;
    PORT
      LAYER M4 ;
        RECT  21.516 12.048 21.6 12.072 ;
    END
  END q[438]
  PIN q[439]
    DIRECTION OUTPUT ;
    USE SIGNAL ;
    PORT
      LAYER M4 ;
        RECT  21.516 12.144 21.6 12.168 ;
    END
  END q[439]
  PIN q[43]
    DIRECTION OUTPUT ;
    USE SIGNAL ;
    PORT
      LAYER M4 ;
        RECT  21.516 33.264 21.6 33.288 ;
    END
  END q[43]
  PIN q[440]
    DIRECTION OUTPUT ;
    USE SIGNAL ;
    PORT
      LAYER M4 ;
        RECT  21.516 12.24 21.6 12.264 ;
    END
  END q[440]
  PIN q[441]
    DIRECTION OUTPUT ;
    USE SIGNAL ;
    PORT
      LAYER M4 ;
        RECT  21.516 12.336 21.6 12.36 ;
    END
  END q[441]
  PIN q[442]
    DIRECTION OUTPUT ;
    USE SIGNAL ;
    PORT
      LAYER M4 ;
        RECT  21.516 12.432 21.6 12.456 ;
    END
  END q[442]
  PIN q[443]
    DIRECTION OUTPUT ;
    USE SIGNAL ;
    PORT
      LAYER M4 ;
        RECT  21.516 12.528 21.6 12.552 ;
    END
  END q[443]
  PIN q[444]
    DIRECTION OUTPUT ;
    USE SIGNAL ;
    PORT
      LAYER M4 ;
        RECT  21.516 12.624 21.6 12.648 ;
    END
  END q[444]
  PIN q[445]
    DIRECTION OUTPUT ;
    USE SIGNAL ;
    PORT
      LAYER M4 ;
        RECT  21.516 12.72 21.6 12.744 ;
    END
  END q[445]
  PIN q[446]
    DIRECTION OUTPUT ;
    USE SIGNAL ;
    PORT
      LAYER M4 ;
        RECT  21.516 12.816 21.6 12.84 ;
    END
  END q[446]
  PIN q[447]
    DIRECTION OUTPUT ;
    USE SIGNAL ;
    PORT
      LAYER M4 ;
        RECT  21.516 12.912 21.6 12.936 ;
    END
  END q[447]
  PIN q[448]
    DIRECTION OUTPUT ;
    USE SIGNAL ;
    PORT
      LAYER M4 ;
        RECT  21.516 16.08 21.6 16.104 ;
    END
  END q[448]
  PIN q[449]
    DIRECTION OUTPUT ;
    USE SIGNAL ;
    PORT
      LAYER M4 ;
        RECT  21.516 16.176 21.6 16.2 ;
    END
  END q[449]
  PIN q[44]
    DIRECTION OUTPUT ;
    USE SIGNAL ;
    PORT
      LAYER M4 ;
        RECT  21.516 33.36 21.6 33.384 ;
    END
  END q[44]
  PIN q[450]
    DIRECTION OUTPUT ;
    USE SIGNAL ;
    PORT
      LAYER M4 ;
        RECT  21.516 16.272 21.6 16.296 ;
    END
  END q[450]
  PIN q[451]
    DIRECTION OUTPUT ;
    USE SIGNAL ;
    PORT
      LAYER M4 ;
        RECT  21.516 16.368 21.6 16.392 ;
    END
  END q[451]
  PIN q[452]
    DIRECTION OUTPUT ;
    USE SIGNAL ;
    PORT
      LAYER M4 ;
        RECT  21.516 16.464 21.6 16.488 ;
    END
  END q[452]
  PIN q[453]
    DIRECTION OUTPUT ;
    USE SIGNAL ;
    PORT
      LAYER M4 ;
        RECT  21.516 16.56 21.6 16.584 ;
    END
  END q[453]
  PIN q[454]
    DIRECTION OUTPUT ;
    USE SIGNAL ;
    PORT
      LAYER M4 ;
        RECT  21.516 16.656 21.6 16.68 ;
    END
  END q[454]
  PIN q[455]
    DIRECTION OUTPUT ;
    USE SIGNAL ;
    PORT
      LAYER M4 ;
        RECT  21.516 16.752 21.6 16.776 ;
    END
  END q[455]
  PIN q[456]
    DIRECTION OUTPUT ;
    USE SIGNAL ;
    PORT
      LAYER M4 ;
        RECT  21.516 16.848 21.6 16.872 ;
    END
  END q[456]
  PIN q[457]
    DIRECTION OUTPUT ;
    USE SIGNAL ;
    PORT
      LAYER M4 ;
        RECT  21.516 16.944 21.6 16.968 ;
    END
  END q[457]
  PIN q[458]
    DIRECTION OUTPUT ;
    USE SIGNAL ;
    PORT
      LAYER M4 ;
        RECT  21.516 17.04 21.6 17.064 ;
    END
  END q[458]
  PIN q[459]
    DIRECTION OUTPUT ;
    USE SIGNAL ;
    PORT
      LAYER M4 ;
        RECT  21.516 17.136 21.6 17.16 ;
    END
  END q[459]
  PIN q[45]
    DIRECTION OUTPUT ;
    USE SIGNAL ;
    PORT
      LAYER M4 ;
        RECT  21.516 33.456 21.6 33.48 ;
    END
  END q[45]
  PIN q[460]
    DIRECTION OUTPUT ;
    USE SIGNAL ;
    PORT
      LAYER M4 ;
        RECT  21.516 17.232 21.6 17.256 ;
    END
  END q[460]
  PIN q[461]
    DIRECTION OUTPUT ;
    USE SIGNAL ;
    PORT
      LAYER M4 ;
        RECT  21.516 17.328 21.6 17.352 ;
    END
  END q[461]
  PIN q[462]
    DIRECTION OUTPUT ;
    USE SIGNAL ;
    PORT
      LAYER M4 ;
        RECT  21.516 17.424 21.6 17.448 ;
    END
  END q[462]
  PIN q[463]
    DIRECTION OUTPUT ;
    USE SIGNAL ;
    PORT
      LAYER M4 ;
        RECT  21.516 17.52 21.6 17.544 ;
    END
  END q[463]
  PIN q[464]
    DIRECTION OUTPUT ;
    USE SIGNAL ;
    PORT
      LAYER M4 ;
        RECT  21.516 17.616 21.6 17.64 ;
    END
  END q[464]
  PIN q[465]
    DIRECTION OUTPUT ;
    USE SIGNAL ;
    PORT
      LAYER M4 ;
        RECT  21.516 17.712 21.6 17.736 ;
    END
  END q[465]
  PIN q[466]
    DIRECTION OUTPUT ;
    USE SIGNAL ;
    PORT
      LAYER M4 ;
        RECT  21.516 17.808 21.6 17.832 ;
    END
  END q[466]
  PIN q[467]
    DIRECTION OUTPUT ;
    USE SIGNAL ;
    PORT
      LAYER M4 ;
        RECT  21.516 17.904 21.6 17.928 ;
    END
  END q[467]
  PIN q[468]
    DIRECTION OUTPUT ;
    USE SIGNAL ;
    PORT
      LAYER M4 ;
        RECT  21.516 18 21.6 18.024 ;
    END
  END q[468]
  PIN q[469]
    DIRECTION OUTPUT ;
    USE SIGNAL ;
    PORT
      LAYER M4 ;
        RECT  21.516 18.096 21.6 18.12 ;
    END
  END q[469]
  PIN q[46]
    DIRECTION OUTPUT ;
    USE SIGNAL ;
    PORT
      LAYER M4 ;
        RECT  21.516 33.552 21.6 33.576 ;
    END
  END q[46]
  PIN q[470]
    DIRECTION OUTPUT ;
    USE SIGNAL ;
    PORT
      LAYER M4 ;
        RECT  21.516 18.192 21.6 18.216 ;
    END
  END q[470]
  PIN q[471]
    DIRECTION OUTPUT ;
    USE SIGNAL ;
    PORT
      LAYER M4 ;
        RECT  21.516 18.288 21.6 18.312 ;
    END
  END q[471]
  PIN q[472]
    DIRECTION OUTPUT ;
    USE SIGNAL ;
    PORT
      LAYER M4 ;
        RECT  21.516 18.384 21.6 18.408 ;
    END
  END q[472]
  PIN q[473]
    DIRECTION OUTPUT ;
    USE SIGNAL ;
    PORT
      LAYER M4 ;
        RECT  21.516 18.48 21.6 18.504 ;
    END
  END q[473]
  PIN q[474]
    DIRECTION OUTPUT ;
    USE SIGNAL ;
    PORT
      LAYER M4 ;
        RECT  21.516 18.576 21.6 18.6 ;
    END
  END q[474]
  PIN q[475]
    DIRECTION OUTPUT ;
    USE SIGNAL ;
    PORT
      LAYER M4 ;
        RECT  21.516 18.672 21.6 18.696 ;
    END
  END q[475]
  PIN q[476]
    DIRECTION OUTPUT ;
    USE SIGNAL ;
    PORT
      LAYER M4 ;
        RECT  21.516 18.768 21.6 18.792 ;
    END
  END q[476]
  PIN q[477]
    DIRECTION OUTPUT ;
    USE SIGNAL ;
    PORT
      LAYER M4 ;
        RECT  21.516 18.864 21.6 18.888 ;
    END
  END q[477]
  PIN q[478]
    DIRECTION OUTPUT ;
    USE SIGNAL ;
    PORT
      LAYER M4 ;
        RECT  21.516 18.96 21.6 18.984 ;
    END
  END q[478]
  PIN q[479]
    DIRECTION OUTPUT ;
    USE SIGNAL ;
    PORT
      LAYER M4 ;
        RECT  21.516 19.056 21.6 19.08 ;
    END
  END q[479]
  PIN q[47]
    DIRECTION OUTPUT ;
    USE SIGNAL ;
    PORT
      LAYER M4 ;
        RECT  21.516 33.648 21.6 33.672 ;
    END
  END q[47]
  PIN q[480]
    DIRECTION OUTPUT ;
    USE SIGNAL ;
    PORT
      LAYER M4 ;
        RECT  21.516 13.008 21.6 13.032 ;
    END
  END q[480]
  PIN q[481]
    DIRECTION OUTPUT ;
    USE SIGNAL ;
    PORT
      LAYER M4 ;
        RECT  21.516 13.104 21.6 13.128 ;
    END
  END q[481]
  PIN q[482]
    DIRECTION OUTPUT ;
    USE SIGNAL ;
    PORT
      LAYER M4 ;
        RECT  21.516 13.2 21.6 13.224 ;
    END
  END q[482]
  PIN q[483]
    DIRECTION OUTPUT ;
    USE SIGNAL ;
    PORT
      LAYER M4 ;
        RECT  21.516 13.296 21.6 13.32 ;
    END
  END q[483]
  PIN q[484]
    DIRECTION OUTPUT ;
    USE SIGNAL ;
    PORT
      LAYER M4 ;
        RECT  21.516 13.392 21.6 13.416 ;
    END
  END q[484]
  PIN q[485]
    DIRECTION OUTPUT ;
    USE SIGNAL ;
    PORT
      LAYER M4 ;
        RECT  21.516 13.488 21.6 13.512 ;
    END
  END q[485]
  PIN q[486]
    DIRECTION OUTPUT ;
    USE SIGNAL ;
    PORT
      LAYER M4 ;
        RECT  21.516 13.584 21.6 13.608 ;
    END
  END q[486]
  PIN q[487]
    DIRECTION OUTPUT ;
    USE SIGNAL ;
    PORT
      LAYER M4 ;
        RECT  21.516 13.68 21.6 13.704 ;
    END
  END q[487]
  PIN q[488]
    DIRECTION OUTPUT ;
    USE SIGNAL ;
    PORT
      LAYER M4 ;
        RECT  21.516 13.776 21.6 13.8 ;
    END
  END q[488]
  PIN q[489]
    DIRECTION OUTPUT ;
    USE SIGNAL ;
    PORT
      LAYER M4 ;
        RECT  21.516 13.872 21.6 13.896 ;
    END
  END q[489]
  PIN q[48]
    DIRECTION OUTPUT ;
    USE SIGNAL ;
    PORT
      LAYER M4 ;
        RECT  21.516 33.744 21.6 33.768 ;
    END
  END q[48]
  PIN q[490]
    DIRECTION OUTPUT ;
    USE SIGNAL ;
    PORT
      LAYER M4 ;
        RECT  21.516 13.968 21.6 13.992 ;
    END
  END q[490]
  PIN q[491]
    DIRECTION OUTPUT ;
    USE SIGNAL ;
    PORT
      LAYER M4 ;
        RECT  21.516 14.064 21.6 14.088 ;
    END
  END q[491]
  PIN q[492]
    DIRECTION OUTPUT ;
    USE SIGNAL ;
    PORT
      LAYER M4 ;
        RECT  21.516 14.16 21.6 14.184 ;
    END
  END q[492]
  PIN q[493]
    DIRECTION OUTPUT ;
    USE SIGNAL ;
    PORT
      LAYER M4 ;
        RECT  21.516 14.256 21.6 14.28 ;
    END
  END q[493]
  PIN q[494]
    DIRECTION OUTPUT ;
    USE SIGNAL ;
    PORT
      LAYER M4 ;
        RECT  21.516 14.352 21.6 14.376 ;
    END
  END q[494]
  PIN q[495]
    DIRECTION OUTPUT ;
    USE SIGNAL ;
    PORT
      LAYER M4 ;
        RECT  21.516 14.448 21.6 14.472 ;
    END
  END q[495]
  PIN q[496]
    DIRECTION OUTPUT ;
    USE SIGNAL ;
    PORT
      LAYER M4 ;
        RECT  21.516 14.544 21.6 14.568 ;
    END
  END q[496]
  PIN q[497]
    DIRECTION OUTPUT ;
    USE SIGNAL ;
    PORT
      LAYER M4 ;
        RECT  21.516 14.64 21.6 14.664 ;
    END
  END q[497]
  PIN q[498]
    DIRECTION OUTPUT ;
    USE SIGNAL ;
    PORT
      LAYER M4 ;
        RECT  21.516 14.736 21.6 14.76 ;
    END
  END q[498]
  PIN q[499]
    DIRECTION OUTPUT ;
    USE SIGNAL ;
    PORT
      LAYER M4 ;
        RECT  21.516 14.832 21.6 14.856 ;
    END
  END q[499]
  PIN q[49]
    DIRECTION OUTPUT ;
    USE SIGNAL ;
    PORT
      LAYER M4 ;
        RECT  21.516 33.84 21.6 33.864 ;
    END
  END q[49]
  PIN q[4]
    DIRECTION OUTPUT ;
    USE SIGNAL ;
    PORT
      LAYER M4 ;
        RECT  21.516 26.448 21.6 26.472 ;
    END
  END q[4]
  PIN q[500]
    DIRECTION OUTPUT ;
    USE SIGNAL ;
    PORT
      LAYER M4 ;
        RECT  21.516 14.928 21.6 14.952 ;
    END
  END q[500]
  PIN q[501]
    DIRECTION OUTPUT ;
    USE SIGNAL ;
    PORT
      LAYER M4 ;
        RECT  21.516 15.024 21.6 15.048 ;
    END
  END q[501]
  PIN q[502]
    DIRECTION OUTPUT ;
    USE SIGNAL ;
    PORT
      LAYER M4 ;
        RECT  21.516 15.12 21.6 15.144 ;
    END
  END q[502]
  PIN q[503]
    DIRECTION OUTPUT ;
    USE SIGNAL ;
    PORT
      LAYER M4 ;
        RECT  21.516 15.216 21.6 15.24 ;
    END
  END q[503]
  PIN q[504]
    DIRECTION OUTPUT ;
    USE SIGNAL ;
    PORT
      LAYER M4 ;
        RECT  21.516 15.312 21.6 15.336 ;
    END
  END q[504]
  PIN q[505]
    DIRECTION OUTPUT ;
    USE SIGNAL ;
    PORT
      LAYER M4 ;
        RECT  21.516 15.408 21.6 15.432 ;
    END
  END q[505]
  PIN q[506]
    DIRECTION OUTPUT ;
    USE SIGNAL ;
    PORT
      LAYER M4 ;
        RECT  21.516 15.504 21.6 15.528 ;
    END
  END q[506]
  PIN q[507]
    DIRECTION OUTPUT ;
    USE SIGNAL ;
    PORT
      LAYER M4 ;
        RECT  21.516 15.6 21.6 15.624 ;
    END
  END q[507]
  PIN q[508]
    DIRECTION OUTPUT ;
    USE SIGNAL ;
    PORT
      LAYER M4 ;
        RECT  21.516 15.696 21.6 15.72 ;
    END
  END q[508]
  PIN q[509]
    DIRECTION OUTPUT ;
    USE SIGNAL ;
    PORT
      LAYER M4 ;
        RECT  21.516 15.792 21.6 15.816 ;
    END
  END q[509]
  PIN q[50]
    DIRECTION OUTPUT ;
    USE SIGNAL ;
    PORT
      LAYER M4 ;
        RECT  21.516 33.936 21.6 33.96 ;
    END
  END q[50]
  PIN q[510]
    DIRECTION OUTPUT ;
    USE SIGNAL ;
    PORT
      LAYER M4 ;
        RECT  21.516 15.888 21.6 15.912 ;
    END
  END q[510]
  PIN q[511]
    DIRECTION OUTPUT ;
    USE SIGNAL ;
    PORT
      LAYER M4 ;
        RECT  21.516 15.984 21.6 16.008 ;
    END
  END q[511]
  PIN q[51]
    DIRECTION OUTPUT ;
    USE SIGNAL ;
    PORT
      LAYER M4 ;
        RECT  21.516 34.032 21.6 34.056 ;
    END
  END q[51]
  PIN q[52]
    DIRECTION OUTPUT ;
    USE SIGNAL ;
    PORT
      LAYER M4 ;
        RECT  21.516 34.128 21.6 34.152 ;
    END
  END q[52]
  PIN q[53]
    DIRECTION OUTPUT ;
    USE SIGNAL ;
    PORT
      LAYER M4 ;
        RECT  21.516 34.224 21.6 34.248 ;
    END
  END q[53]
  PIN q[54]
    DIRECTION OUTPUT ;
    USE SIGNAL ;
    PORT
      LAYER M4 ;
        RECT  21.516 34.32 21.6 34.344 ;
    END
  END q[54]
  PIN q[55]
    DIRECTION OUTPUT ;
    USE SIGNAL ;
    PORT
      LAYER M4 ;
        RECT  21.516 34.416 21.6 34.44 ;
    END
  END q[55]
  PIN q[56]
    DIRECTION OUTPUT ;
    USE SIGNAL ;
    PORT
      LAYER M4 ;
        RECT  21.516 34.512 21.6 34.536 ;
    END
  END q[56]
  PIN q[57]
    DIRECTION OUTPUT ;
    USE SIGNAL ;
    PORT
      LAYER M4 ;
        RECT  21.516 34.608 21.6 34.632 ;
    END
  END q[57]
  PIN q[58]
    DIRECTION OUTPUT ;
    USE SIGNAL ;
    PORT
      LAYER M4 ;
        RECT  21.516 34.704 21.6 34.728 ;
    END
  END q[58]
  PIN q[59]
    DIRECTION OUTPUT ;
    USE SIGNAL ;
    PORT
      LAYER M4 ;
        RECT  21.516 34.8 21.6 34.824 ;
    END
  END q[59]
  PIN q[5]
    DIRECTION OUTPUT ;
    USE SIGNAL ;
    PORT
      LAYER M4 ;
        RECT  21.516 26.544 21.6 26.568 ;
    END
  END q[5]
  PIN q[60]
    DIRECTION OUTPUT ;
    USE SIGNAL ;
    PORT
      LAYER M4 ;
        RECT  21.516 34.896 21.6 34.92 ;
    END
  END q[60]
  PIN q[61]
    DIRECTION OUTPUT ;
    USE SIGNAL ;
    PORT
      LAYER M4 ;
        RECT  21.516 34.992 21.6 35.016 ;
    END
  END q[61]
  PIN q[62]
    DIRECTION OUTPUT ;
    USE SIGNAL ;
    PORT
      LAYER M4 ;
        RECT  21.516 35.088 21.6 35.112 ;
    END
  END q[62]
  PIN q[63]
    DIRECTION OUTPUT ;
    USE SIGNAL ;
    PORT
      LAYER M4 ;
        RECT  21.516 35.184 21.6 35.208 ;
    END
  END q[63]
  PIN q[64]
    DIRECTION OUTPUT ;
    USE SIGNAL ;
    PORT
      LAYER M4 ;
        RECT  21.516 19.92 21.6 19.944 ;
    END
  END q[64]
  PIN q[65]
    DIRECTION OUTPUT ;
    USE SIGNAL ;
    PORT
      LAYER M4 ;
        RECT  21.516 20.016 21.6 20.04 ;
    END
  END q[65]
  PIN q[66]
    DIRECTION OUTPUT ;
    USE SIGNAL ;
    PORT
      LAYER M4 ;
        RECT  21.516 20.112 21.6 20.136 ;
    END
  END q[66]
  PIN q[67]
    DIRECTION OUTPUT ;
    USE SIGNAL ;
    PORT
      LAYER M4 ;
        RECT  21.516 20.208 21.6 20.232 ;
    END
  END q[67]
  PIN q[68]
    DIRECTION OUTPUT ;
    USE SIGNAL ;
    PORT
      LAYER M4 ;
        RECT  21.516 20.304 21.6 20.328 ;
    END
  END q[68]
  PIN q[69]
    DIRECTION OUTPUT ;
    USE SIGNAL ;
    PORT
      LAYER M4 ;
        RECT  21.516 20.4 21.6 20.424 ;
    END
  END q[69]
  PIN q[6]
    DIRECTION OUTPUT ;
    USE SIGNAL ;
    PORT
      LAYER M4 ;
        RECT  21.516 26.64 21.6 26.664 ;
    END
  END q[6]
  PIN q[70]
    DIRECTION OUTPUT ;
    USE SIGNAL ;
    PORT
      LAYER M4 ;
        RECT  21.516 20.496 21.6 20.52 ;
    END
  END q[70]
  PIN q[71]
    DIRECTION OUTPUT ;
    USE SIGNAL ;
    PORT
      LAYER M4 ;
        RECT  21.516 20.592 21.6 20.616 ;
    END
  END q[71]
  PIN q[72]
    DIRECTION OUTPUT ;
    USE SIGNAL ;
    PORT
      LAYER M4 ;
        RECT  21.516 20.688 21.6 20.712 ;
    END
  END q[72]
  PIN q[73]
    DIRECTION OUTPUT ;
    USE SIGNAL ;
    PORT
      LAYER M4 ;
        RECT  21.516 20.784 21.6 20.808 ;
    END
  END q[73]
  PIN q[74]
    DIRECTION OUTPUT ;
    USE SIGNAL ;
    PORT
      LAYER M4 ;
        RECT  21.516 20.88 21.6 20.904 ;
    END
  END q[74]
  PIN q[75]
    DIRECTION OUTPUT ;
    USE SIGNAL ;
    PORT
      LAYER M4 ;
        RECT  21.516 20.976 21.6 21 ;
    END
  END q[75]
  PIN q[76]
    DIRECTION OUTPUT ;
    USE SIGNAL ;
    PORT
      LAYER M4 ;
        RECT  21.516 21.072 21.6 21.096 ;
    END
  END q[76]
  PIN q[77]
    DIRECTION OUTPUT ;
    USE SIGNAL ;
    PORT
      LAYER M4 ;
        RECT  21.516 21.168 21.6 21.192 ;
    END
  END q[77]
  PIN q[78]
    DIRECTION OUTPUT ;
    USE SIGNAL ;
    PORT
      LAYER M4 ;
        RECT  21.516 21.264 21.6 21.288 ;
    END
  END q[78]
  PIN q[79]
    DIRECTION OUTPUT ;
    USE SIGNAL ;
    PORT
      LAYER M4 ;
        RECT  21.516 21.36 21.6 21.384 ;
    END
  END q[79]
  PIN q[7]
    DIRECTION OUTPUT ;
    USE SIGNAL ;
    PORT
      LAYER M4 ;
        RECT  21.516 26.736 21.6 26.76 ;
    END
  END q[7]
  PIN q[80]
    DIRECTION OUTPUT ;
    USE SIGNAL ;
    PORT
      LAYER M4 ;
        RECT  21.516 21.456 21.6 21.48 ;
    END
  END q[80]
  PIN q[81]
    DIRECTION OUTPUT ;
    USE SIGNAL ;
    PORT
      LAYER M4 ;
        RECT  21.516 21.552 21.6 21.576 ;
    END
  END q[81]
  PIN q[82]
    DIRECTION OUTPUT ;
    USE SIGNAL ;
    PORT
      LAYER M4 ;
        RECT  21.516 21.648 21.6 21.672 ;
    END
  END q[82]
  PIN q[83]
    DIRECTION OUTPUT ;
    USE SIGNAL ;
    PORT
      LAYER M4 ;
        RECT  21.516 21.744 21.6 21.768 ;
    END
  END q[83]
  PIN q[84]
    DIRECTION OUTPUT ;
    USE SIGNAL ;
    PORT
      LAYER M4 ;
        RECT  21.516 21.84 21.6 21.864 ;
    END
  END q[84]
  PIN q[85]
    DIRECTION OUTPUT ;
    USE SIGNAL ;
    PORT
      LAYER M4 ;
        RECT  21.516 21.936 21.6 21.96 ;
    END
  END q[85]
  PIN q[86]
    DIRECTION OUTPUT ;
    USE SIGNAL ;
    PORT
      LAYER M4 ;
        RECT  21.516 22.032 21.6 22.056 ;
    END
  END q[86]
  PIN q[87]
    DIRECTION OUTPUT ;
    USE SIGNAL ;
    PORT
      LAYER M4 ;
        RECT  21.516 22.128 21.6 22.152 ;
    END
  END q[87]
  PIN q[88]
    DIRECTION OUTPUT ;
    USE SIGNAL ;
    PORT
      LAYER M4 ;
        RECT  21.516 22.224 21.6 22.248 ;
    END
  END q[88]
  PIN q[89]
    DIRECTION OUTPUT ;
    USE SIGNAL ;
    PORT
      LAYER M4 ;
        RECT  21.516 22.32 21.6 22.344 ;
    END
  END q[89]
  PIN q[8]
    DIRECTION OUTPUT ;
    USE SIGNAL ;
    PORT
      LAYER M4 ;
        RECT  21.516 26.832 21.6 26.856 ;
    END
  END q[8]
  PIN q[90]
    DIRECTION OUTPUT ;
    USE SIGNAL ;
    PORT
      LAYER M4 ;
        RECT  21.516 22.416 21.6 22.44 ;
    END
  END q[90]
  PIN q[91]
    DIRECTION OUTPUT ;
    USE SIGNAL ;
    PORT
      LAYER M4 ;
        RECT  21.516 22.512 21.6 22.536 ;
    END
  END q[91]
  PIN q[92]
    DIRECTION OUTPUT ;
    USE SIGNAL ;
    PORT
      LAYER M4 ;
        RECT  21.516 22.608 21.6 22.632 ;
    END
  END q[92]
  PIN q[93]
    DIRECTION OUTPUT ;
    USE SIGNAL ;
    PORT
      LAYER M4 ;
        RECT  21.516 22.704 21.6 22.728 ;
    END
  END q[93]
  PIN q[94]
    DIRECTION OUTPUT ;
    USE SIGNAL ;
    PORT
      LAYER M4 ;
        RECT  21.516 22.8 21.6 22.824 ;
    END
  END q[94]
  PIN q[95]
    DIRECTION OUTPUT ;
    USE SIGNAL ;
    PORT
      LAYER M4 ;
        RECT  21.516 22.896 21.6 22.92 ;
    END
  END q[95]
  PIN q[96]
    DIRECTION OUTPUT ;
    USE SIGNAL ;
    PORT
      LAYER M4 ;
        RECT  21.516 22.992 21.6 23.016 ;
    END
  END q[96]
  PIN q[97]
    DIRECTION OUTPUT ;
    USE SIGNAL ;
    PORT
      LAYER M4 ;
        RECT  21.516 23.088 21.6 23.112 ;
    END
  END q[97]
  PIN q[98]
    DIRECTION OUTPUT ;
    USE SIGNAL ;
    PORT
      LAYER M4 ;
        RECT  21.516 23.184 21.6 23.208 ;
    END
  END q[98]
  PIN q[99]
    DIRECTION OUTPUT ;
    USE SIGNAL ;
    PORT
      LAYER M4 ;
        RECT  21.516 23.28 21.6 23.304 ;
    END
  END q[99]
  PIN q[9]
    DIRECTION OUTPUT ;
    USE SIGNAL ;
    PORT
      LAYER M4 ;
        RECT  21.516 26.928 21.6 26.952 ;
    END
  END q[9]
  PIN VDD
    DIRECTION INOUT ;
    USE POWER ;
    PORT
      LAYER M5 ;
        RECT  18.792 2.151 18.912 62.649 ;
        RECT  13.392 2.151 13.512 62.649 ;
        RECT  7.992 2.151 8.112 62.649 ;
        RECT  2.592 2.151 2.712 62.649 ;
    END
  END VDD
  PIN VSS
    DIRECTION INOUT ;
    USE GROUND ;
    PORT
      LAYER M5 ;
        RECT  18.6 2.137 18.72 62.663 ;
        RECT  13.2 2.137 13.32 62.663 ;
        RECT  7.8 2.137 7.92 62.663 ;
        RECT  2.4 2.137 2.52 62.663 ;
    END
  END VSS
  OBS
    LAYER RVTN ;
     RECT  2.16 2.16 19.44 2.295 ;
     RECT  2.16 2.565 19.44 2.835 ;
     RECT  2.16 3.105 19.44 3.375 ;
     RECT  2.16 3.645 19.44 3.915 ;
     RECT  2.16 4.185 19.44 4.455 ;
     RECT  2.16 4.725 19.44 4.995 ;
     RECT  2.16 5.265 19.44 5.535 ;
     RECT  2.16 5.805 19.44 6.075 ;
     RECT  2.16 6.345 19.44 6.615 ;
     RECT  2.16 6.885 19.44 7.155 ;
     RECT  2.16 7.425 19.44 7.695 ;
     RECT  2.16 7.965 19.44 8.235 ;
     RECT  2.16 8.505 19.44 8.775 ;
     RECT  2.16 9.045 19.44 9.315 ;
     RECT  2.16 9.585 19.44 9.855 ;
     RECT  2.16 10.125 19.44 10.395 ;
     RECT  2.16 10.665 19.44 10.935 ;
     RECT  2.16 11.205 19.44 11.475 ;
     RECT  2.16 11.745 19.44 12.015 ;
     RECT  2.16 12.285 19.44 12.555 ;
     RECT  2.16 12.825 19.44 13.095 ;
     RECT  2.16 13.365 19.44 13.635 ;
     RECT  2.16 13.905 19.44 14.175 ;
     RECT  2.16 14.445 19.44 14.715 ;
     RECT  2.16 14.985 19.44 15.255 ;
     RECT  2.16 15.525 19.44 15.795 ;
     RECT  2.16 16.065 19.44 16.335 ;
     RECT  2.16 16.605 19.44 16.875 ;
     RECT  2.16 17.145 19.44 17.415 ;
     RECT  2.16 17.685 19.44 17.955 ;
     RECT  2.16 18.225 19.44 18.495 ;
     RECT  2.16 18.765 19.44 19.035 ;
     RECT  2.16 19.305 19.44 19.575 ;
     RECT  2.16 19.845 19.44 20.115 ;
     RECT  2.16 20.385 19.44 20.655 ;
     RECT  2.16 20.925 19.44 21.195 ;
     RECT  2.16 21.465 19.44 21.735 ;
     RECT  2.16 22.005 19.44 22.275 ;
     RECT  2.16 22.545 19.44 22.815 ;
     RECT  2.16 23.085 19.44 23.355 ;
     RECT  2.16 23.625 19.44 23.895 ;
     RECT  2.16 24.165 19.44 24.435 ;
     RECT  2.16 24.705 19.44 24.975 ;
     RECT  2.16 25.245 19.44 25.515 ;
     RECT  2.16 25.785 19.44 26.055 ;
     RECT  2.16 26.325 19.44 26.595 ;
     RECT  2.16 26.865 19.44 27.135 ;
     RECT  2.16 27.405 19.44 27.675 ;
     RECT  2.16 27.945 19.44 28.215 ;
     RECT  2.16 28.485 19.44 28.755 ;
     RECT  2.16 29.025 19.44 29.295 ;
     RECT  2.16 29.565 19.44 29.835 ;
     RECT  2.16 30.105 19.44 30.375 ;
     RECT  2.16 30.645 19.44 30.915 ;
     RECT  2.16 31.185 19.44 31.455 ;
     RECT  2.16 31.725 19.44 31.995 ;
     RECT  2.16 32.265 19.44 32.535 ;
     RECT  2.16 32.805 19.44 33.075 ;
     RECT  2.16 33.345 19.44 33.615 ;
     RECT  2.16 33.885 19.44 34.155 ;
     RECT  2.16 34.425 19.44 34.695 ;
     RECT  2.16 34.965 19.44 35.235 ;
     RECT  2.16 35.505 19.44 35.775 ;
     RECT  2.16 36.045 19.44 36.315 ;
     RECT  2.16 36.585 19.44 36.855 ;
     RECT  2.16 37.125 19.44 37.395 ;
     RECT  2.16 37.665 19.44 37.935 ;
     RECT  2.16 38.205 19.44 38.475 ;
     RECT  2.16 38.745 19.44 39.015 ;
     RECT  2.16 39.285 19.44 39.555 ;
     RECT  2.16 39.825 19.44 40.095 ;
     RECT  2.16 40.365 19.44 40.635 ;
     RECT  2.16 40.905 19.44 41.175 ;
     RECT  2.16 41.445 19.44 41.715 ;
     RECT  2.16 41.985 19.44 42.255 ;
     RECT  2.16 42.525 19.44 42.795 ;
     RECT  2.16 43.065 19.44 43.335 ;
     RECT  2.16 43.605 19.44 43.875 ;
     RECT  2.16 44.145 19.44 44.415 ;
     RECT  2.16 44.685 19.44 44.955 ;
     RECT  2.16 45.225 19.44 45.495 ;
     RECT  2.16 45.765 19.44 46.035 ;
     RECT  2.16 46.305 19.44 46.575 ;
     RECT  2.16 46.845 19.44 47.115 ;
     RECT  2.16 47.385 19.44 47.655 ;
     RECT  2.16 47.925 19.44 48.195 ;
     RECT  2.16 48.465 19.44 48.735 ;
     RECT  2.16 49.005 19.44 49.275 ;
     RECT  2.16 49.545 19.44 49.815 ;
     RECT  2.16 50.085 19.44 50.355 ;
     RECT  2.16 50.625 19.44 50.895 ;
     RECT  2.16 51.165 19.44 51.435 ;
     RECT  2.16 51.705 19.44 51.975 ;
     RECT  2.16 52.245 19.44 52.515 ;
     RECT  2.16 52.785 19.44 53.055 ;
     RECT  2.16 53.325 19.44 53.595 ;
     RECT  2.16 53.865 19.44 54.135 ;
     RECT  2.16 54.405 19.44 54.675 ;
     RECT  2.16 54.945 19.44 55.215 ;
     RECT  2.16 55.485 19.44 55.755 ;
     RECT  2.16 56.025 19.44 56.295 ;
     RECT  2.16 56.565 19.44 56.835 ;
     RECT  2.16 57.105 19.44 57.375 ;
     RECT  2.16 57.645 19.44 57.915 ;
     RECT  2.16 58.185 19.44 58.455 ;
     RECT  2.16 58.725 19.44 58.995 ;
     RECT  2.16 59.265 19.44 59.535 ;
     RECT  2.16 59.805 19.44 60.075 ;
     RECT  2.16 60.345 19.44 60.615 ;
     RECT  2.16 60.885 19.44 61.155 ;
     RECT  2.16 61.425 19.44 61.695 ;
     RECT  2.16 61.965 19.44 62.235 ;
     RECT  2.16 62.505 19.44 62.64 ;
    LAYER RVTP ;
     RECT  2.16 2.295 19.44 2.565 ;
     RECT  2.16 2.835 19.44 3.105 ;
     RECT  2.16 3.375 19.44 3.645 ;
     RECT  2.16 3.915 19.44 4.185 ;
     RECT  2.16 4.455 19.44 4.725 ;
     RECT  2.16 4.995 19.44 5.265 ;
     RECT  2.16 5.535 19.44 5.805 ;
     RECT  2.16 6.075 19.44 6.345 ;
     RECT  2.16 6.615 19.44 6.885 ;
     RECT  2.16 7.155 19.44 7.425 ;
     RECT  2.16 7.695 19.44 7.965 ;
     RECT  2.16 8.235 19.44 8.505 ;
     RECT  2.16 8.775 19.44 9.045 ;
     RECT  2.16 9.315 19.44 9.585 ;
     RECT  2.16 9.855 19.44 10.125 ;
     RECT  2.16 10.395 19.44 10.665 ;
     RECT  2.16 10.935 19.44 11.205 ;
     RECT  2.16 11.475 19.44 11.745 ;
     RECT  2.16 12.015 19.44 12.285 ;
     RECT  2.16 12.555 19.44 12.825 ;
     RECT  2.16 13.095 19.44 13.365 ;
     RECT  2.16 13.635 19.44 13.905 ;
     RECT  2.16 14.175 19.44 14.445 ;
     RECT  2.16 14.715 19.44 14.985 ;
     RECT  2.16 15.255 19.44 15.525 ;
     RECT  2.16 15.795 19.44 16.065 ;
     RECT  2.16 16.335 19.44 16.605 ;
     RECT  2.16 16.875 19.44 17.145 ;
     RECT  2.16 17.415 19.44 17.685 ;
     RECT  2.16 17.955 19.44 18.225 ;
     RECT  2.16 18.495 19.44 18.765 ;
     RECT  2.16 19.035 19.44 19.305 ;
     RECT  2.16 19.575 19.44 19.845 ;
     RECT  2.16 20.115 19.44 20.385 ;
     RECT  2.16 20.655 19.44 20.925 ;
     RECT  2.16 21.195 19.44 21.465 ;
     RECT  2.16 21.735 19.44 22.005 ;
     RECT  2.16 22.275 19.44 22.545 ;
     RECT  2.16 22.815 19.44 23.085 ;
     RECT  2.16 23.355 19.44 23.625 ;
     RECT  2.16 23.895 19.44 24.165 ;
     RECT  2.16 24.435 19.44 24.705 ;
     RECT  2.16 24.975 19.44 25.245 ;
     RECT  2.16 25.515 19.44 25.785 ;
     RECT  2.16 26.055 19.44 26.325 ;
     RECT  2.16 26.595 19.44 26.865 ;
     RECT  2.16 27.135 19.44 27.405 ;
     RECT  2.16 27.675 19.44 27.945 ;
     RECT  2.16 28.215 19.44 28.485 ;
     RECT  2.16 28.755 19.44 29.025 ;
     RECT  2.16 29.295 19.44 29.565 ;
     RECT  2.16 29.835 19.44 30.105 ;
     RECT  2.16 30.375 19.44 30.645 ;
     RECT  2.16 30.915 19.44 31.185 ;
     RECT  2.16 31.455 19.44 31.725 ;
     RECT  2.16 31.995 19.44 32.265 ;
     RECT  2.16 32.535 19.44 32.805 ;
     RECT  2.16 33.075 19.44 33.345 ;
     RECT  2.16 33.615 19.44 33.885 ;
     RECT  2.16 34.155 19.44 34.425 ;
     RECT  2.16 34.695 19.44 34.965 ;
     RECT  2.16 35.235 19.44 35.505 ;
     RECT  2.16 35.775 19.44 36.045 ;
     RECT  2.16 36.315 19.44 36.585 ;
     RECT  2.16 36.855 19.44 37.125 ;
     RECT  2.16 37.395 19.44 37.665 ;
     RECT  2.16 37.935 19.44 38.205 ;
     RECT  2.16 38.475 19.44 38.745 ;
     RECT  2.16 39.015 19.44 39.285 ;
     RECT  2.16 39.555 19.44 39.825 ;
     RECT  2.16 40.095 19.44 40.365 ;
     RECT  2.16 40.635 19.44 40.905 ;
     RECT  2.16 41.175 19.44 41.445 ;
     RECT  2.16 41.715 19.44 41.985 ;
     RECT  2.16 42.255 19.44 42.525 ;
     RECT  2.16 42.795 19.44 43.065 ;
     RECT  2.16 43.335 19.44 43.605 ;
     RECT  2.16 43.875 19.44 44.145 ;
     RECT  2.16 44.415 19.44 44.685 ;
     RECT  2.16 44.955 19.44 45.225 ;
     RECT  2.16 45.495 19.44 45.765 ;
     RECT  2.16 46.035 19.44 46.305 ;
     RECT  2.16 46.575 19.44 46.845 ;
     RECT  2.16 47.115 19.44 47.385 ;
     RECT  2.16 47.655 19.44 47.925 ;
     RECT  2.16 48.195 19.44 48.465 ;
     RECT  2.16 48.735 19.44 49.005 ;
     RECT  2.16 49.275 19.44 49.545 ;
     RECT  2.16 49.815 19.44 50.085 ;
     RECT  2.16 50.355 19.44 50.625 ;
     RECT  2.16 50.895 19.44 51.165 ;
     RECT  2.16 51.435 19.44 51.705 ;
     RECT  2.16 51.975 19.44 52.245 ;
     RECT  2.16 52.515 19.44 52.785 ;
     RECT  2.16 53.055 19.44 53.325 ;
     RECT  2.16 53.595 19.44 53.865 ;
     RECT  2.16 54.135 19.44 54.405 ;
     RECT  2.16 54.675 19.44 54.945 ;
     RECT  2.16 55.215 19.44 55.485 ;
     RECT  2.16 55.755 19.44 56.025 ;
     RECT  2.16 56.295 19.44 56.565 ;
     RECT  2.16 56.835 19.44 57.105 ;
     RECT  2.16 57.375 19.44 57.645 ;
     RECT  2.16 57.915 19.44 58.185 ;
     RECT  2.16 58.455 19.44 58.725 ;
     RECT  2.16 58.995 19.44 59.265 ;
     RECT  2.16 59.535 19.44 59.805 ;
     RECT  2.16 60.075 19.44 60.345 ;
     RECT  2.16 60.615 19.44 60.885 ;
     RECT  2.16 61.155 19.44 61.425 ;
     RECT  2.16 61.695 19.44 61.965 ;
     RECT  2.16 62.235 19.44 62.505 ;
    LAYER M1 ;
     RECT  2.16 2.151 19.44 62.649 ;
    LAYER M2 ;
     RECT  0.103 2.772 0.139 2.79 ;
     RECT  0.103 5.04 0.139 5.058 ;
     RECT  0.103 7.2 0.139 7.218 ;
     RECT  0.103 20.43 0.139 20.448 ;
     RECT  0.103 26.37 0.139 26.388 ;
     RECT  0.103 28.422 0.139 30.708 ;
     RECT  0.103 32.04 0.139 32.058 ;
     RECT  0.067 43.812 0.139 43.83 ;
     RECT  0.103 45.036 0.139 45.486 ;
     RECT  0.067 48.132 0.167 48.15 ;
     RECT  0.103 4.122 0.175 4.14 ;
     RECT  0.139 5.04 0.175 5.094 ;
     RECT  0.103 8.478 0.175 8.874 ;
     RECT  0.103 10.521 0.175 10.539 ;
     RECT  0.139 26.1 0.175 26.388 ;
     RECT  0.139 27.342 0.175 30.708 ;
     RECT  0.103 38.448 0.175 38.7 ;
     RECT  0.175 10.17 0.203 10.539 ;
     RECT  0.139 2.772 0.211 3.33 ;
     RECT  0.175 4.122 0.211 5.094 ;
     RECT  0.103 15.534 0.211 16.29 ;
     RECT  0.139 19.89 0.211 20.448 ;
     RECT  0.175 26.1 0.211 30.708 ;
     RECT  0.211 25.992 0.247 30.708 ;
     RECT  0.139 31.968 0.247 32.058 ;
     RECT  0.211 15.462 0.275 16.29 ;
     RECT  0.103 23.598 0.275 24.12 ;
     RECT  0.139 43.812 0.283 45.486 ;
     RECT  0.211 46.35 0.283 46.368 ;
     RECT  0.175 8.478 0.347 9.378 ;
     RECT  0.103 41.796 0.347 41.814 ;
     RECT  0.211 51.336 0.347 51.354 ;
     RECT  0.283 43.812 0.355 46.368 ;
     RECT  0.103 47.16 0.355 47.178 ;
     RECT  0.211 2.772 0.383 5.094 ;
     RECT  0.355 43.812 0.499 47.178 ;
     RECT  0.103 12.024 0.535 12.042 ;
     RECT  0.103 13.032 0.535 13.05 ;
     RECT  0.103 17.046 0.535 17.406 ;
     RECT  0.211 19.89 0.535 20.988 ;
     RECT  0.103 21.78 0.535 21.798 ;
     RECT  0.175 36.63 0.535 36.648 ;
     RECT  0.211 56.034 0.535 56.052 ;
     RECT  0.859 50.022 0.895 50.04 ;
     RECT  0.823 50.832 0.895 50.85 ;
     RECT  0.499 43.812 0.931 48.024 ;
     RECT  0.103 48.942 0.931 48.96 ;
     RECT  0.571 54.612 1.111 54.63 ;
     RECT  0.535 55.53 1.111 56.052 ;
     RECT  0.535 11.484 1.183 12.042 ;
     RECT  0.535 13.032 1.183 13.662 ;
     RECT  0.103 57.852 1.399 57.87 ;
     RECT  0.895 50.022 1.435 50.85 ;
     RECT  1.111 54.612 1.471 56.052 ;
     RECT  1.471 54.612 1.507 56.25 ;
     RECT  0.247 57.042 1.507 57.06 ;
     RECT  1.183 11.484 1.723 13.662 ;
     RECT  0.931 43.812 1.723 48.96 ;
     RECT  1.507 54.612 1.723 57.06 ;
     RECT  1.723 42.264 1.759 48.96 ;
     RECT  1.399 51.642 1.759 51.66 ;
     RECT  1.759 51.642 1.795 51.93 ;
     RECT  0.031 52.722 1.795 52.74 ;
     RECT  0.535 17.046 1.831 17.676 ;
     RECT  1.795 51.642 1.831 52.74 ;
     RECT  1.723 53.946 1.831 57.06 ;
     RECT  1.831 51.642 1.903 52.884 ;
     RECT  1.759 41.724 2.119 48.96 ;
     RECT  1.435 49.824 2.119 50.85 ;
     RECT  0.247 25.992 2.155 32.058 ;
     RECT  0.535 33.426 2.155 33.444 ;
     RECT  0.383 2.772 2.16 5.058 ;
     RECT  0.139 6.624 2.16 7.218 ;
     RECT  0.347 8.478 2.16 8.874 ;
     RECT  0.203 10.17 2.16 10.188 ;
     RECT  1.723 11.448 2.16 13.662 ;
     RECT  0.275 15.462 2.16 16.128 ;
     RECT  1.831 16.884 2.16 17.676 ;
     RECT  0.103 18.54 2.16 18.558 ;
     RECT  0.535 19.89 2.16 21.798 ;
     RECT  0.275 23.832 2.16 24.12 ;
     RECT  2.155 25.992 2.16 33.444 ;
     RECT  0.535 36.594 2.16 36.648 ;
     RECT  0.175 38.142 2.16 38.7 ;
     RECT  2.119 41.724 2.16 50.85 ;
     RECT  1.903 51.642 2.16 53.01 ;
     RECT  1.831 53.838 2.16 57.06 ;
     RECT  1.399 57.852 2.16 58.41 ;
     RECT  1.975 59.202 2.16 59.22 ;
     RECT  2.16 2.151 19.44 62.649 ;
     RECT  19.44 4.266 19.679 59.994 ;
     RECT  19.679 4.266 20.039 59.904 ;
     RECT  20.039 4.266 20.075 43.794 ;
     RECT  20.075 4.536 20.111 43.794 ;
     RECT  20.111 4.806 20.183 43.794 ;
     RECT  20.039 44.586 20.219 59.904 ;
     RECT  20.219 44.586 20.255 58.716 ;
     RECT  20.219 59.886 20.291 59.904 ;
     RECT  20.255 44.586 20.435 58.644 ;
     RECT  20.183 4.806 20.471 14.814 ;
     RECT  20.471 4.806 20.507 5.796 ;
     RECT  20.471 6.624 20.507 14.814 ;
     RECT  20.183 15.606 20.507 43.794 ;
     RECT  20.435 44.586 20.507 57.834 ;
     RECT  20.507 6.624 20.543 12.348 ;
     RECT  20.507 15.606 20.543 24.498 ;
     RECT  20.507 25.29 20.543 28.476 ;
     RECT  20.507 29.736 20.543 31.914 ;
     RECT  20.507 56.268 20.543 57.204 ;
     RECT  20.543 17.082 20.579 23.382 ;
     RECT  20.507 44.586 20.579 54.054 ;
     RECT  20.507 4.806 20.615 5.634 ;
     RECT  20.579 46.206 21.227 54.054 ;
     RECT  20.579 17.082 21.407 23.076 ;
     RECT  20.543 30.276 21.407 30.834 ;
     RECT  21.227 46.206 21.407 53.964 ;
     RECT  20.543 7.2 21.415 12.348 ;
     RECT  21.415 7.2 21.443 12.924 ;
     RECT  21.407 17.082 21.443 20.106 ;
     RECT  20.543 24.444 21.443 24.498 ;
     RECT  20.543 25.29 21.443 28.314 ;
     RECT  20.543 31.734 21.443 31.914 ;
     RECT  20.507 35.046 21.443 42.75 ;
     RECT  21.407 46.206 21.443 52.974 ;
     RECT  21.407 53.766 21.443 53.964 ;
     RECT  20.615 5.346 21.479 5.634 ;
     RECT  21.443 7.776 21.479 12.924 ;
     RECT  20.507 14.796 21.479 14.814 ;
     RECT  21.443 17.496 21.479 18.144 ;
     RECT  21.443 18.936 21.479 19.134 ;
     RECT  21.407 20.934 21.479 23.076 ;
     RECT  21.443 25.326 21.479 28.314 ;
     RECT  20.507 32.706 21.479 33.408 ;
     RECT  21.443 35.046 21.479 35.064 ;
     RECT  21.443 35.946 21.479 42.75 ;
     RECT  20.579 44.586 21.479 44.874 ;
     RECT  21.443 46.206 21.479 46.494 ;
     RECT  21.443 47.286 21.479 48.492 ;
     RECT  21.443 49.248 21.479 49.266 ;
     RECT  21.443 50.166 21.479 52.164 ;
     RECT  21.443 52.956 21.479 52.974 ;
     RECT  20.543 57.006 21.479 57.204 ;
     RECT  20.543 15.606 21.487 16.326 ;
     RECT  21.479 5.616 21.515 5.634 ;
     RECT  21.479 8.136 21.515 8.532 ;
     RECT  21.479 9.486 21.515 12.042 ;
     RECT  21.479 12.906 21.515 12.924 ;
     RECT  21.487 15.606 21.515 16.56 ;
     RECT  21.479 18.036 21.515 18.144 ;
     RECT  21.479 19.116 21.515 19.134 ;
     RECT  21.443 20.088 21.515 20.106 ;
     RECT  21.479 21.321 21.515 23.076 ;
     RECT  21.443 24.444 21.515 24.462 ;
     RECT  21.479 25.326 21.515 25.506 ;
     RECT  21.479 26.298 21.515 28.314 ;
     RECT  21.407 30.276 21.515 30.294 ;
     RECT  21.443 31.734 21.515 31.752 ;
     RECT  21.479 32.706 21.515 32.724 ;
     RECT  20.507 34.236 21.515 34.254 ;
     RECT  21.479 35.946 21.515 37.692 ;
     RECT  21.479 38.79 21.515 39.276 ;
     RECT  21.479 40.068 21.515 40.284 ;
     RECT  21.479 41.346 21.515 42.084 ;
     RECT  20.507 43.506 21.515 43.794 ;
     RECT  21.479 44.856 21.515 44.874 ;
     RECT  21.479 46.206 21.515 46.404 ;
     RECT  21.479 47.628 21.515 47.646 ;
     RECT  21.479 48.474 21.515 48.492 ;
     RECT  21.479 50.166 21.515 52.074 ;
     RECT  21.443 53.946 21.515 53.964 ;
     RECT  20.507 55.26 21.515 55.278 ;
     RECT  20.435 58.626 21.515 58.644 ;
     RECT  21.515 11.718 21.587 11.736 ;
     RECT  21.515 16.542 21.587 16.56 ;
    LAYER M3 ;
     RECT  2.415 2.143 2.505 2.227 ;
     RECT  2.304 2.227 2.505 2.413 ;
     RECT  7.815 2.143 7.905 2.413 ;
     RECT  13.215 2.143 13.305 2.413 ;
     RECT  18.615 2.143 18.705 2.413 ;
     RECT  2.304 2.413 2.697 2.731 ;
     RECT  2.304 2.731 2.754 2.767 ;
     RECT  2.304 2.767 2.934 2.803 ;
     RECT  13.215 2.413 13.497 3.109 ;
     RECT  0.108 2.767 0.126 3.145 ;
     RECT  18.615 2.413 18.897 3.145 ;
     RECT  4.032 2.731 4.05 3.181 ;
     RECT  7.815 2.413 8.097 3.181 ;
     RECT  18.468 3.145 18.897 3.181 ;
     RECT  2.304 2.803 3.222 3.301 ;
     RECT  3.96 3.181 4.086 3.301 ;
     RECT  6.696 3.271 6.714 3.343 ;
     RECT  5.976 3.343 6.714 3.415 ;
     RECT  2.304 3.301 4.086 3.541 ;
     RECT  5.148 3.415 6.714 3.541 ;
     RECT  0.108 3.145 0.198 3.577 ;
     RECT  2.304 3.541 6.714 3.649 ;
     RECT  7.488 3.181 8.097 3.649 ;
     RECT  13.215 3.109 13.734 3.649 ;
     RECT  2.304 3.649 8.097 3.721 ;
     RECT  0.108 3.577 0.234 3.787 ;
     RECT  2.304 3.721 8.622 3.955 ;
     RECT  10.224 3.931 10.242 3.983 ;
     RECT  18.468 3.181 19.278 4.081 ;
     RECT  11.304 3.955 11.322 4.225 ;
     RECT  16.416 4.081 16.434 4.225 ;
     RECT  18.432 4.081 19.278 4.225 ;
     RECT  11.268 4.225 11.322 4.261 ;
     RECT  15.228 4.225 15.282 4.261 ;
     RECT  16.416 4.225 16.65 4.261 ;
     RECT  2.304 3.955 9.09 4.351 ;
     RECT  9.9 4.261 9.918 4.351 ;
     RECT  14.76 4.261 15.426 4.351 ;
     RECT  16.272 4.261 16.722 4.351 ;
     RECT  2.304 4.351 9.918 4.387 ;
     RECT  2.268 4.387 9.918 4.415 ;
     RECT  11.268 4.261 11.43 4.459 ;
     RECT  0.108 3.787 0.342 4.495 ;
     RECT  13.215 3.649 13.986 4.495 ;
     RECT  17.568 4.225 19.278 4.495 ;
     RECT  14.76 4.351 16.722 4.531 ;
     RECT  17.46 4.495 19.278 4.531 ;
     RECT  20.052 4.261 20.07 4.531 ;
     RECT  11.268 4.459 12.042 4.555 ;
     RECT  12.78 4.495 13.986 4.621 ;
     RECT  14.76 4.531 19.278 4.621 ;
     RECT  10.764 4.555 12.042 4.801 ;
     RECT  20.052 4.531 20.106 4.801 ;
     RECT  10.404 4.801 12.042 4.999 ;
     RECT  12.78 4.621 19.278 4.999 ;
     RECT  2.268 4.415 9.666 5.099 ;
     RECT  0.108 4.495 0.558 5.165 ;
     RECT  2.304 5.099 9.666 5.323 ;
     RECT  10.404 4.999 19.278 5.323 ;
     RECT  0.108 5.165 0.162 5.501 ;
     RECT  21.456 5.341 21.474 5.611 ;
     RECT  2.304 5.323 19.278 5.899 ;
     RECT  2.268 5.899 19.278 6.107 ;
     RECT  2.304 6.107 19.278 6.151 ;
     RECT  20.052 4.801 20.61 6.151 ;
     RECT  0.108 5.501 0.126 6.619 ;
     RECT  0.108 6.619 0.162 6.691 ;
     RECT  21.456 5.611 21.51 7.195 ;
     RECT  0.108 6.691 0.558 7.277 ;
     RECT  21.42 7.195 21.51 7.277 ;
     RECT  2.304 6.151 20.61 7.373 ;
     RECT  0.108 7.277 0.522 7.565 ;
     RECT  0.144 7.565 0.522 7.661 ;
     RECT  21.42 7.277 21.474 7.861 ;
     RECT  21.384 7.861 21.474 8.011 ;
     RECT  0.504 7.661 0.522 8.141 ;
     RECT  2.304 7.373 20.502 8.167 ;
     RECT  2.268 8.167 20.502 8.237 ;
     RECT  2.304 8.237 20.502 8.537 ;
     RECT  10.584 8.537 20.502 8.875 ;
     RECT  0.108 8.473 0.27 9.163 ;
     RECT  0.108 9.163 0.342 9.211 ;
     RECT  2.304 8.537 9.81 9.391 ;
     RECT  10.584 8.875 20.538 9.391 ;
     RECT  0.108 9.211 0.414 9.485 ;
     RECT  2.304 9.391 20.538 9.931 ;
     RECT  1.728 9.931 20.538 10.027 ;
     RECT  21.384 8.011 21.51 10.201 ;
     RECT  21.348 10.201 21.51 10.411 ;
     RECT  1.188 10.027 20.538 10.597 ;
     RECT  21.312 10.411 21.51 10.597 ;
     RECT  1.188 10.597 21.51 10.685 ;
     RECT  21.348 10.685 21.51 10.829 ;
     RECT  1.188 10.685 20.538 11.021 ;
     RECT  1.188 11.021 20.502 11.227 ;
     RECT  1.152 11.227 20.502 11.471 ;
     RECT  0.108 9.485 0.198 11.479 ;
     RECT  1.152 11.471 1.206 11.479 ;
     RECT  21.42 10.829 21.51 11.713 ;
     RECT  2.304 11.471 20.502 11.939 ;
     RECT  0.108 11.479 1.206 12.047 ;
     RECT  2.304 11.939 20.466 12.325 ;
     RECT  2.232 12.325 20.466 12.413 ;
     RECT  0.144 12.047 1.206 12.461 ;
     RECT  1.188 12.461 1.206 12.551 ;
     RECT  2.268 12.413 20.466 12.712 ;
     RECT  21.42 11.713 21.582 12.929 ;
     RECT  21.492 12.929 21.582 12.941 ;
     RECT  0.144 12.461 0.162 13.027 ;
     RECT  2.268 12.712 20.502 13.325 ;
     RECT  0.108 13.027 0.162 13.483 ;
     RECT  0.108 13.483 0.342 13.639 ;
     RECT  0.108 13.639 0.558 13.709 ;
     RECT  0.54 13.709 0.558 13.901 ;
     RECT  2.304 13.325 20.502 14.059 ;
     RECT  1.152 13.963 1.17 14.141 ;
     RECT  21.564 12.941 21.582 14.347 ;
     RECT  21.492 14.347 21.582 14.791 ;
     RECT  21.456 14.791 21.582 14.827 ;
     RECT  2.304 14.059 20.538 14.917 ;
     RECT  21.42 14.827 21.582 15.019 ;
     RECT  0.144 14.923 0.162 15.403 ;
     RECT  0.108 15.403 0.162 15.457 ;
     RECT  0.108 15.457 0.234 15.529 ;
     RECT  21.348 15.019 21.582 15.595 ;
     RECT  2.268 14.917 20.538 15.691 ;
     RECT  0.108 15.529 0.27 15.787 ;
     RECT  1.836 15.691 20.538 15.791 ;
     RECT  1.836 15.791 20.502 16.171 ;
     RECT  0.108 15.787 0.342 16.301 ;
     RECT  0.108 16.301 0.234 16.304 ;
     RECT  1.152 16.171 20.502 16.349 ;
     RECT  21.276 15.595 21.582 16.565 ;
     RECT  0.216 16.304 0.234 16.877 ;
     RECT  1.836 16.349 20.502 16.907 ;
     RECT  2.16 16.907 20.502 16.915 ;
     RECT  2.16 16.915 20.538 17.069 ;
     RECT  21.276 16.565 21.51 17.405 ;
     RECT  21.312 17.405 21.51 17.609 ;
     RECT  0.108 17.041 0.198 17.653 ;
     RECT  0.108 17.653 0.558 17.741 ;
     RECT  0.54 17.741 0.558 17.933 ;
     RECT  2.232 17.069 20.538 17.933 ;
     RECT  2.232 17.933 20.502 18.029 ;
     RECT  20.448 18.029 20.502 18.293 ;
     RECT  2.232 18.029 19.242 18.329 ;
     RECT  2.304 18.329 19.242 18.763 ;
     RECT  0.108 18.535 0.126 18.989 ;
     RECT  20.448 18.293 20.466 19.051 ;
     RECT  21.384 17.609 21.51 19.139 ;
     RECT  0.18 19.003 0.198 19.181 ;
     RECT  21.384 19.139 21.438 19.291 ;
     RECT  2.304 18.763 19.314 19.741 ;
     RECT  20.448 19.051 20.538 19.741 ;
     RECT  21.348 19.291 21.438 20.083 ;
     RECT  2.304 19.741 20.538 20.119 ;
     RECT  21.348 20.083 21.51 20.119 ;
     RECT  0.144 19.885 0.162 20.425 ;
     RECT  2.304 20.119 21.51 20.717 ;
     RECT  0.108 20.425 0.162 20.813 ;
     RECT  0.144 20.813 0.162 20.965 ;
     RECT  20.34 20.717 21.51 21.227 ;
     RECT  0.144 20.965 0.234 21.505 ;
     RECT  2.304 20.717 19.494 21.547 ;
     RECT  2.268 21.547 19.494 21.614 ;
     RECT  2.268 21.614 19.422 21.643 ;
     RECT  0.144 21.505 0.558 21.773 ;
     RECT  20.376 21.227 21.51 21.773 ;
     RECT  0.144 21.773 0.162 21.775 ;
     RECT  20.412 21.773 20.61 21.869 ;
     RECT  0.108 21.775 0.162 21.965 ;
     RECT  2.232 21.643 19.422 21.965 ;
     RECT  2.268 21.965 19.422 22.733 ;
     RECT  20.448 21.869 20.61 22.733 ;
     RECT  2.304 22.733 19.422 22.891 ;
     RECT  21.42 21.773 21.51 23.117 ;
     RECT  0.108 21.965 0.126 23.467 ;
     RECT  0.108 23.467 0.342 23.693 ;
     RECT  2.304 22.891 19.458 23.701 ;
     RECT  20.448 22.733 20.574 23.701 ;
     RECT  2.304 23.701 20.574 23.755 ;
     RECT  2.232 23.755 20.574 23.789 ;
     RECT  21.492 23.117 21.51 23.947 ;
     RECT  2.232 23.789 19.422 23.963 ;
     RECT  0.108 23.693 0.306 24.173 ;
     RECT  21.312 23.947 21.51 24.173 ;
     RECT  2.268 23.963 19.422 24.269 ;
     RECT  2.304 24.269 19.422 24.523 ;
     RECT  20.412 23.789 20.574 24.523 ;
     RECT  0.108 24.173 0.162 24.557 ;
     RECT  0.108 24.557 0.126 25.133 ;
     RECT  2.304 24.523 20.574 25.411 ;
     RECT  21.42 24.173 21.51 25.555 ;
     RECT  0.216 25.987 0.234 26.095 ;
     RECT  0.144 26.095 0.234 26.365 ;
     RECT  2.304 25.411 20.61 26.539 ;
     RECT  21.384 25.555 21.51 26.539 ;
     RECT  2.304 26.539 21.51 26.555 ;
     RECT  2.34 26.555 21.51 26.573 ;
     RECT  2.376 26.573 21.51 26.669 ;
     RECT  2.376 26.669 20.61 26.765 ;
     RECT  0.108 26.365 0.234 26.827 ;
     RECT  20.232 26.765 20.61 26.861 ;
     RECT  0.108 26.827 0.342 27.211 ;
     RECT  0.108 27.211 0.558 27.437 ;
     RECT  2.376 26.765 19.386 27.499 ;
     RECT  2.304 27.499 19.386 27.691 ;
     RECT  0.144 27.437 0.558 27.725 ;
     RECT  2.304 27.691 19.494 28.075 ;
     RECT  2.268 28.075 19.494 28.111 ;
     RECT  20.232 26.861 20.538 28.111 ;
     RECT  2.268 28.111 20.538 28.247 ;
     RECT  0.144 27.725 0.198 28.417 ;
     RECT  2.304 28.247 20.538 28.481 ;
     RECT  21.384 26.669 21.51 28.589 ;
     RECT  0.108 28.417 0.198 28.795 ;
     RECT  0.108 28.795 0.558 28.957 ;
     RECT  0.108 28.957 1.17 29.057 ;
     RECT  2.304 28.481 20.502 29.255 ;
     RECT  2.34 29.255 20.502 29.261 ;
     RECT  19.908 29.261 20.502 29.731 ;
     RECT  0.108 29.057 0.558 29.933 ;
     RECT  2.34 29.261 19.17 29.995 ;
     RECT  2.304 29.995 19.17 30.187 ;
     RECT  2.268 30.187 19.17 30.283 ;
     RECT  19.908 29.731 20.538 30.283 ;
     RECT  21.492 28.589 21.51 30.299 ;
     RECT  2.268 30.283 20.538 30.407 ;
     RECT  0.108 29.933 0.522 30.605 ;
     RECT  2.304 30.407 20.538 30.605 ;
     RECT  21.384 30.667 21.438 30.839 ;
     RECT  0.108 30.605 0.342 30.893 ;
     RECT  21.42 30.839 21.438 30.941 ;
     RECT  0.144 30.893 0.342 31.181 ;
     RECT  2.304 30.605 20.502 31.243 ;
     RECT  2.268 31.243 20.502 31.487 ;
     RECT  2.304 31.487 20.502 31.531 ;
     RECT  0.144 31.181 0.27 31.565 ;
     RECT  21.492 31.729 21.51 31.891 ;
     RECT  0.144 31.565 0.162 32.035 ;
     RECT  2.304 31.531 20.538 32.189 ;
     RECT  2.304 32.189 19.17 32.341 ;
     RECT  19.908 32.189 20.538 32.429 ;
     RECT  0.108 32.035 0.162 32.525 ;
     RECT  0.144 32.525 0.162 32.717 ;
     RECT  2.268 32.341 19.17 32.737 ;
     RECT  2.16 32.737 19.17 33.035 ;
     RECT  2.268 33.035 19.17 33.043 ;
     RECT  21.42 31.891 21.51 33.053 ;
     RECT  20.448 32.429 20.538 33.241 ;
     RECT  2.268 33.043 19.206 33.259 ;
     RECT  20.448 33.241 20.574 33.259 ;
     RECT  2.268 33.259 20.574 33.773 ;
     RECT  0.54 33.421 0.558 34.253 ;
     RECT  0.144 34.267 0.342 34.445 ;
     RECT  21.456 33.053 21.51 34.987 ;
     RECT  2.268 33.773 20.502 35.083 ;
     RECT  2.268 35.083 20.538 35.179 ;
     RECT  2.268 35.179 20.574 35.501 ;
     RECT  2.268 35.501 20.538 35.537 ;
     RECT  0.144 35.515 0.162 35.563 ;
     RECT  0.144 35.563 0.27 35.659 ;
     RECT  21.42 34.987 21.51 35.699 ;
     RECT  0.144 35.659 0.342 35.789 ;
     RECT  0.252 35.789 0.27 35.837 ;
     RECT  1.368 36.139 1.386 36.365 ;
     RECT  2.304 35.537 20.538 36.517 ;
     RECT  21.456 35.699 21.51 36.523 ;
     RECT  2.268 36.517 20.538 36.557 ;
     RECT  21.42 36.523 21.51 36.619 ;
     RECT  0.54 36.589 0.558 36.625 ;
     RECT  0.18 36.625 0.558 37.229 ;
     RECT  2.304 36.557 20.538 37.291 ;
     RECT  0.54 37.229 0.558 37.421 ;
     RECT  2.268 37.291 20.538 37.499 ;
     RECT  21.312 36.619 21.51 37.613 ;
     RECT  2.268 37.499 20.502 37.805 ;
     RECT  2.304 37.805 20.502 37.967 ;
     RECT  0.324 38.059 0.342 38.137 ;
     RECT  0.18 38.137 0.342 38.443 ;
     RECT  0.108 38.443 0.342 38.551 ;
     RECT  2.304 37.967 20.466 38.713 ;
     RECT  2.304 38.713 20.502 38.731 ;
     RECT  2.232 38.731 20.502 38.777 ;
     RECT  2.268 38.777 20.502 38.975 ;
     RECT  0.108 38.551 0.558 39.149 ;
     RECT  2.304 38.975 20.502 39.245 ;
     RECT  21.384 37.613 21.51 39.341 ;
     RECT  0.108 39.149 0.126 39.437 ;
     RECT  21.384 39.341 21.474 39.533 ;
     RECT  2.304 39.245 19.458 39.787 ;
     RECT  20.448 39.245 20.502 39.883 ;
     RECT  21.456 39.533 21.474 40.063 ;
     RECT  1.728 39.787 19.458 40.171 ;
     RECT  20.448 39.883 20.538 40.171 ;
     RECT  1.728 40.171 20.538 40.361 ;
     RECT  1.728 40.361 19.458 40.397 ;
     RECT  20.232 40.361 20.538 40.469 ;
     RECT  0.144 40.459 0.162 40.637 ;
     RECT  21.456 40.063 21.51 41.026 ;
     RECT  1.728 40.397 19.314 41.419 ;
     RECT  1.728 41.419 19.422 41.611 ;
     RECT  20.232 40.469 20.502 41.611 ;
     RECT  0.324 41.611 0.342 41.707 ;
     RECT  1.728 41.611 20.502 41.719 ;
     RECT  0.108 41.707 0.342 41.819 ;
     RECT  0.324 41.819 0.342 41.837 ;
     RECT  21.384 41.026 21.51 42.221 ;
     RECT  21.384 42.221 21.474 42.413 ;
     RECT  1.728 41.719 20.538 42.667 ;
     RECT  1.404 42.667 20.538 42.797 ;
     RECT  0.144 43.051 0.162 43.147 ;
     RECT  21.456 42.413 21.474 43.339 ;
     RECT  1.404 42.797 20.502 43.531 ;
     RECT  0.936 43.531 20.502 43.627 ;
     RECT  21.456 43.339 21.51 43.799 ;
     RECT  0.108 43.147 0.162 43.807 ;
     RECT  0.072 43.807 0.162 43.915 ;
     RECT  0.072 43.915 0.198 44.011 ;
     RECT  0.936 43.627 20.538 44.011 ;
     RECT  0.072 44.011 20.538 44.491 ;
     RECT  0.072 44.491 20.61 44.519 ;
     RECT  21.456 43.799 21.474 44.587 ;
     RECT  20.412 44.519 20.61 44.681 ;
     RECT  21.384 44.587 21.474 44.683 ;
     RECT  21.384 44.683 21.51 44.879 ;
     RECT  0.072 44.519 19.242 44.971 ;
     RECT  0.036 44.971 19.242 45.259 ;
     RECT  20.412 44.681 20.538 45.259 ;
     RECT  0.036 45.259 20.538 45.463 ;
     RECT  21.384 44.879 21.402 45.643 ;
     RECT  0.036 45.463 20.574 46.411 ;
     RECT  21.384 45.643 21.51 46.411 ;
     RECT  0.036 46.411 21.51 46.541 ;
     RECT  21.276 46.541 21.51 47.075 ;
     RECT  21.348 47.075 21.51 47.117 ;
     RECT  0.036 46.541 20.538 47.309 ;
     RECT  21.42 47.117 21.51 48.043 ;
     RECT  0.036 47.309 20.502 48.235 ;
     RECT  21.348 48.043 21.51 48.413 ;
     RECT  0.036 48.235 20.538 48.433 ;
     RECT  0.036 48.433 20.574 48.653 ;
     RECT  0.036 48.653 20.502 48.929 ;
     RECT  21.42 48.413 21.51 49.771 ;
     RECT  0.036 48.929 20.43 50.251 ;
     RECT  21.384 49.771 21.51 50.635 ;
     RECT  21.348 50.635 21.51 50.746 ;
     RECT  0.036 50.251 20.502 50.827 ;
     RECT  0.036 50.827 20.538 50.855 ;
     RECT  1.404 50.855 20.538 51.115 ;
     RECT  21.276 50.746 21.51 51.115 ;
     RECT  0.036 50.855 0.342 51.437 ;
     RECT  1.404 51.115 21.51 52.171 ;
     RECT  0.036 51.437 0.054 52.555 ;
     RECT  1.116 52.171 21.51 52.555 ;
     RECT  0.036 52.555 21.51 52.745 ;
     RECT  0.216 52.745 21.51 53.969 ;
     RECT  0.216 53.969 21.222 54.059 ;
     RECT  0.216 54.059 20.538 54.283 ;
     RECT  0.108 54.283 20.538 54.977 ;
     RECT  0.108 54.977 0.558 55.553 ;
     RECT  21.492 55.255 21.51 56.011 ;
     RECT  1.404 54.977 20.538 56.291 ;
     RECT  0.108 55.553 0.27 57.065 ;
     RECT  21.456 56.011 21.51 57.389 ;
     RECT  1.404 56.291 20.502 57.839 ;
     RECT  0.108 57.065 0.126 57.875 ;
     RECT  1.404 57.839 20.43 58.109 ;
     RECT  1.404 58.109 20.394 58.217 ;
     RECT  1.404 58.217 20.358 58.289 ;
     RECT  1.404 58.289 20.286 58.415 ;
     RECT  11.988 58.415 20.286 58.523 ;
     RECT  1.98 58.415 11.214 58.649 ;
     RECT  21.492 57.389 21.51 58.649 ;
     RECT  7.815 58.649 11.214 58.955 ;
     RECT  11.988 58.523 14.85 58.955 ;
     RECT  7.815 58.955 9.522 59.027 ;
     RECT  1.98 58.649 7.074 59.099 ;
     RECT  10.476 58.955 10.782 59.099 ;
     RECT  1.98 59.099 5.382 59.189 ;
     RECT  6.156 59.099 7.074 59.189 ;
     RECT  7.815 59.027 8.442 59.189 ;
     RECT  1.98 59.189 5.346 59.225 ;
     RECT  6.876 59.189 6.894 59.225 ;
     RECT  12.24 58.955 14.85 59.225 ;
     RECT  12.492 59.225 14.85 59.341 ;
     RECT  15.588 58.523 20.286 59.341 ;
     RECT  9.504 59.027 9.522 59.369 ;
     RECT  2.34 59.225 5.346 59.459 ;
     RECT  2.34 59.459 4.95 59.495 ;
     RECT  12.492 59.341 20.286 59.495 ;
     RECT  14.832 59.495 15.138 59.639 ;
     RECT  12.492 59.495 13.95 59.729 ;
     RECT  10.476 59.099 10.494 59.909 ;
     RECT  15.876 59.495 20.286 59.909 ;
     RECT  15.876 59.909 19.674 59.999 ;
     RECT  2.376 59.495 4.95 60.035 ;
     RECT  2.415 60.035 4.95 60.269 ;
     RECT  15.876 59.999 19.242 60.269 ;
     RECT  2.415 60.269 2.898 60.305 ;
     RECT  14.832 59.639 14.85 60.377 ;
     RECT  16.92 60.269 17.262 60.377 ;
     RECT  4.356 60.269 4.374 60.413 ;
     RECT  13.215 59.729 13.95 60.449 ;
     RECT  15.876 60.269 16.038 60.539 ;
     RECT  16.92 60.377 16.938 60.539 ;
     RECT  18.615 60.269 19.17 60.539 ;
     RECT  2.415 60.305 2.697 62.387 ;
     RECT  7.815 59.189 8.097 62.387 ;
     RECT  13.215 60.449 13.497 62.387 ;
     RECT  18.615 60.539 18.897 62.387 ;
     RECT  2.415 62.387 2.505 62.657 ;
     RECT  7.815 62.387 7.905 62.657 ;
     RECT  13.215 62.387 13.305 62.657 ;
     RECT  18.615 62.387 18.705 62.657 ;
    LAYER M4 ;
     RECT  0.025 44.976 0.06 45 ;
     RECT  0.06 3.408 0.133 54.792 ;
     RECT  2.221 57.024 2.257 57.048 ;
     RECT  2.257 56.832 2.401 57.048 ;
     RECT  0.133 2.256 2.408 2.28 ;
     RECT  0.133 3.408 2.408 54.888 ;
     RECT  2.401 55.968 2.408 57.624 ;
     RECT  2.408 2.148 2.512 62.652 ;
     RECT  2.512 2.418 2.704 62.382 ;
     RECT  2.704 3.312 2.915 59.976 ;
     RECT  2.915 58.464 2.945 59.976 ;
     RECT  2.945 58.56 2.963 59.976 ;
     RECT  2.963 59.52 2.981 59.976 ;
     RECT  2.915 3.312 3.413 45 ;
     RECT  2.915 46.128 3.587 57.336 ;
     RECT  3.413 3.552 3.877 45 ;
     RECT  3.587 46.128 3.877 54.936 ;
     RECT  3.973 58.56 4.117 58.584 ;
     RECT  2.981 59.664 4.117 59.976 ;
     RECT  4.117 58.56 4.133 59.976 ;
     RECT  4.133 59.856 4.169 59.976 ;
     RECT  3.587 56.064 4.241 57.336 ;
     RECT  3.877 3.552 4.493 54.936 ;
     RECT  4.493 3.552 4.529 18.984 ;
     RECT  4.241 56.064 4.529 57.048 ;
     RECT  4.493 19.968 4.565 54.936 ;
     RECT  4.565 19.968 4.601 52.248 ;
     RECT  4.565 53.328 4.669 54.936 ;
     RECT  4.601 20.016 4.673 52.248 ;
     RECT  4.529 3.84 4.961 18.984 ;
     RECT  4.169 59.856 4.961 59.88 ;
     RECT  4.673 20.064 5.177 52.248 ;
     RECT  4.961 18.288 5.393 18.984 ;
     RECT  4.133 58.56 5.393 58.776 ;
     RECT  5.393 58.56 5.425 58.728 ;
     RECT  4.961 3.84 5.465 17.112 ;
     RECT  5.465 8.256 5.501 17.112 ;
     RECT  4.669 53.328 5.605 55.464 ;
     RECT  4.529 56.64 5.605 57.048 ;
     RECT  5.605 53.328 5.641 57.048 ;
     RECT  5.465 3.84 5.713 7.272 ;
     RECT  5.641 53.232 5.789 57.048 ;
     RECT  5.425 58.128 5.789 58.728 ;
     RECT  5.789 55.968 5.795 57.048 ;
     RECT  5.177 20.64 5.861 52.248 ;
     RECT  5.393 18.432 6.073 18.984 ;
     RECT  5.713 3.648 6.149 7.272 ;
     RECT  6.073 18.432 6.181 19.608 ;
     RECT  5.861 20.64 6.181 51.768 ;
     RECT  5.789 58.608 6.185 58.728 ;
     RECT  6.149 3.84 6.221 7.272 ;
     RECT  6.221 4.032 6.227 7.272 ;
     RECT  6.227 4.032 6.329 6.936 ;
     RECT  5.789 53.232 6.365 54.936 ;
     RECT  5.501 8.256 6.577 16.872 ;
     RECT  6.181 18.432 6.577 51.768 ;
     RECT  6.577 8.256 6.757 51.768 ;
     RECT  6.329 4.8 6.761 6.936 ;
     RECT  5.795 55.968 6.797 57 ;
     RECT  6.185 58.608 7.189 58.632 ;
     RECT  6.797 56.976 7.261 57 ;
     RECT  6.365 53.808 7.297 54.936 ;
     RECT  6.797 55.968 7.297 55.992 ;
     RECT  7.297 53.808 7.333 55.992 ;
     RECT  6.761 4.8 7.808 5.064 ;
     RECT  6.761 6.288 7.808 6.936 ;
     RECT  6.757 7.92 7.808 51.768 ;
     RECT  7.333 52.8 7.808 55.992 ;
     RECT  7.261 56.976 7.808 57.048 ;
     RECT  7.189 58.128 7.808 58.632 ;
     RECT  7.808 2.148 7.912 62.652 ;
     RECT  7.912 2.418 8.104 62.382 ;
     RECT  8.104 3.936 8.243 5.448 ;
     RECT  8.104 6.576 8.243 51.432 ;
     RECT  8.243 6.576 8.345 16.344 ;
     RECT  8.345 6.576 8.525 9.912 ;
     RECT  8.345 10.992 8.525 16.344 ;
     RECT  8.525 10.992 8.597 16.008 ;
     RECT  8.525 6.576 9.101 8.952 ;
     RECT  8.243 17.616 9.133 51.432 ;
     RECT  8.104 52.416 9.133 54.696 ;
     RECT  8.597 10.992 9.173 15.864 ;
     RECT  9.133 17.616 9.173 54.696 ;
     RECT  8.104 55.824 9.173 58.488 ;
     RECT  9.173 24.288 9.461 54.696 ;
     RECT  9.173 55.824 9.461 55.896 ;
     RECT  9.173 57.264 9.493 58.488 ;
     RECT  9.101 6.576 9.497 8.808 ;
     RECT  9.173 17.616 9.589 22.824 ;
     RECT  8.243 4.272 9.596 5.448 ;
     RECT  9.497 6.576 9.596 8.568 ;
     RECT  9.493 57.264 9.605 58.68 ;
     RECT  9.596 4.272 9.637 8.568 ;
     RECT  9.589 17.088 9.677 22.824 ;
     RECT  9.637 3.936 9.683 8.568 ;
     RECT  9.173 11.088 9.749 15.864 ;
     RECT  9.683 6.576 9.785 8.568 ;
     RECT  9.461 49.536 9.821 54.696 ;
     RECT  9.677 17.76 9.857 22.824 ;
     RECT  9.749 11.088 10.037 15.72 ;
     RECT  9.461 24.288 10.249 48.456 ;
     RECT  9.683 3.936 10.253 5.448 ;
     RECT  9.821 49.536 10.397 54.648 ;
     RECT  10.249 24 10.645 48.456 ;
     RECT  9.529 55.68 10.681 55.704 ;
     RECT  10.681 55.68 10.717 56.088 ;
     RECT  9.605 57.264 10.717 58.488 ;
     RECT  10.037 11.28 10.753 15.72 ;
     RECT  9.961 10.032 10.825 10.056 ;
     RECT  9.857 17.76 10.825 19.848 ;
     RECT  9.857 20.928 10.825 22.824 ;
     RECT  9.785 6.576 10.897 8.52 ;
     RECT  10.717 55.68 10.901 58.488 ;
     RECT  10.825 10.032 10.937 10.296 ;
     RECT  10.253 4.56 11.005 5.448 ;
     RECT  10.897 6.576 11.005 8.808 ;
     RECT  10.825 17.76 11.005 22.824 ;
     RECT  10.645 23.904 11.005 48.456 ;
     RECT  10.901 55.68 11.009 58.008 ;
     RECT  10.753 11.28 11.077 15.864 ;
     RECT  10.397 52.464 11.077 54.648 ;
     RECT  11.009 55.68 11.077 57.72 ;
     RECT  11.005 17.76 11.221 48.456 ;
     RECT  10.397 49.536 11.221 51.336 ;
     RECT  11.077 10.704 11.293 15.864 ;
     RECT  11.005 4.56 11.297 8.808 ;
     RECT  11.293 10.704 11.468 16.2 ;
     RECT  11.297 4.8 11.545 8.808 ;
     RECT  11.221 17.616 11.617 51.336 ;
     RECT  11.077 52.464 11.617 57.72 ;
     RECT  11.468 10.704 11.941 16.44 ;
     RECT  11.617 17.616 11.941 57.72 ;
     RECT  11.545 4.8 12.337 9.336 ;
     RECT  11.941 10.704 12.337 57.72 ;
     RECT  12.229 58.704 12.841 58.728 ;
     RECT  12.337 4.8 13.057 57.72 ;
     RECT  12.841 58.704 13.057 59.064 ;
     RECT  13.057 4.8 13.208 59.064 ;
     RECT  13.208 2.148 13.312 62.652 ;
     RECT  13.312 2.418 13.504 62.382 ;
     RECT  13.504 24.384 13.637 58.92 ;
     RECT  13.637 49.872 13.673 58.92 ;
     RECT  13.504 5.76 14.429 9.672 ;
     RECT  14.429 5.76 14.533 9.384 ;
     RECT  13.673 50.736 14.681 58.92 ;
     RECT  14.681 50.736 14.713 58.392 ;
     RECT  13.504 10.656 14.749 16.536 ;
     RECT  13.504 17.52 14.785 23.256 ;
     RECT  13.637 24.384 14.785 48.792 ;
     RECT  14.785 17.52 14.893 48.792 ;
     RECT  13.504 4.512 14.933 4.536 ;
     RECT  14.893 17.52 15.068 48.984 ;
     RECT  14.713 50.256 15.068 58.392 ;
     RECT  15.068 17.52 15.155 58.392 ;
     RECT  14.749 10.368 15.289 16.536 ;
     RECT  15.155 17.52 15.289 49.032 ;
     RECT  15.155 50.16 15.293 58.392 ;
     RECT  14.533 5.712 15.541 9.384 ;
     RECT  15.289 10.368 15.541 49.032 ;
     RECT  15.293 57.456 15.617 58.392 ;
     RECT  15.541 5.712 15.905 49.032 ;
     RECT  15.865 60.48 15.973 60.504 ;
     RECT  15.617 57.552 16.009 58.392 ;
     RECT  16.009 57.552 16.013 58.728 ;
     RECT  15.973 59.856 16.019 60.504 ;
     RECT  16.013 58.128 16.093 58.728 ;
     RECT  15.905 18.432 16.213 49.032 ;
     RECT  15.293 50.16 16.213 56.376 ;
     RECT  15.253 4.368 16.405 4.392 ;
     RECT  15.905 5.712 16.597 17.4 ;
     RECT  16.405 4.128 16.661 4.392 ;
     RECT  16.597 5.616 16.684 17.4 ;
     RECT  16.684 5.664 16.697 17.4 ;
     RECT  16.697 10.272 16.769 17.4 ;
     RECT  16.697 5.664 16.841 9.288 ;
     RECT  16.769 10.512 16.873 17.4 ;
     RECT  16.213 18.432 16.873 56.376 ;
     RECT  16.661 4.128 17.171 4.152 ;
     RECT  16.873 10.512 17.173 56.472 ;
     RECT  16.093 58.128 17.173 58.392 ;
     RECT  17.173 10.512 17.197 58.392 ;
     RECT  16.019 59.856 17.629 59.928 ;
     RECT  17.197 10.512 17.809 58.68 ;
     RECT  16.841 5.664 17.941 9.24 ;
     RECT  17.941 5.664 17.953 9.288 ;
     RECT  17.809 10.416 17.953 58.68 ;
     RECT  17.953 5.664 18.181 58.68 ;
     RECT  18.181 5.472 18.313 58.68 ;
     RECT  18.313 5.136 18.349 58.68 ;
     RECT  17.629 59.712 18.349 59.928 ;
     RECT  18.349 5.136 18.493 59.928 ;
     RECT  18.493 4.512 18.565 59.928 ;
     RECT  18.565 4.416 18.608 59.928 ;
     RECT  18.608 2.148 18.712 62.652 ;
     RECT  18.712 2.418 18.904 62.382 ;
     RECT  18.904 5.472 18.965 5.496 ;
     RECT  18.904 6.576 19.181 58.968 ;
     RECT  19.181 49.104 19.217 58.968 ;
     RECT  19.217 49.104 19.289 58.296 ;
     RECT  19.181 6.576 19.325 47.928 ;
     RECT  19.325 7.056 20.329 47.928 ;
     RECT  19.289 49.104 20.329 57.48 ;
     RECT  20.329 7.056 20.473 57.48 ;
     RECT  20.473 6.96 20.509 57.48 ;
     RECT  20.509 6.864 21.564 57.48 ;
    LAYER M5 ;
     RECT  2.256 2.137 2.52 2.151 ;
     RECT  7.8 2.137 7.92 2.151 ;
     RECT  13.2 2.137 13.32 2.151 ;
     RECT  18.6 2.137 18.72 2.151 ;
     RECT  2.256 2.151 2.712 3.349 ;
     RECT  0.144 2.245 0.168 3.541 ;
     RECT  7.8 2.151 8.112 3.925 ;
     RECT  0.144 3.541 0.264 4.117 ;
     RECT  13.2 2.151 13.512 4.501 ;
     RECT  0.144 4.117 0.36 4.979 ;
     RECT  7.8 3.925 8.232 5.219 ;
     RECT  2.256 3.349 3.048 5.365 ;
     RECT  18.6 2.151 18.912 5.461 ;
     RECT  17.136 4.117 17.16 5.605 ;
     RECT  0.144 4.979 0.312 5.747 ;
     RECT  9.648 3.925 9.672 6.035 ;
     RECT  4.896 5.509 4.92 6.181 ;
     RECT  6.144 6.181 6.168 6.229 ;
     RECT  16.608 5.605 17.16 6.229 ;
     RECT  18.192 5.461 18.912 6.229 ;
     RECT  16.608 6.229 18.912 6.275 ;
     RECT  0.144 5.747 0.168 6.515 ;
     RECT  2.256 5.365 3.72 6.755 ;
     RECT  6.144 6.229 6.264 6.805 ;
     RECT  13.2 4.501 14.424 6.805 ;
     RECT  4.8 6.181 4.92 7.237 ;
     RECT  5.952 6.805 6.264 7.237 ;
     RECT  15.936 6.565 15.96 7.429 ;
     RECT  17.136 6.275 18.912 7.429 ;
     RECT  7.8 5.219 8.112 7.957 ;
     RECT  2.256 6.755 3.192 8.003 ;
     RECT  4.8 7.237 6.264 8.003 ;
     RECT  5.04 8.003 6.264 8.291 ;
     RECT  13.056 6.805 14.424 8.291 ;
     RECT  7.8 7.957 9.048 8.963 ;
     RECT  5.04 8.291 6.216 9.061 ;
     RECT  0.24 9.109 0.264 9.205 ;
     RECT  0.192 9.205 0.264 9.445 ;
     RECT  0.144 9.445 0.264 9.541 ;
     RECT  2.256 8.003 3.096 9.829 ;
     RECT  4.32 9.061 6.216 9.829 ;
     RECT  0.144 9.541 0.36 10.403 ;
     RECT  13.056 8.291 13.704 10.693 ;
     RECT  2.256 9.829 6.216 10.883 ;
     RECT  13.056 10.693 13.992 10.931 ;
     RECT  11.904 10.837 11.928 11.411 ;
     RECT  6.096 10.883 6.216 11.459 ;
     RECT  15.936 7.429 18.912 11.459 ;
     RECT  18.192 11.459 18.912 11.507 ;
     RECT  7.8 8.963 8.112 11.509 ;
     RECT  0.144 10.403 0.312 11.891 ;
     RECT  15.936 11.459 17.16 12.035 ;
     RECT  2.256 10.883 5.064 12.083 ;
     RECT  13.2 10.931 13.992 12.853 ;
     RECT  7.8 11.509 8.472 13.091 ;
     RECT  12.528 12.853 13.992 13.091 ;
     RECT  2.256 12.083 4.872 13.139 ;
     RECT  6.096 11.459 6.12 13.285 ;
     RECT  0.144 11.891 0.216 13.621 ;
     RECT  12.528 13.091 13.608 13.715 ;
     RECT  5.856 13.285 6.12 13.859 ;
     RECT  2.256 13.139 3.72 14.197 ;
     RECT  4.848 13.139 4.872 14.197 ;
     RECT  12.816 13.715 13.608 14.197 ;
     RECT  0.144 13.621 0.36 14.579 ;
     RECT  12.816 14.197 14.568 15.205 ;
     RECT  15.936 12.035 16.344 15.205 ;
     RECT  0.288 14.579 0.36 15.301 ;
     RECT  0.288 15.301 0.408 15.781 ;
     RECT  7.8 13.091 8.112 15.877 ;
     RECT  12.816 15.205 16.344 16.021 ;
     RECT  0.192 15.781 0.408 16.115 ;
     RECT  6.096 13.859 6.12 16.211 ;
     RECT  0.192 16.115 0.36 16.259 ;
     RECT  7.44 15.877 8.112 16.451 ;
     RECT  18.6 11.507 18.912 16.501 ;
     RECT  12.816 16.021 17.304 16.643 ;
     RECT  0.24 16.259 0.36 16.691 ;
     RECT  0.336 16.691 0.36 16.979 ;
     RECT  7.8 16.451 8.112 17.077 ;
     RECT  10.464 15.301 10.488 17.077 ;
     RECT  11.52 16.405 11.544 17.077 ;
     RECT  12.816 16.643 16.344 17.077 ;
     RECT  18.48 16.501 18.912 17.077 ;
     RECT  7.8 17.077 8.232 17.653 ;
     RECT  7.68 17.653 8.232 17.699 ;
     RECT  11.52 17.077 16.344 17.891 ;
     RECT  2.256 14.197 4.872 18.275 ;
     RECT  11.52 17.891 13.608 18.323 ;
     RECT  0.144 17.989 0.168 18.565 ;
     RECT  6.144 18.565 6.168 18.757 ;
     RECT  7.68 17.699 8.112 18.949 ;
     RECT  9.6 17.077 10.488 18.949 ;
     RECT  0.144 18.565 0.312 19.381 ;
     RECT  7.68 18.949 10.488 19.669 ;
     RECT  11.52 18.323 13.512 19.669 ;
     RECT  14.832 17.891 16.344 19.669 ;
     RECT  6.144 18.757 6.504 19.811 ;
     RECT  2.256 18.275 3.864 19.909 ;
     RECT  4.848 18.275 4.872 19.909 ;
     RECT  0.144 19.381 0.408 20.389 ;
     RECT  7.68 19.669 16.344 20.579 ;
     RECT  17.808 17.077 18.912 20.579 ;
     RECT  0.144 20.389 0.552 20.675 ;
     RECT  2.256 19.909 4.872 20.965 ;
     RECT  6.144 19.811 6.168 20.965 ;
     RECT  17.952 20.579 18.912 21.011 ;
     RECT  21.456 20.725 21.48 21.011 ;
     RECT  0.144 20.675 0.312 21.107 ;
     RECT  0.144 21.107 0.216 21.155 ;
     RECT  2.256 20.965 6.168 21.541 ;
     RECT  2.256 21.541 6.6 22.165 ;
     RECT  7.68 20.579 16.296 22.165 ;
     RECT  2.256 22.165 16.296 22.453 ;
     RECT  0.192 21.155 0.216 22.789 ;
     RECT  2.256 22.453 16.344 23.317 ;
     RECT  2.256 23.317 16.488 23.893 ;
     RECT  2.256 23.893 16.536 24.515 ;
     RECT  0.192 22.789 0.36 25.763 ;
     RECT  2.256 24.515 16.488 26.389 ;
     RECT  18.6 21.011 18.912 26.389 ;
     RECT  21.408 26.485 21.432 26.675 ;
     RECT  0.24 25.763 0.36 26.723 ;
     RECT  18.288 26.389 18.912 26.771 ;
     RECT  0.24 26.723 0.312 27.059 ;
     RECT  2.256 26.389 16.872 27.109 ;
     RECT  0.288 27.059 0.312 27.155 ;
     RECT  2.256 27.109 16.968 27.157 ;
     RECT  2.256 27.157 17.112 27.299 ;
     RECT  18.6 26.771 18.912 28.213 ;
     RECT  18.48 28.213 18.912 28.403 ;
     RECT  2.256 27.299 16.872 28.595 ;
     RECT  0.288 30.757 0.312 30.899 ;
     RECT  0.144 30.997 0.168 31.187 ;
     RECT  2.256 28.595 16.488 32.867 ;
     RECT  2.4 32.867 16.488 35.269 ;
     RECT  2.4 35.269 16.584 35.939 ;
     RECT  1.152 36.277 1.176 36.325 ;
     RECT  1.152 36.325 1.272 36.467 ;
     RECT  2.4 35.939 16.488 36.997 ;
     RECT  2.304 36.997 16.488 38.005 ;
     RECT  0.144 36.805 0.168 38.195 ;
     RECT  18.6 28.403 18.912 38.245 ;
     RECT  18.48 38.245 18.912 38.387 ;
     RECT  2.304 38.005 16.68 38.435 ;
     RECT  2.4 38.435 16.68 39.395 ;
     RECT  16.656 39.395 16.68 39.491 ;
     RECT  16.656 40.981 16.68 41.651 ;
     RECT  0.192 41.653 0.216 41.843 ;
     RECT  2.4 39.395 15.48 41.989 ;
     RECT  2.304 41.989 15.48 42.227 ;
     RECT  0.24 42.565 0.264 43.717 ;
     RECT  16.896 43.285 16.92 44.341 ;
     RECT  15.936 44.341 16.92 44.387 ;
     RECT  2.304 42.227 14.952 44.963 ;
     RECT  0.144 43.717 0.264 44.965 ;
     RECT  2.4 44.963 14.952 45.251 ;
     RECT  2.4 45.251 9.24 45.635 ;
     RECT  10.464 45.251 14.952 45.635 ;
     RECT  2.4 45.635 8.952 45.731 ;
     RECT  2.4 45.731 8.808 46.259 ;
     RECT  10.56 45.635 14.952 46.259 ;
     RECT  0.144 44.965 0.36 46.405 ;
     RECT  10.56 46.259 13.896 46.787 ;
     RECT  14.928 46.259 14.952 46.787 ;
     RECT  15.936 44.387 15.96 46.787 ;
     RECT  0.144 46.405 0.552 47.219 ;
     RECT  2.4 46.259 8.112 47.269 ;
     RECT  10.56 46.787 11.016 47.363 ;
     RECT  18.6 38.387 18.912 47.701 ;
     RECT  10.56 47.363 10.584 47.891 ;
     RECT  2.4 47.269 8.904 48.181 ;
     RECT  2.304 48.181 8.904 48.419 ;
     RECT  12.096 46.787 13.896 48.515 ;
     RECT  18.6 47.701 19.128 48.709 ;
     RECT  12.096 48.515 13.512 48.949 ;
     RECT  18.288 48.709 19.128 49.043 ;
     RECT  15.12 47.845 15.144 49.715 ;
     RECT  16.224 48.277 16.248 49.763 ;
     RECT  2.304 48.419 8.664 50.003 ;
     RECT  11.376 48.949 13.512 50.147 ;
     RECT  0.144 47.219 0.36 50.243 ;
     RECT  2.304 50.003 8.112 50.771 ;
     RECT  7.104 50.771 8.112 50.915 ;
     RECT  0.24 50.243 0.36 51.347 ;
     RECT  7.296 50.915 8.112 51.395 ;
     RECT  0.24 51.347 0.312 51.397 ;
     RECT  17.52 51.253 17.544 51.397 ;
     RECT  18.6 49.043 19.128 51.397 ;
     RECT  7.632 51.395 8.112 51.443 ;
     RECT  12 50.147 13.512 51.683 ;
     RECT  15.216 50.149 15.24 51.781 ;
     RECT  17.52 51.397 19.128 51.923 ;
     RECT  0.144 51.397 0.312 51.971 ;
     RECT  14.784 51.781 15.24 52.069 ;
     RECT  0.144 51.971 0.264 52.163 ;
     RECT  14.496 52.069 15.24 52.163 ;
     RECT  12.24 51.683 13.512 52.405 ;
     RECT  14.496 52.163 14.808 52.405 ;
     RECT  2.304 50.771 5.832 52.499 ;
     RECT  10.8 51.205 10.824 52.499 ;
     RECT  0.24 52.163 0.264 52.547 ;
     RECT  2.304 52.499 3.144 52.595 ;
     RECT  2.304 52.595 3.096 53.557 ;
     RECT  4.128 52.499 5.832 53.557 ;
     RECT  12.24 52.405 14.808 53.557 ;
     RECT  18.48 51.923 18.912 53.557 ;
     RECT  10.848 52.837 10.872 53.795 ;
     RECT  17.04 53.557 18.912 53.843 ;
     RECT  12.24 53.557 15.48 54.083 ;
     RECT  2.304 53.557 5.832 54.085 ;
     RECT  14.784 54.083 15.48 54.085 ;
     RECT  0.144 53.413 0.168 54.179 ;
     RECT  2.304 54.085 6.264 54.371 ;
     RECT  14.784 54.085 16.104 54.371 ;
     RECT  2.4 54.371 6.264 54.563 ;
     RECT  9.216 54.085 9.24 54.707 ;
     RECT  16.08 54.371 16.104 55.331 ;
     RECT  12.24 54.083 13.512 55.957 ;
     RECT  18 53.843 18.912 56.341 ;
     RECT  14.784 54.371 14.808 56.483 ;
     RECT  2.4 54.563 5.784 57.059 ;
     RECT  12.24 55.957 13.608 57.107 ;
     RECT  17.184 56.341 18.912 57.635 ;
     RECT  17.184 57.635 17.208 58.355 ;
     RECT  2.4 57.059 5.592 58.739 ;
     RECT  12.24 57.107 13.512 58.739 ;
     RECT  16.032 58.117 16.056 58.739 ;
     RECT  2.4 58.739 4.152 58.787 ;
     RECT  18.48 57.635 18.912 59.027 ;
     RECT  2.4 58.787 4.008 59.699 ;
     RECT  2.4 59.699 3.576 59.891 ;
     RECT  2.4 59.891 3.48 59.987 ;
     RECT  15.984 59.845 16.008 60.515 ;
     RECT  2.4 59.987 2.712 62.649 ;
     RECT  7.8 51.443 8.112 62.649 ;
     RECT  13.2 58.739 13.512 62.649 ;
     RECT  18.6 59.027 18.912 62.649 ;
     RECT  2.4 62.649 2.52 62.663 ;
     RECT  7.8 62.649 7.92 62.663 ;
     RECT  13.2 62.649 13.32 62.663 ;
     RECT  18.6 62.649 18.72 62.663 ;
  END
END ot_qwen_tree_delay3_t
END LIBRARY
